VERSION 5.8 ;
BUSBITCHARS "[]" ;
DIVIDERCHAR "/" ;
UNITS
    DATABASE MICRONS 1000 ;
END UNITS

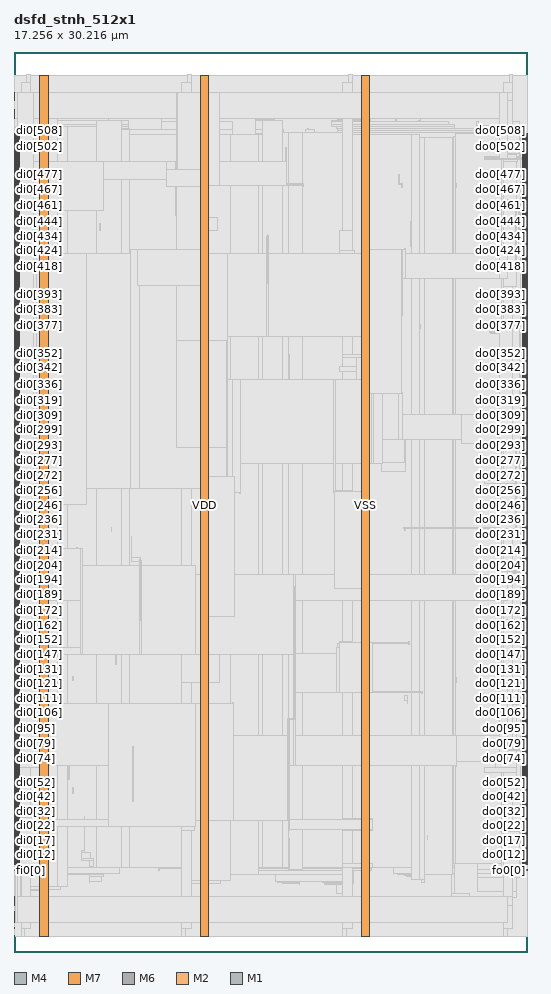
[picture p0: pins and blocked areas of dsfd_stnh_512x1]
MACRO dsfd_stnh_512x1
  FOREIGN dsfd_stnh_512x1 0 0 ;
  CLASS BLOCK ;
  SIZE 17.256 BY 30.216 ;
  PIN di0[0]
    DIRECTION INPUT ;
    USE SIGNAL ;
    PORT
      LAYER M4 ;
        RECT  0 2.928 0.192 2.952 ;
    END
  END di0[0]
  PIN di0[100]
    DIRECTION INPUT ;
    USE SIGNAL ;
    PORT
      LAYER M4 ;
        RECT  0 7.728 0.192 7.752 ;
    END
  END di0[100]
  PIN di0[101]
    DIRECTION INPUT ;
    USE SIGNAL ;
    PORT
      LAYER M4 ;
        RECT  0 7.776 0.192 7.8 ;
    END
  END di0[101]
  PIN di0[102]
    DIRECTION INPUT ;
    USE SIGNAL ;
    PORT
      LAYER M4 ;
        RECT  0 7.824 0.192 7.848 ;
    END
  END di0[102]
  PIN di0[103]
    DIRECTION INPUT ;
    USE SIGNAL ;
    PORT
      LAYER M4 ;
        RECT  0 7.872 0.192 7.896 ;
    END
  END di0[103]
  PIN di0[104]
    DIRECTION INPUT ;
    USE SIGNAL ;
    PORT
      LAYER M4 ;
        RECT  0 7.92 0.192 7.944 ;
    END
  END di0[104]
  PIN di0[105]
    DIRECTION INPUT ;
    USE SIGNAL ;
    PORT
      LAYER M4 ;
        RECT  0 7.968 0.192 7.992 ;
    END
  END di0[105]
  PIN di0[106]
    DIRECTION INPUT ;
    USE SIGNAL ;
    PORT
      LAYER M4 ;
        RECT  0 8.016 0.192 8.04 ;
    END
  END di0[106]
  PIN di0[107]
    DIRECTION INPUT ;
    USE SIGNAL ;
    PORT
      LAYER M4 ;
        RECT  0 8.064 0.192 8.088 ;
    END
  END di0[107]
  PIN di0[108]
    DIRECTION INPUT ;
    USE SIGNAL ;
    PORT
      LAYER M4 ;
        RECT  0 8.112 0.192 8.136 ;
    END
  END di0[108]
  PIN di0[109]
    DIRECTION INPUT ;
    USE SIGNAL ;
    PORT
      LAYER M4 ;
        RECT  0 8.16 0.192 8.184 ;
    END
  END di0[109]
  PIN di0[10]
    DIRECTION INPUT ;
    USE SIGNAL ;
    PORT
      LAYER M4 ;
        RECT  0 3.408 0.192 3.432 ;
    END
  END di0[10]
  PIN di0[110]
    DIRECTION INPUT ;
    USE SIGNAL ;
    PORT
      LAYER M4 ;
        RECT  0 8.208 0.192 8.232 ;
    END
  END di0[110]
  PIN di0[111]
    DIRECTION INPUT ;
    USE SIGNAL ;
    PORT
      LAYER M4 ;
        RECT  0 8.256 0.192 8.28 ;
    END
  END di0[111]
  PIN di0[112]
    DIRECTION INPUT ;
    USE SIGNAL ;
    PORT
      LAYER M4 ;
        RECT  0 8.304 0.192 8.328 ;
    END
  END di0[112]
  PIN di0[113]
    DIRECTION INPUT ;
    USE SIGNAL ;
    PORT
      LAYER M4 ;
        RECT  0 8.352 0.192 8.376 ;
    END
  END di0[113]
  PIN di0[114]
    DIRECTION INPUT ;
    USE SIGNAL ;
    PORT
      LAYER M4 ;
        RECT  0 8.4 0.192 8.424 ;
    END
  END di0[114]
  PIN di0[115]
    DIRECTION INPUT ;
    USE SIGNAL ;
    PORT
      LAYER M4 ;
        RECT  0 8.448 0.192 8.472 ;
    END
  END di0[115]
  PIN di0[116]
    DIRECTION INPUT ;
    USE SIGNAL ;
    PORT
      LAYER M4 ;
        RECT  0 8.496 0.192 8.52 ;
    END
  END di0[116]
  PIN di0[117]
    DIRECTION INPUT ;
    USE SIGNAL ;
    PORT
      LAYER M4 ;
        RECT  0 8.544 0.192 8.568 ;
    END
  END di0[117]
  PIN di0[118]
    DIRECTION INPUT ;
    USE SIGNAL ;
    PORT
      LAYER M4 ;
        RECT  0 8.592 0.192 8.616 ;
    END
  END di0[118]
  PIN di0[119]
    DIRECTION INPUT ;
    USE SIGNAL ;
    PORT
      LAYER M4 ;
        RECT  0 8.64 0.192 8.664 ;
    END
  END di0[119]
  PIN di0[11]
    DIRECTION INPUT ;
    USE SIGNAL ;
    PORT
      LAYER M4 ;
        RECT  0 3.456 0.192 3.48 ;
    END
  END di0[11]
  PIN di0[120]
    DIRECTION INPUT ;
    USE SIGNAL ;
    PORT
      LAYER M4 ;
        RECT  0 8.688 0.192 8.712 ;
    END
  END di0[120]
  PIN di0[121]
    DIRECTION INPUT ;
    USE SIGNAL ;
    PORT
      LAYER M4 ;
        RECT  0 8.736 0.192 8.76 ;
    END
  END di0[121]
  PIN di0[122]
    DIRECTION INPUT ;
    USE SIGNAL ;
    PORT
      LAYER M4 ;
        RECT  0 8.784 0.192 8.808 ;
    END
  END di0[122]
  PIN di0[123]
    DIRECTION INPUT ;
    USE SIGNAL ;
    PORT
      LAYER M4 ;
        RECT  0 8.832 0.192 8.856 ;
    END
  END di0[123]
  PIN di0[124]
    DIRECTION INPUT ;
    USE SIGNAL ;
    PORT
      LAYER M4 ;
        RECT  0 8.88 0.192 8.904 ;
    END
  END di0[124]
  PIN di0[125]
    DIRECTION INPUT ;
    USE SIGNAL ;
    PORT
      LAYER M4 ;
        RECT  0 8.928 0.192 8.952 ;
    END
  END di0[125]
  PIN di0[126]
    DIRECTION INPUT ;
    USE SIGNAL ;
    PORT
      LAYER M4 ;
        RECT  0 8.976 0.192 9 ;
    END
  END di0[126]
  PIN di0[127]
    DIRECTION INPUT ;
    USE SIGNAL ;
    PORT
      LAYER M4 ;
        RECT  0 9.024 0.192 9.048 ;
    END
  END di0[127]
  PIN di0[128]
    DIRECTION INPUT ;
    USE SIGNAL ;
    PORT
      LAYER M4 ;
        RECT  0 9.072 0.192 9.096 ;
    END
  END di0[128]
  PIN di0[129]
    DIRECTION INPUT ;
    USE SIGNAL ;
    PORT
      LAYER M4 ;
        RECT  0 9.12 0.192 9.144 ;
    END
  END di0[129]
  PIN di0[12]
    DIRECTION INPUT ;
    USE SIGNAL ;
    PORT
      LAYER M4 ;
        RECT  0 3.504 0.192 3.528 ;
    END
  END di0[12]
  PIN di0[130]
    DIRECTION INPUT ;
    USE SIGNAL ;
    PORT
      LAYER M4 ;
        RECT  0 9.168 0.192 9.192 ;
    END
  END di0[130]
  PIN di0[131]
    DIRECTION INPUT ;
    USE SIGNAL ;
    PORT
      LAYER M4 ;
        RECT  0 9.216 0.192 9.24 ;
    END
  END di0[131]
  PIN di0[132]
    DIRECTION INPUT ;
    USE SIGNAL ;
    PORT
      LAYER M4 ;
        RECT  0 9.264 0.192 9.288 ;
    END
  END di0[132]
  PIN di0[133]
    DIRECTION INPUT ;
    USE SIGNAL ;
    PORT
      LAYER M4 ;
        RECT  0 9.312 0.192 9.336 ;
    END
  END di0[133]
  PIN di0[134]
    DIRECTION INPUT ;
    USE SIGNAL ;
    PORT
      LAYER M4 ;
        RECT  0 9.36 0.192 9.384 ;
    END
  END di0[134]
  PIN di0[135]
    DIRECTION INPUT ;
    USE SIGNAL ;
    PORT
      LAYER M4 ;
        RECT  0 9.408 0.192 9.432 ;
    END
  END di0[135]
  PIN di0[136]
    DIRECTION INPUT ;
    USE SIGNAL ;
    PORT
      LAYER M4 ;
        RECT  0 9.456 0.192 9.48 ;
    END
  END di0[136]
  PIN di0[137]
    DIRECTION INPUT ;
    USE SIGNAL ;
    PORT
      LAYER M4 ;
        RECT  0 9.504 0.192 9.528 ;
    END
  END di0[137]
  PIN di0[138]
    DIRECTION INPUT ;
    USE SIGNAL ;
    PORT
      LAYER M4 ;
        RECT  0 9.552 0.192 9.576 ;
    END
  END di0[138]
  PIN di0[139]
    DIRECTION INPUT ;
    USE SIGNAL ;
    PORT
      LAYER M4 ;
        RECT  0 9.6 0.192 9.624 ;
    END
  END di0[139]
  PIN di0[13]
    DIRECTION INPUT ;
    USE SIGNAL ;
    PORT
      LAYER M4 ;
        RECT  0 3.552 0.192 3.576 ;
    END
  END di0[13]
  PIN di0[140]
    DIRECTION INPUT ;
    USE SIGNAL ;
    PORT
      LAYER M4 ;
        RECT  0 9.648 0.192 9.672 ;
    END
  END di0[140]
  PIN di0[141]
    DIRECTION INPUT ;
    USE SIGNAL ;
    PORT
      LAYER M4 ;
        RECT  0 9.696 0.192 9.72 ;
    END
  END di0[141]
  PIN di0[142]
    DIRECTION INPUT ;
    USE SIGNAL ;
    PORT
      LAYER M4 ;
        RECT  0 9.744 0.192 9.768 ;
    END
  END di0[142]
  PIN di0[143]
    DIRECTION INPUT ;
    USE SIGNAL ;
    PORT
      LAYER M4 ;
        RECT  0 9.792 0.192 9.816 ;
    END
  END di0[143]
  PIN di0[144]
    DIRECTION INPUT ;
    USE SIGNAL ;
    PORT
      LAYER M4 ;
        RECT  0 9.84 0.192 9.864 ;
    END
  END di0[144]
  PIN di0[145]
    DIRECTION INPUT ;
    USE SIGNAL ;
    PORT
      LAYER M4 ;
        RECT  0 9.888 0.192 9.912 ;
    END
  END di0[145]
  PIN di0[146]
    DIRECTION INPUT ;
    USE SIGNAL ;
    PORT
      LAYER M4 ;
        RECT  0 9.936 0.192 9.96 ;
    END
  END di0[146]
  PIN di0[147]
    DIRECTION INPUT ;
    USE SIGNAL ;
    PORT
      LAYER M4 ;
        RECT  0 9.984 0.192 10.008 ;
    END
  END di0[147]
  PIN di0[148]
    DIRECTION INPUT ;
    USE SIGNAL ;
    PORT
      LAYER M4 ;
        RECT  0 10.032 0.192 10.056 ;
    END
  END di0[148]
  PIN di0[149]
    DIRECTION INPUT ;
    USE SIGNAL ;
    PORT
      LAYER M4 ;
        RECT  0 10.08 0.192 10.104 ;
    END
  END di0[149]
  PIN di0[14]
    DIRECTION INPUT ;
    USE SIGNAL ;
    PORT
      LAYER M4 ;
        RECT  0 3.6 0.192 3.624 ;
    END
  END di0[14]
  PIN di0[150]
    DIRECTION INPUT ;
    USE SIGNAL ;
    PORT
      LAYER M4 ;
        RECT  0 10.128 0.192 10.152 ;
    END
  END di0[150]
  PIN di0[151]
    DIRECTION INPUT ;
    USE SIGNAL ;
    PORT
      LAYER M4 ;
        RECT  0 10.176 0.192 10.2 ;
    END
  END di0[151]
  PIN di0[152]
    DIRECTION INPUT ;
    USE SIGNAL ;
    PORT
      LAYER M4 ;
        RECT  0 10.224 0.192 10.248 ;
    END
  END di0[152]
  PIN di0[153]
    DIRECTION INPUT ;
    USE SIGNAL ;
    PORT
      LAYER M4 ;
        RECT  0 10.272 0.192 10.296 ;
    END
  END di0[153]
  PIN di0[154]
    DIRECTION INPUT ;
    USE SIGNAL ;
    PORT
      LAYER M4 ;
        RECT  0 10.32 0.192 10.344 ;
    END
  END di0[154]
  PIN di0[155]
    DIRECTION INPUT ;
    USE SIGNAL ;
    PORT
      LAYER M4 ;
        RECT  0 10.368 0.192 10.392 ;
    END
  END di0[155]
  PIN di0[156]
    DIRECTION INPUT ;
    USE SIGNAL ;
    PORT
      LAYER M4 ;
        RECT  0 10.416 0.192 10.44 ;
    END
  END di0[156]
  PIN di0[157]
    DIRECTION INPUT ;
    USE SIGNAL ;
    PORT
      LAYER M4 ;
        RECT  0 10.464 0.192 10.488 ;
    END
  END di0[157]
  PIN di0[158]
    DIRECTION INPUT ;
    USE SIGNAL ;
    PORT
      LAYER M4 ;
        RECT  0 10.512 0.192 10.536 ;
    END
  END di0[158]
  PIN di0[159]
    DIRECTION INPUT ;
    USE SIGNAL ;
    PORT
      LAYER M4 ;
        RECT  0 10.56 0.192 10.584 ;
    END
  END di0[159]
  PIN di0[15]
    DIRECTION INPUT ;
    USE SIGNAL ;
    PORT
      LAYER M4 ;
        RECT  0 3.648 0.192 3.672 ;
    END
  END di0[15]
  PIN di0[160]
    DIRECTION INPUT ;
    USE SIGNAL ;
    PORT
      LAYER M4 ;
        RECT  0 10.608 0.192 10.632 ;
    END
  END di0[160]
  PIN di0[161]
    DIRECTION INPUT ;
    USE SIGNAL ;
    PORT
      LAYER M4 ;
        RECT  0 10.656 0.192 10.68 ;
    END
  END di0[161]
  PIN di0[162]
    DIRECTION INPUT ;
    USE SIGNAL ;
    PORT
      LAYER M4 ;
        RECT  0 10.704 0.192 10.728 ;
    END
  END di0[162]
  PIN di0[163]
    DIRECTION INPUT ;
    USE SIGNAL ;
    PORT
      LAYER M4 ;
        RECT  0 10.752 0.192 10.776 ;
    END
  END di0[163]
  PIN di0[164]
    DIRECTION INPUT ;
    USE SIGNAL ;
    PORT
      LAYER M4 ;
        RECT  0 10.8 0.192 10.824 ;
    END
  END di0[164]
  PIN di0[165]
    DIRECTION INPUT ;
    USE SIGNAL ;
    PORT
      LAYER M4 ;
        RECT  0 10.848 0.192 10.872 ;
    END
  END di0[165]
  PIN di0[166]
    DIRECTION INPUT ;
    USE SIGNAL ;
    PORT
      LAYER M4 ;
        RECT  0 10.896 0.192 10.92 ;
    END
  END di0[166]
  PIN di0[167]
    DIRECTION INPUT ;
    USE SIGNAL ;
    PORT
      LAYER M4 ;
        RECT  0 10.944 0.192 10.968 ;
    END
  END di0[167]
  PIN di0[168]
    DIRECTION INPUT ;
    USE SIGNAL ;
    PORT
      LAYER M4 ;
        RECT  0 10.992 0.192 11.016 ;
    END
  END di0[168]
  PIN di0[169]
    DIRECTION INPUT ;
    USE SIGNAL ;
    PORT
      LAYER M4 ;
        RECT  0 11.04 0.192 11.064 ;
    END
  END di0[169]
  PIN di0[16]
    DIRECTION INPUT ;
    USE SIGNAL ;
    PORT
      LAYER M4 ;
        RECT  0 3.696 0.192 3.72 ;
    END
  END di0[16]
  PIN di0[170]
    DIRECTION INPUT ;
    USE SIGNAL ;
    PORT
      LAYER M4 ;
        RECT  0 11.088 0.192 11.112 ;
    END
  END di0[170]
  PIN di0[171]
    DIRECTION INPUT ;
    USE SIGNAL ;
    PORT
      LAYER M4 ;
        RECT  0 11.136 0.192 11.16 ;
    END
  END di0[171]
  PIN di0[172]
    DIRECTION INPUT ;
    USE SIGNAL ;
    PORT
      LAYER M4 ;
        RECT  0 11.184 0.192 11.208 ;
    END
  END di0[172]
  PIN di0[173]
    DIRECTION INPUT ;
    USE SIGNAL ;
    PORT
      LAYER M4 ;
        RECT  0 11.232 0.192 11.256 ;
    END
  END di0[173]
  PIN di0[174]
    DIRECTION INPUT ;
    USE SIGNAL ;
    PORT
      LAYER M4 ;
        RECT  0 11.28 0.192 11.304 ;
    END
  END di0[174]
  PIN di0[175]
    DIRECTION INPUT ;
    USE SIGNAL ;
    PORT
      LAYER M4 ;
        RECT  0 11.328 0.192 11.352 ;
    END
  END di0[175]
  PIN di0[176]
    DIRECTION INPUT ;
    USE SIGNAL ;
    PORT
      LAYER M4 ;
        RECT  0 11.376 0.192 11.4 ;
    END
  END di0[176]
  PIN di0[177]
    DIRECTION INPUT ;
    USE SIGNAL ;
    PORT
      LAYER M4 ;
        RECT  0 11.424 0.192 11.448 ;
    END
  END di0[177]
  PIN di0[178]
    DIRECTION INPUT ;
    USE SIGNAL ;
    PORT
      LAYER M4 ;
        RECT  0 11.472 0.192 11.496 ;
    END
  END di0[178]
  PIN di0[179]
    DIRECTION INPUT ;
    USE SIGNAL ;
    PORT
      LAYER M4 ;
        RECT  0 11.52 0.192 11.544 ;
    END
  END di0[179]
  PIN di0[17]
    DIRECTION INPUT ;
    USE SIGNAL ;
    PORT
      LAYER M4 ;
        RECT  0 3.744 0.192 3.768 ;
    END
  END di0[17]
  PIN di0[180]
    DIRECTION INPUT ;
    USE SIGNAL ;
    PORT
      LAYER M4 ;
        RECT  0 11.568 0.192 11.592 ;
    END
  END di0[180]
  PIN di0[181]
    DIRECTION INPUT ;
    USE SIGNAL ;
    PORT
      LAYER M4 ;
        RECT  0 11.616 0.192 11.64 ;
    END
  END di0[181]
  PIN di0[182]
    DIRECTION INPUT ;
    USE SIGNAL ;
    PORT
      LAYER M4 ;
        RECT  0 11.664 0.192 11.688 ;
    END
  END di0[182]
  PIN di0[183]
    DIRECTION INPUT ;
    USE SIGNAL ;
    PORT
      LAYER M4 ;
        RECT  0 11.712 0.192 11.736 ;
    END
  END di0[183]
  PIN di0[184]
    DIRECTION INPUT ;
    USE SIGNAL ;
    PORT
      LAYER M4 ;
        RECT  0 11.76 0.192 11.784 ;
    END
  END di0[184]
  PIN di0[185]
    DIRECTION INPUT ;
    USE SIGNAL ;
    PORT
      LAYER M4 ;
        RECT  0 11.808 0.192 11.832 ;
    END
  END di0[185]
  PIN di0[186]
    DIRECTION INPUT ;
    USE SIGNAL ;
    PORT
      LAYER M4 ;
        RECT  0 11.856 0.192 11.88 ;
    END
  END di0[186]
  PIN di0[187]
    DIRECTION INPUT ;
    USE SIGNAL ;
    PORT
      LAYER M4 ;
        RECT  0 11.904 0.192 11.928 ;
    END
  END di0[187]
  PIN di0[188]
    DIRECTION INPUT ;
    USE SIGNAL ;
    PORT
      LAYER M4 ;
        RECT  0 11.952 0.192 11.976 ;
    END
  END di0[188]
  PIN di0[189]
    DIRECTION INPUT ;
    USE SIGNAL ;
    PORT
      LAYER M4 ;
        RECT  0 12 0.192 12.024 ;
    END
  END di0[189]
  PIN di0[18]
    DIRECTION INPUT ;
    USE SIGNAL ;
    PORT
      LAYER M4 ;
        RECT  0 3.792 0.192 3.816 ;
    END
  END di0[18]
  PIN di0[190]
    DIRECTION INPUT ;
    USE SIGNAL ;
    PORT
      LAYER M4 ;
        RECT  0 12.048 0.192 12.072 ;
    END
  END di0[190]
  PIN di0[191]
    DIRECTION INPUT ;
    USE SIGNAL ;
    PORT
      LAYER M4 ;
        RECT  0 12.096 0.192 12.12 ;
    END
  END di0[191]
  PIN di0[192]
    DIRECTION INPUT ;
    USE SIGNAL ;
    PORT
      LAYER M4 ;
        RECT  0 12.144 0.192 12.168 ;
    END
  END di0[192]
  PIN di0[193]
    DIRECTION INPUT ;
    USE SIGNAL ;
    PORT
      LAYER M4 ;
        RECT  0 12.192 0.192 12.216 ;
    END
  END di0[193]
  PIN di0[194]
    DIRECTION INPUT ;
    USE SIGNAL ;
    PORT
      LAYER M4 ;
        RECT  0 12.24 0.192 12.264 ;
    END
  END di0[194]
  PIN di0[195]
    DIRECTION INPUT ;
    USE SIGNAL ;
    PORT
      LAYER M4 ;
        RECT  0 12.288 0.192 12.312 ;
    END
  END di0[195]
  PIN di0[196]
    DIRECTION INPUT ;
    USE SIGNAL ;
    PORT
      LAYER M4 ;
        RECT  0 12.336 0.192 12.36 ;
    END
  END di0[196]
  PIN di0[197]
    DIRECTION INPUT ;
    USE SIGNAL ;
    PORT
      LAYER M4 ;
        RECT  0 12.384 0.192 12.408 ;
    END
  END di0[197]
  PIN di0[198]
    DIRECTION INPUT ;
    USE SIGNAL ;
    PORT
      LAYER M4 ;
        RECT  0 12.432 0.192 12.456 ;
    END
  END di0[198]
  PIN di0[199]
    DIRECTION INPUT ;
    USE SIGNAL ;
    PORT
      LAYER M4 ;
        RECT  0 12.48 0.192 12.504 ;
    END
  END di0[199]
  PIN di0[19]
    DIRECTION INPUT ;
    USE SIGNAL ;
    PORT
      LAYER M4 ;
        RECT  0 3.84 0.192 3.864 ;
    END
  END di0[19]
  PIN di0[1]
    DIRECTION INPUT ;
    USE SIGNAL ;
    PORT
      LAYER M4 ;
        RECT  0 2.976 0.192 3 ;
    END
  END di0[1]
  PIN di0[200]
    DIRECTION INPUT ;
    USE SIGNAL ;
    PORT
      LAYER M4 ;
        RECT  0 12.528 0.192 12.552 ;
    END
  END di0[200]
  PIN di0[201]
    DIRECTION INPUT ;
    USE SIGNAL ;
    PORT
      LAYER M4 ;
        RECT  0 12.576 0.192 12.6 ;
    END
  END di0[201]
  PIN di0[202]
    DIRECTION INPUT ;
    USE SIGNAL ;
    PORT
      LAYER M4 ;
        RECT  0 12.624 0.192 12.648 ;
    END
  END di0[202]
  PIN di0[203]
    DIRECTION INPUT ;
    USE SIGNAL ;
    PORT
      LAYER M4 ;
        RECT  0 12.672 0.192 12.696 ;
    END
  END di0[203]
  PIN di0[204]
    DIRECTION INPUT ;
    USE SIGNAL ;
    PORT
      LAYER M4 ;
        RECT  0 12.72 0.192 12.744 ;
    END
  END di0[204]
  PIN di0[205]
    DIRECTION INPUT ;
    USE SIGNAL ;
    PORT
      LAYER M4 ;
        RECT  0 12.768 0.192 12.792 ;
    END
  END di0[205]
  PIN di0[206]
    DIRECTION INPUT ;
    USE SIGNAL ;
    PORT
      LAYER M4 ;
        RECT  0 12.816 0.192 12.84 ;
    END
  END di0[206]
  PIN di0[207]
    DIRECTION INPUT ;
    USE SIGNAL ;
    PORT
      LAYER M4 ;
        RECT  0 12.864 0.192 12.888 ;
    END
  END di0[207]
  PIN di0[208]
    DIRECTION INPUT ;
    USE SIGNAL ;
    PORT
      LAYER M4 ;
        RECT  0 12.912 0.192 12.936 ;
    END
  END di0[208]
  PIN di0[209]
    DIRECTION INPUT ;
    USE SIGNAL ;
    PORT
      LAYER M4 ;
        RECT  0 12.96 0.192 12.984 ;
    END
  END di0[209]
  PIN di0[20]
    DIRECTION INPUT ;
    USE SIGNAL ;
    PORT
      LAYER M4 ;
        RECT  0 3.888 0.192 3.912 ;
    END
  END di0[20]
  PIN di0[210]
    DIRECTION INPUT ;
    USE SIGNAL ;
    PORT
      LAYER M4 ;
        RECT  0 13.008 0.192 13.032 ;
    END
  END di0[210]
  PIN di0[211]
    DIRECTION INPUT ;
    USE SIGNAL ;
    PORT
      LAYER M4 ;
        RECT  0 13.056 0.192 13.08 ;
    END
  END di0[211]
  PIN di0[212]
    DIRECTION INPUT ;
    USE SIGNAL ;
    PORT
      LAYER M4 ;
        RECT  0 13.104 0.192 13.128 ;
    END
  END di0[212]
  PIN di0[213]
    DIRECTION INPUT ;
    USE SIGNAL ;
    PORT
      LAYER M4 ;
        RECT  0 13.152 0.192 13.176 ;
    END
  END di0[213]
  PIN di0[214]
    DIRECTION INPUT ;
    USE SIGNAL ;
    PORT
      LAYER M4 ;
        RECT  0 13.2 0.192 13.224 ;
    END
  END di0[214]
  PIN di0[215]
    DIRECTION INPUT ;
    USE SIGNAL ;
    PORT
      LAYER M4 ;
        RECT  0 13.248 0.192 13.272 ;
    END
  END di0[215]
  PIN di0[216]
    DIRECTION INPUT ;
    USE SIGNAL ;
    PORT
      LAYER M4 ;
        RECT  0 13.296 0.192 13.32 ;
    END
  END di0[216]
  PIN di0[217]
    DIRECTION INPUT ;
    USE SIGNAL ;
    PORT
      LAYER M4 ;
        RECT  0 13.344 0.192 13.368 ;
    END
  END di0[217]
  PIN di0[218]
    DIRECTION INPUT ;
    USE SIGNAL ;
    PORT
      LAYER M4 ;
        RECT  0 13.392 0.192 13.416 ;
    END
  END di0[218]
  PIN di0[219]
    DIRECTION INPUT ;
    USE SIGNAL ;
    PORT
      LAYER M4 ;
        RECT  0 13.44 0.192 13.464 ;
    END
  END di0[219]
  PIN di0[21]
    DIRECTION INPUT ;
    USE SIGNAL ;
    PORT
      LAYER M4 ;
        RECT  0 3.936 0.192 3.96 ;
    END
  END di0[21]
  PIN di0[220]
    DIRECTION INPUT ;
    USE SIGNAL ;
    PORT
      LAYER M4 ;
        RECT  0 13.488 0.192 13.512 ;
    END
  END di0[220]
  PIN di0[221]
    DIRECTION INPUT ;
    USE SIGNAL ;
    PORT
      LAYER M4 ;
        RECT  0 13.536 0.192 13.56 ;
    END
  END di0[221]
  PIN di0[222]
    DIRECTION INPUT ;
    USE SIGNAL ;
    PORT
      LAYER M4 ;
        RECT  0 13.584 0.192 13.608 ;
    END
  END di0[222]
  PIN di0[223]
    DIRECTION INPUT ;
    USE SIGNAL ;
    PORT
      LAYER M4 ;
        RECT  0 13.632 0.192 13.656 ;
    END
  END di0[223]
  PIN di0[224]
    DIRECTION INPUT ;
    USE SIGNAL ;
    PORT
      LAYER M4 ;
        RECT  0 13.68 0.192 13.704 ;
    END
  END di0[224]
  PIN di0[225]
    DIRECTION INPUT ;
    USE SIGNAL ;
    PORT
      LAYER M4 ;
        RECT  0 13.728 0.192 13.752 ;
    END
  END di0[225]
  PIN di0[226]
    DIRECTION INPUT ;
    USE SIGNAL ;
    PORT
      LAYER M4 ;
        RECT  0 13.776 0.192 13.8 ;
    END
  END di0[226]
  PIN di0[227]
    DIRECTION INPUT ;
    USE SIGNAL ;
    PORT
      LAYER M4 ;
        RECT  0 13.824 0.192 13.848 ;
    END
  END di0[227]
  PIN di0[228]
    DIRECTION INPUT ;
    USE SIGNAL ;
    PORT
      LAYER M4 ;
        RECT  0 13.872 0.192 13.896 ;
    END
  END di0[228]
  PIN di0[229]
    DIRECTION INPUT ;
    USE SIGNAL ;
    PORT
      LAYER M4 ;
        RECT  0 13.92 0.192 13.944 ;
    END
  END di0[229]
  PIN di0[22]
    DIRECTION INPUT ;
    USE SIGNAL ;
    PORT
      LAYER M4 ;
        RECT  0 3.984 0.192 4.008 ;
    END
  END di0[22]
  PIN di0[230]
    DIRECTION INPUT ;
    USE SIGNAL ;
    PORT
      LAYER M4 ;
        RECT  0 13.968 0.192 13.992 ;
    END
  END di0[230]
  PIN di0[231]
    DIRECTION INPUT ;
    USE SIGNAL ;
    PORT
      LAYER M4 ;
        RECT  0 14.016 0.192 14.04 ;
    END
  END di0[231]
  PIN di0[232]
    DIRECTION INPUT ;
    USE SIGNAL ;
    PORT
      LAYER M4 ;
        RECT  0 14.064 0.192 14.088 ;
    END
  END di0[232]
  PIN di0[233]
    DIRECTION INPUT ;
    USE SIGNAL ;
    PORT
      LAYER M4 ;
        RECT  0 14.112 0.192 14.136 ;
    END
  END di0[233]
  PIN di0[234]
    DIRECTION INPUT ;
    USE SIGNAL ;
    PORT
      LAYER M4 ;
        RECT  0 14.16 0.192 14.184 ;
    END
  END di0[234]
  PIN di0[235]
    DIRECTION INPUT ;
    USE SIGNAL ;
    PORT
      LAYER M4 ;
        RECT  0 14.208 0.192 14.232 ;
    END
  END di0[235]
  PIN di0[236]
    DIRECTION INPUT ;
    USE SIGNAL ;
    PORT
      LAYER M4 ;
        RECT  0 14.256 0.192 14.28 ;
    END
  END di0[236]
  PIN di0[237]
    DIRECTION INPUT ;
    USE SIGNAL ;
    PORT
      LAYER M4 ;
        RECT  0 14.304 0.192 14.328 ;
    END
  END di0[237]
  PIN di0[238]
    DIRECTION INPUT ;
    USE SIGNAL ;
    PORT
      LAYER M4 ;
        RECT  0 14.352 0.192 14.376 ;
    END
  END di0[238]
  PIN di0[239]
    DIRECTION INPUT ;
    USE SIGNAL ;
    PORT
      LAYER M4 ;
        RECT  0 14.4 0.192 14.424 ;
    END
  END di0[239]
  PIN di0[23]
    DIRECTION INPUT ;
    USE SIGNAL ;
    PORT
      LAYER M4 ;
        RECT  0 4.032 0.192 4.056 ;
    END
  END di0[23]
  PIN di0[240]
    DIRECTION INPUT ;
    USE SIGNAL ;
    PORT
      LAYER M4 ;
        RECT  0 14.448 0.192 14.472 ;
    END
  END di0[240]
  PIN di0[241]
    DIRECTION INPUT ;
    USE SIGNAL ;
    PORT
      LAYER M4 ;
        RECT  0 14.496 0.192 14.52 ;
    END
  END di0[241]
  PIN di0[242]
    DIRECTION INPUT ;
    USE SIGNAL ;
    PORT
      LAYER M4 ;
        RECT  0 14.544 0.192 14.568 ;
    END
  END di0[242]
  PIN di0[243]
    DIRECTION INPUT ;
    USE SIGNAL ;
    PORT
      LAYER M4 ;
        RECT  0 14.592 0.192 14.616 ;
    END
  END di0[243]
  PIN di0[244]
    DIRECTION INPUT ;
    USE SIGNAL ;
    PORT
      LAYER M4 ;
        RECT  0 14.64 0.192 14.664 ;
    END
  END di0[244]
  PIN di0[245]
    DIRECTION INPUT ;
    USE SIGNAL ;
    PORT
      LAYER M4 ;
        RECT  0 14.688 0.192 14.712 ;
    END
  END di0[245]
  PIN di0[246]
    DIRECTION INPUT ;
    USE SIGNAL ;
    PORT
      LAYER M4 ;
        RECT  0 14.736 0.192 14.76 ;
    END
  END di0[246]
  PIN di0[247]
    DIRECTION INPUT ;
    USE SIGNAL ;
    PORT
      LAYER M4 ;
        RECT  0 14.784 0.192 14.808 ;
    END
  END di0[247]
  PIN di0[248]
    DIRECTION INPUT ;
    USE SIGNAL ;
    PORT
      LAYER M4 ;
        RECT  0 14.832 0.192 14.856 ;
    END
  END di0[248]
  PIN di0[249]
    DIRECTION INPUT ;
    USE SIGNAL ;
    PORT
      LAYER M4 ;
        RECT  0 14.88 0.192 14.904 ;
    END
  END di0[249]
  PIN di0[24]
    DIRECTION INPUT ;
    USE SIGNAL ;
    PORT
      LAYER M4 ;
        RECT  0 4.08 0.192 4.104 ;
    END
  END di0[24]
  PIN di0[250]
    DIRECTION INPUT ;
    USE SIGNAL ;
    PORT
      LAYER M4 ;
        RECT  0 14.928 0.192 14.952 ;
    END
  END di0[250]
  PIN di0[251]
    DIRECTION INPUT ;
    USE SIGNAL ;
    PORT
      LAYER M4 ;
        RECT  0 14.976 0.192 15 ;
    END
  END di0[251]
  PIN di0[252]
    DIRECTION INPUT ;
    USE SIGNAL ;
    PORT
      LAYER M4 ;
        RECT  0 15.024 0.192 15.048 ;
    END
  END di0[252]
  PIN di0[253]
    DIRECTION INPUT ;
    USE SIGNAL ;
    PORT
      LAYER M4 ;
        RECT  0 15.072 0.192 15.096 ;
    END
  END di0[253]
  PIN di0[254]
    DIRECTION INPUT ;
    USE SIGNAL ;
    PORT
      LAYER M4 ;
        RECT  0 15.12 0.192 15.144 ;
    END
  END di0[254]
  PIN di0[255]
    DIRECTION INPUT ;
    USE SIGNAL ;
    PORT
      LAYER M4 ;
        RECT  0 15.168 0.192 15.192 ;
    END
  END di0[255]
  PIN di0[256]
    DIRECTION INPUT ;
    USE SIGNAL ;
    PORT
      LAYER M4 ;
        RECT  0 15.216 0.192 15.24 ;
    END
  END di0[256]
  PIN di0[257]
    DIRECTION INPUT ;
    USE SIGNAL ;
    PORT
      LAYER M4 ;
        RECT  0 15.264 0.192 15.288 ;
    END
  END di0[257]
  PIN di0[258]
    DIRECTION INPUT ;
    USE SIGNAL ;
    PORT
      LAYER M4 ;
        RECT  0 15.312 0.192 15.336 ;
    END
  END di0[258]
  PIN di0[259]
    DIRECTION INPUT ;
    USE SIGNAL ;
    PORT
      LAYER M4 ;
        RECT  0 15.36 0.192 15.384 ;
    END
  END di0[259]
  PIN di0[25]
    DIRECTION INPUT ;
    USE SIGNAL ;
    PORT
      LAYER M4 ;
        RECT  0 4.128 0.192 4.152 ;
    END
  END di0[25]
  PIN di0[260]
    DIRECTION INPUT ;
    USE SIGNAL ;
    PORT
      LAYER M4 ;
        RECT  0 15.408 0.192 15.432 ;
    END
  END di0[260]
  PIN di0[261]
    DIRECTION INPUT ;
    USE SIGNAL ;
    PORT
      LAYER M4 ;
        RECT  0 15.456 0.192 15.48 ;
    END
  END di0[261]
  PIN di0[262]
    DIRECTION INPUT ;
    USE SIGNAL ;
    PORT
      LAYER M4 ;
        RECT  0 15.504 0.192 15.528 ;
    END
  END di0[262]
  PIN di0[263]
    DIRECTION INPUT ;
    USE SIGNAL ;
    PORT
      LAYER M4 ;
        RECT  0 15.552 0.192 15.576 ;
    END
  END di0[263]
  PIN di0[264]
    DIRECTION INPUT ;
    USE SIGNAL ;
    PORT
      LAYER M4 ;
        RECT  0 15.6 0.192 15.624 ;
    END
  END di0[264]
  PIN di0[265]
    DIRECTION INPUT ;
    USE SIGNAL ;
    PORT
      LAYER M4 ;
        RECT  0 15.648 0.192 15.672 ;
    END
  END di0[265]
  PIN di0[266]
    DIRECTION INPUT ;
    USE SIGNAL ;
    PORT
      LAYER M4 ;
        RECT  0 15.696 0.192 15.72 ;
    END
  END di0[266]
  PIN di0[267]
    DIRECTION INPUT ;
    USE SIGNAL ;
    PORT
      LAYER M4 ;
        RECT  0 15.744 0.192 15.768 ;
    END
  END di0[267]
  PIN di0[268]
    DIRECTION INPUT ;
    USE SIGNAL ;
    PORT
      LAYER M4 ;
        RECT  0 15.792 0.192 15.816 ;
    END
  END di0[268]
  PIN di0[269]
    DIRECTION INPUT ;
    USE SIGNAL ;
    PORT
      LAYER M4 ;
        RECT  0 15.84 0.192 15.864 ;
    END
  END di0[269]
  PIN di0[26]
    DIRECTION INPUT ;
    USE SIGNAL ;
    PORT
      LAYER M4 ;
        RECT  0 4.176 0.192 4.2 ;
    END
  END di0[26]
  PIN di0[270]
    DIRECTION INPUT ;
    USE SIGNAL ;
    PORT
      LAYER M4 ;
        RECT  0 15.888 0.192 15.912 ;
    END
  END di0[270]
  PIN di0[271]
    DIRECTION INPUT ;
    USE SIGNAL ;
    PORT
      LAYER M4 ;
        RECT  0 15.936 0.192 15.96 ;
    END
  END di0[271]
  PIN di0[272]
    DIRECTION INPUT ;
    USE SIGNAL ;
    PORT
      LAYER M4 ;
        RECT  0 15.984 0.192 16.008 ;
    END
  END di0[272]
  PIN di0[273]
    DIRECTION INPUT ;
    USE SIGNAL ;
    PORT
      LAYER M4 ;
        RECT  0 16.032 0.192 16.056 ;
    END
  END di0[273]
  PIN di0[274]
    DIRECTION INPUT ;
    USE SIGNAL ;
    PORT
      LAYER M4 ;
        RECT  0 16.08 0.192 16.104 ;
    END
  END di0[274]
  PIN di0[275]
    DIRECTION INPUT ;
    USE SIGNAL ;
    PORT
      LAYER M4 ;
        RECT  0 16.128 0.192 16.152 ;
    END
  END di0[275]
  PIN di0[276]
    DIRECTION INPUT ;
    USE SIGNAL ;
    PORT
      LAYER M4 ;
        RECT  0 16.176 0.192 16.2 ;
    END
  END di0[276]
  PIN di0[277]
    DIRECTION INPUT ;
    USE SIGNAL ;
    PORT
      LAYER M4 ;
        RECT  0 16.224 0.192 16.248 ;
    END
  END di0[277]
  PIN di0[278]
    DIRECTION INPUT ;
    USE SIGNAL ;
    PORT
      LAYER M4 ;
        RECT  0 16.272 0.192 16.296 ;
    END
  END di0[278]
  PIN di0[279]
    DIRECTION INPUT ;
    USE SIGNAL ;
    PORT
      LAYER M4 ;
        RECT  0 16.32 0.192 16.344 ;
    END
  END di0[279]
  PIN di0[27]
    DIRECTION INPUT ;
    USE SIGNAL ;
    PORT
      LAYER M4 ;
        RECT  0 4.224 0.192 4.248 ;
    END
  END di0[27]
  PIN di0[280]
    DIRECTION INPUT ;
    USE SIGNAL ;
    PORT
      LAYER M4 ;
        RECT  0 16.368 0.192 16.392 ;
    END
  END di0[280]
  PIN di0[281]
    DIRECTION INPUT ;
    USE SIGNAL ;
    PORT
      LAYER M4 ;
        RECT  0 16.416 0.192 16.44 ;
    END
  END di0[281]
  PIN di0[282]
    DIRECTION INPUT ;
    USE SIGNAL ;
    PORT
      LAYER M4 ;
        RECT  0 16.464 0.192 16.488 ;
    END
  END di0[282]
  PIN di0[283]
    DIRECTION INPUT ;
    USE SIGNAL ;
    PORT
      LAYER M4 ;
        RECT  0 16.512 0.192 16.536 ;
    END
  END di0[283]
  PIN di0[284]
    DIRECTION INPUT ;
    USE SIGNAL ;
    PORT
      LAYER M4 ;
        RECT  0 16.56 0.192 16.584 ;
    END
  END di0[284]
  PIN di0[285]
    DIRECTION INPUT ;
    USE SIGNAL ;
    PORT
      LAYER M4 ;
        RECT  0 16.608 0.192 16.632 ;
    END
  END di0[285]
  PIN di0[286]
    DIRECTION INPUT ;
    USE SIGNAL ;
    PORT
      LAYER M4 ;
        RECT  0 16.656 0.192 16.68 ;
    END
  END di0[286]
  PIN di0[287]
    DIRECTION INPUT ;
    USE SIGNAL ;
    PORT
      LAYER M4 ;
        RECT  0 16.704 0.192 16.728 ;
    END
  END di0[287]
  PIN di0[288]
    DIRECTION INPUT ;
    USE SIGNAL ;
    PORT
      LAYER M4 ;
        RECT  0 16.752 0.192 16.776 ;
    END
  END di0[288]
  PIN di0[289]
    DIRECTION INPUT ;
    USE SIGNAL ;
    PORT
      LAYER M4 ;
        RECT  0 16.8 0.192 16.824 ;
    END
  END di0[289]
  PIN di0[28]
    DIRECTION INPUT ;
    USE SIGNAL ;
    PORT
      LAYER M4 ;
        RECT  0 4.272 0.192 4.296 ;
    END
  END di0[28]
  PIN di0[290]
    DIRECTION INPUT ;
    USE SIGNAL ;
    PORT
      LAYER M4 ;
        RECT  0 16.848 0.192 16.872 ;
    END
  END di0[290]
  PIN di0[291]
    DIRECTION INPUT ;
    USE SIGNAL ;
    PORT
      LAYER M4 ;
        RECT  0 16.896 0.192 16.92 ;
    END
  END di0[291]
  PIN di0[292]
    DIRECTION INPUT ;
    USE SIGNAL ;
    PORT
      LAYER M4 ;
        RECT  0 16.944 0.192 16.968 ;
    END
  END di0[292]
  PIN di0[293]
    DIRECTION INPUT ;
    USE SIGNAL ;
    PORT
      LAYER M4 ;
        RECT  0 16.992 0.192 17.016 ;
    END
  END di0[293]
  PIN di0[294]
    DIRECTION INPUT ;
    USE SIGNAL ;
    PORT
      LAYER M4 ;
        RECT  0 17.04 0.192 17.064 ;
    END
  END di0[294]
  PIN di0[295]
    DIRECTION INPUT ;
    USE SIGNAL ;
    PORT
      LAYER M4 ;
        RECT  0 17.088 0.192 17.112 ;
    END
  END di0[295]
  PIN di0[296]
    DIRECTION INPUT ;
    USE SIGNAL ;
    PORT
      LAYER M4 ;
        RECT  0 17.136 0.192 17.16 ;
    END
  END di0[296]
  PIN di0[297]
    DIRECTION INPUT ;
    USE SIGNAL ;
    PORT
      LAYER M4 ;
        RECT  0 17.184 0.192 17.208 ;
    END
  END di0[297]
  PIN di0[298]
    DIRECTION INPUT ;
    USE SIGNAL ;
    PORT
      LAYER M4 ;
        RECT  0 17.232 0.192 17.256 ;
    END
  END di0[298]
  PIN di0[299]
    DIRECTION INPUT ;
    USE SIGNAL ;
    PORT
      LAYER M4 ;
        RECT  0 17.28 0.192 17.304 ;
    END
  END di0[299]
  PIN di0[29]
    DIRECTION INPUT ;
    USE SIGNAL ;
    PORT
      LAYER M4 ;
        RECT  0 4.32 0.192 4.344 ;
    END
  END di0[29]
  PIN di0[2]
    DIRECTION INPUT ;
    USE SIGNAL ;
    PORT
      LAYER M4 ;
        RECT  0 3.024 0.192 3.048 ;
    END
  END di0[2]
  PIN di0[300]
    DIRECTION INPUT ;
    USE SIGNAL ;
    PORT
      LAYER M4 ;
        RECT  0 17.328 0.192 17.352 ;
    END
  END di0[300]
  PIN di0[301]
    DIRECTION INPUT ;
    USE SIGNAL ;
    PORT
      LAYER M4 ;
        RECT  0 17.376 0.192 17.4 ;
    END
  END di0[301]
  PIN di0[302]
    DIRECTION INPUT ;
    USE SIGNAL ;
    PORT
      LAYER M4 ;
        RECT  0 17.424 0.192 17.448 ;
    END
  END di0[302]
  PIN di0[303]
    DIRECTION INPUT ;
    USE SIGNAL ;
    PORT
      LAYER M4 ;
        RECT  0 17.472 0.192 17.496 ;
    END
  END di0[303]
  PIN di0[304]
    DIRECTION INPUT ;
    USE SIGNAL ;
    PORT
      LAYER M4 ;
        RECT  0 17.52 0.192 17.544 ;
    END
  END di0[304]
  PIN di0[305]
    DIRECTION INPUT ;
    USE SIGNAL ;
    PORT
      LAYER M4 ;
        RECT  0 17.568 0.192 17.592 ;
    END
  END di0[305]
  PIN di0[306]
    DIRECTION INPUT ;
    USE SIGNAL ;
    PORT
      LAYER M4 ;
        RECT  0 17.616 0.192 17.64 ;
    END
  END di0[306]
  PIN di0[307]
    DIRECTION INPUT ;
    USE SIGNAL ;
    PORT
      LAYER M4 ;
        RECT  0 17.664 0.192 17.688 ;
    END
  END di0[307]
  PIN di0[308]
    DIRECTION INPUT ;
    USE SIGNAL ;
    PORT
      LAYER M4 ;
        RECT  0 17.712 0.192 17.736 ;
    END
  END di0[308]
  PIN di0[309]
    DIRECTION INPUT ;
    USE SIGNAL ;
    PORT
      LAYER M4 ;
        RECT  0 17.76 0.192 17.784 ;
    END
  END di0[309]
  PIN di0[30]
    DIRECTION INPUT ;
    USE SIGNAL ;
    PORT
      LAYER M4 ;
        RECT  0 4.368 0.192 4.392 ;
    END
  END di0[30]
  PIN di0[310]
    DIRECTION INPUT ;
    USE SIGNAL ;
    PORT
      LAYER M4 ;
        RECT  0 17.808 0.192 17.832 ;
    END
  END di0[310]
  PIN di0[311]
    DIRECTION INPUT ;
    USE SIGNAL ;
    PORT
      LAYER M4 ;
        RECT  0 17.856 0.192 17.88 ;
    END
  END di0[311]
  PIN di0[312]
    DIRECTION INPUT ;
    USE SIGNAL ;
    PORT
      LAYER M4 ;
        RECT  0 17.904 0.192 17.928 ;
    END
  END di0[312]
  PIN di0[313]
    DIRECTION INPUT ;
    USE SIGNAL ;
    PORT
      LAYER M4 ;
        RECT  0 17.952 0.192 17.976 ;
    END
  END di0[313]
  PIN di0[314]
    DIRECTION INPUT ;
    USE SIGNAL ;
    PORT
      LAYER M4 ;
        RECT  0 18 0.192 18.024 ;
    END
  END di0[314]
  PIN di0[315]
    DIRECTION INPUT ;
    USE SIGNAL ;
    PORT
      LAYER M4 ;
        RECT  0 18.048 0.192 18.072 ;
    END
  END di0[315]
  PIN di0[316]
    DIRECTION INPUT ;
    USE SIGNAL ;
    PORT
      LAYER M4 ;
        RECT  0 18.096 0.192 18.12 ;
    END
  END di0[316]
  PIN di0[317]
    DIRECTION INPUT ;
    USE SIGNAL ;
    PORT
      LAYER M4 ;
        RECT  0 18.144 0.192 18.168 ;
    END
  END di0[317]
  PIN di0[318]
    DIRECTION INPUT ;
    USE SIGNAL ;
    PORT
      LAYER M4 ;
        RECT  0 18.192 0.192 18.216 ;
    END
  END di0[318]
  PIN di0[319]
    DIRECTION INPUT ;
    USE SIGNAL ;
    PORT
      LAYER M4 ;
        RECT  0 18.24 0.192 18.264 ;
    END
  END di0[319]
  PIN di0[31]
    DIRECTION INPUT ;
    USE SIGNAL ;
    PORT
      LAYER M4 ;
        RECT  0 4.416 0.192 4.44 ;
    END
  END di0[31]
  PIN di0[320]
    DIRECTION INPUT ;
    USE SIGNAL ;
    PORT
      LAYER M4 ;
        RECT  0 18.288 0.192 18.312 ;
    END
  END di0[320]
  PIN di0[321]
    DIRECTION INPUT ;
    USE SIGNAL ;
    PORT
      LAYER M4 ;
        RECT  0 18.336 0.192 18.36 ;
    END
  END di0[321]
  PIN di0[322]
    DIRECTION INPUT ;
    USE SIGNAL ;
    PORT
      LAYER M4 ;
        RECT  0 18.384 0.192 18.408 ;
    END
  END di0[322]
  PIN di0[323]
    DIRECTION INPUT ;
    USE SIGNAL ;
    PORT
      LAYER M4 ;
        RECT  0 18.432 0.192 18.456 ;
    END
  END di0[323]
  PIN di0[324]
    DIRECTION INPUT ;
    USE SIGNAL ;
    PORT
      LAYER M4 ;
        RECT  0 18.48 0.192 18.504 ;
    END
  END di0[324]
  PIN di0[325]
    DIRECTION INPUT ;
    USE SIGNAL ;
    PORT
      LAYER M4 ;
        RECT  0 18.528 0.192 18.552 ;
    END
  END di0[325]
  PIN di0[326]
    DIRECTION INPUT ;
    USE SIGNAL ;
    PORT
      LAYER M4 ;
        RECT  0 18.576 0.192 18.6 ;
    END
  END di0[326]
  PIN di0[327]
    DIRECTION INPUT ;
    USE SIGNAL ;
    PORT
      LAYER M4 ;
        RECT  0 18.624 0.192 18.648 ;
    END
  END di0[327]
  PIN di0[328]
    DIRECTION INPUT ;
    USE SIGNAL ;
    PORT
      LAYER M4 ;
        RECT  0 18.672 0.192 18.696 ;
    END
  END di0[328]
  PIN di0[329]
    DIRECTION INPUT ;
    USE SIGNAL ;
    PORT
      LAYER M4 ;
        RECT  0 18.72 0.192 18.744 ;
    END
  END di0[329]
  PIN di0[32]
    DIRECTION INPUT ;
    USE SIGNAL ;
    PORT
      LAYER M4 ;
        RECT  0 4.464 0.192 4.488 ;
    END
  END di0[32]
  PIN di0[330]
    DIRECTION INPUT ;
    USE SIGNAL ;
    PORT
      LAYER M4 ;
        RECT  0 18.768 0.192 18.792 ;
    END
  END di0[330]
  PIN di0[331]
    DIRECTION INPUT ;
    USE SIGNAL ;
    PORT
      LAYER M4 ;
        RECT  0 18.816 0.192 18.84 ;
    END
  END di0[331]
  PIN di0[332]
    DIRECTION INPUT ;
    USE SIGNAL ;
    PORT
      LAYER M4 ;
        RECT  0 18.864 0.192 18.888 ;
    END
  END di0[332]
  PIN di0[333]
    DIRECTION INPUT ;
    USE SIGNAL ;
    PORT
      LAYER M4 ;
        RECT  0 18.912 0.192 18.936 ;
    END
  END di0[333]
  PIN di0[334]
    DIRECTION INPUT ;
    USE SIGNAL ;
    PORT
      LAYER M4 ;
        RECT  0 18.96 0.192 18.984 ;
    END
  END di0[334]
  PIN di0[335]
    DIRECTION INPUT ;
    USE SIGNAL ;
    PORT
      LAYER M4 ;
        RECT  0 19.008 0.192 19.032 ;
    END
  END di0[335]
  PIN di0[336]
    DIRECTION INPUT ;
    USE SIGNAL ;
    PORT
      LAYER M4 ;
        RECT  0 19.056 0.192 19.08 ;
    END
  END di0[336]
  PIN di0[337]
    DIRECTION INPUT ;
    USE SIGNAL ;
    PORT
      LAYER M4 ;
        RECT  0 19.104 0.192 19.128 ;
    END
  END di0[337]
  PIN di0[338]
    DIRECTION INPUT ;
    USE SIGNAL ;
    PORT
      LAYER M4 ;
        RECT  0 19.152 0.192 19.176 ;
    END
  END di0[338]
  PIN di0[339]
    DIRECTION INPUT ;
    USE SIGNAL ;
    PORT
      LAYER M4 ;
        RECT  0 19.2 0.192 19.224 ;
    END
  END di0[339]
  PIN di0[33]
    DIRECTION INPUT ;
    USE SIGNAL ;
    PORT
      LAYER M4 ;
        RECT  0 4.512 0.192 4.536 ;
    END
  END di0[33]
  PIN di0[340]
    DIRECTION INPUT ;
    USE SIGNAL ;
    PORT
      LAYER M4 ;
        RECT  0 19.248 0.192 19.272 ;
    END
  END di0[340]
  PIN di0[341]
    DIRECTION INPUT ;
    USE SIGNAL ;
    PORT
      LAYER M4 ;
        RECT  0 19.296 0.192 19.32 ;
    END
  END di0[341]
  PIN di0[342]
    DIRECTION INPUT ;
    USE SIGNAL ;
    PORT
      LAYER M4 ;
        RECT  0 19.344 0.192 19.368 ;
    END
  END di0[342]
  PIN di0[343]
    DIRECTION INPUT ;
    USE SIGNAL ;
    PORT
      LAYER M4 ;
        RECT  0 19.392 0.192 19.416 ;
    END
  END di0[343]
  PIN di0[344]
    DIRECTION INPUT ;
    USE SIGNAL ;
    PORT
      LAYER M4 ;
        RECT  0 19.44 0.192 19.464 ;
    END
  END di0[344]
  PIN di0[345]
    DIRECTION INPUT ;
    USE SIGNAL ;
    PORT
      LAYER M4 ;
        RECT  0 19.488 0.192 19.512 ;
    END
  END di0[345]
  PIN di0[346]
    DIRECTION INPUT ;
    USE SIGNAL ;
    PORT
      LAYER M4 ;
        RECT  0 19.536 0.192 19.56 ;
    END
  END di0[346]
  PIN di0[347]
    DIRECTION INPUT ;
    USE SIGNAL ;
    PORT
      LAYER M4 ;
        RECT  0 19.584 0.192 19.608 ;
    END
  END di0[347]
  PIN di0[348]
    DIRECTION INPUT ;
    USE SIGNAL ;
    PORT
      LAYER M4 ;
        RECT  0 19.632 0.192 19.656 ;
    END
  END di0[348]
  PIN di0[349]
    DIRECTION INPUT ;
    USE SIGNAL ;
    PORT
      LAYER M4 ;
        RECT  0 19.68 0.192 19.704 ;
    END
  END di0[349]
  PIN di0[34]
    DIRECTION INPUT ;
    USE SIGNAL ;
    PORT
      LAYER M4 ;
        RECT  0 4.56 0.192 4.584 ;
    END
  END di0[34]
  PIN di0[350]
    DIRECTION INPUT ;
    USE SIGNAL ;
    PORT
      LAYER M4 ;
        RECT  0 19.728 0.192 19.752 ;
    END
  END di0[350]
  PIN di0[351]
    DIRECTION INPUT ;
    USE SIGNAL ;
    PORT
      LAYER M4 ;
        RECT  0 19.776 0.192 19.8 ;
    END
  END di0[351]
  PIN di0[352]
    DIRECTION INPUT ;
    USE SIGNAL ;
    PORT
      LAYER M4 ;
        RECT  0 19.824 0.192 19.848 ;
    END
  END di0[352]
  PIN di0[353]
    DIRECTION INPUT ;
    USE SIGNAL ;
    PORT
      LAYER M4 ;
        RECT  0 19.872 0.192 19.896 ;
    END
  END di0[353]
  PIN di0[354]
    DIRECTION INPUT ;
    USE SIGNAL ;
    PORT
      LAYER M4 ;
        RECT  0 19.92 0.192 19.944 ;
    END
  END di0[354]
  PIN di0[355]
    DIRECTION INPUT ;
    USE SIGNAL ;
    PORT
      LAYER M4 ;
        RECT  0 19.968 0.192 19.992 ;
    END
  END di0[355]
  PIN di0[356]
    DIRECTION INPUT ;
    USE SIGNAL ;
    PORT
      LAYER M4 ;
        RECT  0 20.016 0.192 20.04 ;
    END
  END di0[356]
  PIN di0[357]
    DIRECTION INPUT ;
    USE SIGNAL ;
    PORT
      LAYER M4 ;
        RECT  0 20.064 0.192 20.088 ;
    END
  END di0[357]
  PIN di0[358]
    DIRECTION INPUT ;
    USE SIGNAL ;
    PORT
      LAYER M4 ;
        RECT  0 20.112 0.192 20.136 ;
    END
  END di0[358]
  PIN di0[359]
    DIRECTION INPUT ;
    USE SIGNAL ;
    PORT
      LAYER M4 ;
        RECT  0 20.16 0.192 20.184 ;
    END
  END di0[359]
  PIN di0[35]
    DIRECTION INPUT ;
    USE SIGNAL ;
    PORT
      LAYER M4 ;
        RECT  0 4.608 0.192 4.632 ;
    END
  END di0[35]
  PIN di0[360]
    DIRECTION INPUT ;
    USE SIGNAL ;
    PORT
      LAYER M4 ;
        RECT  0 20.208 0.192 20.232 ;
    END
  END di0[360]
  PIN di0[361]
    DIRECTION INPUT ;
    USE SIGNAL ;
    PORT
      LAYER M4 ;
        RECT  0 20.256 0.192 20.28 ;
    END
  END di0[361]
  PIN di0[362]
    DIRECTION INPUT ;
    USE SIGNAL ;
    PORT
      LAYER M4 ;
        RECT  0 20.304 0.192 20.328 ;
    END
  END di0[362]
  PIN di0[363]
    DIRECTION INPUT ;
    USE SIGNAL ;
    PORT
      LAYER M4 ;
        RECT  0 20.352 0.192 20.376 ;
    END
  END di0[363]
  PIN di0[364]
    DIRECTION INPUT ;
    USE SIGNAL ;
    PORT
      LAYER M4 ;
        RECT  0 20.4 0.192 20.424 ;
    END
  END di0[364]
  PIN di0[365]
    DIRECTION INPUT ;
    USE SIGNAL ;
    PORT
      LAYER M4 ;
        RECT  0 20.448 0.192 20.472 ;
    END
  END di0[365]
  PIN di0[366]
    DIRECTION INPUT ;
    USE SIGNAL ;
    PORT
      LAYER M4 ;
        RECT  0 20.496 0.192 20.52 ;
    END
  END di0[366]
  PIN di0[367]
    DIRECTION INPUT ;
    USE SIGNAL ;
    PORT
      LAYER M4 ;
        RECT  0 20.544 0.192 20.568 ;
    END
  END di0[367]
  PIN di0[368]
    DIRECTION INPUT ;
    USE SIGNAL ;
    PORT
      LAYER M4 ;
        RECT  0 20.592 0.192 20.616 ;
    END
  END di0[368]
  PIN di0[369]
    DIRECTION INPUT ;
    USE SIGNAL ;
    PORT
      LAYER M4 ;
        RECT  0 20.64 0.192 20.664 ;
    END
  END di0[369]
  PIN di0[36]
    DIRECTION INPUT ;
    USE SIGNAL ;
    PORT
      LAYER M4 ;
        RECT  0 4.656 0.192 4.68 ;
    END
  END di0[36]
  PIN di0[370]
    DIRECTION INPUT ;
    USE SIGNAL ;
    PORT
      LAYER M4 ;
        RECT  0 20.688 0.192 20.712 ;
    END
  END di0[370]
  PIN di0[371]
    DIRECTION INPUT ;
    USE SIGNAL ;
    PORT
      LAYER M4 ;
        RECT  0 20.736 0.192 20.76 ;
    END
  END di0[371]
  PIN di0[372]
    DIRECTION INPUT ;
    USE SIGNAL ;
    PORT
      LAYER M4 ;
        RECT  0 20.784 0.192 20.808 ;
    END
  END di0[372]
  PIN di0[373]
    DIRECTION INPUT ;
    USE SIGNAL ;
    PORT
      LAYER M4 ;
        RECT  0 20.832 0.192 20.856 ;
    END
  END di0[373]
  PIN di0[374]
    DIRECTION INPUT ;
    USE SIGNAL ;
    PORT
      LAYER M4 ;
        RECT  0 20.88 0.192 20.904 ;
    END
  END di0[374]
  PIN di0[375]
    DIRECTION INPUT ;
    USE SIGNAL ;
    PORT
      LAYER M4 ;
        RECT  0 20.928 0.192 20.952 ;
    END
  END di0[375]
  PIN di0[376]
    DIRECTION INPUT ;
    USE SIGNAL ;
    PORT
      LAYER M4 ;
        RECT  0 20.976 0.192 21 ;
    END
  END di0[376]
  PIN di0[377]
    DIRECTION INPUT ;
    USE SIGNAL ;
    PORT
      LAYER M4 ;
        RECT  0 21.024 0.192 21.048 ;
    END
  END di0[377]
  PIN di0[378]
    DIRECTION INPUT ;
    USE SIGNAL ;
    PORT
      LAYER M4 ;
        RECT  0 21.072 0.192 21.096 ;
    END
  END di0[378]
  PIN di0[379]
    DIRECTION INPUT ;
    USE SIGNAL ;
    PORT
      LAYER M4 ;
        RECT  0 21.12 0.192 21.144 ;
    END
  END di0[379]
  PIN di0[37]
    DIRECTION INPUT ;
    USE SIGNAL ;
    PORT
      LAYER M4 ;
        RECT  0 4.704 0.192 4.728 ;
    END
  END di0[37]
  PIN di0[380]
    DIRECTION INPUT ;
    USE SIGNAL ;
    PORT
      LAYER M4 ;
        RECT  0 21.168 0.192 21.192 ;
    END
  END di0[380]
  PIN di0[381]
    DIRECTION INPUT ;
    USE SIGNAL ;
    PORT
      LAYER M4 ;
        RECT  0 21.216 0.192 21.24 ;
    END
  END di0[381]
  PIN di0[382]
    DIRECTION INPUT ;
    USE SIGNAL ;
    PORT
      LAYER M4 ;
        RECT  0 21.264 0.192 21.288 ;
    END
  END di0[382]
  PIN di0[383]
    DIRECTION INPUT ;
    USE SIGNAL ;
    PORT
      LAYER M4 ;
        RECT  0 21.312 0.192 21.336 ;
    END
  END di0[383]
  PIN di0[384]
    DIRECTION INPUT ;
    USE SIGNAL ;
    PORT
      LAYER M4 ;
        RECT  0 21.36 0.192 21.384 ;
    END
  END di0[384]
  PIN di0[385]
    DIRECTION INPUT ;
    USE SIGNAL ;
    PORT
      LAYER M4 ;
        RECT  0 21.408 0.192 21.432 ;
    END
  END di0[385]
  PIN di0[386]
    DIRECTION INPUT ;
    USE SIGNAL ;
    PORT
      LAYER M4 ;
        RECT  0 21.456 0.192 21.48 ;
    END
  END di0[386]
  PIN di0[387]
    DIRECTION INPUT ;
    USE SIGNAL ;
    PORT
      LAYER M4 ;
        RECT  0 21.504 0.192 21.528 ;
    END
  END di0[387]
  PIN di0[388]
    DIRECTION INPUT ;
    USE SIGNAL ;
    PORT
      LAYER M4 ;
        RECT  0 21.552 0.192 21.576 ;
    END
  END di0[388]
  PIN di0[389]
    DIRECTION INPUT ;
    USE SIGNAL ;
    PORT
      LAYER M4 ;
        RECT  0 21.6 0.192 21.624 ;
    END
  END di0[389]
  PIN di0[38]
    DIRECTION INPUT ;
    USE SIGNAL ;
    PORT
      LAYER M4 ;
        RECT  0 4.752 0.192 4.776 ;
    END
  END di0[38]
  PIN di0[390]
    DIRECTION INPUT ;
    USE SIGNAL ;
    PORT
      LAYER M4 ;
        RECT  0 21.648 0.192 21.672 ;
    END
  END di0[390]
  PIN di0[391]
    DIRECTION INPUT ;
    USE SIGNAL ;
    PORT
      LAYER M4 ;
        RECT  0 21.696 0.192 21.72 ;
    END
  END di0[391]
  PIN di0[392]
    DIRECTION INPUT ;
    USE SIGNAL ;
    PORT
      LAYER M4 ;
        RECT  0 21.744 0.192 21.768 ;
    END
  END di0[392]
  PIN di0[393]
    DIRECTION INPUT ;
    USE SIGNAL ;
    PORT
      LAYER M4 ;
        RECT  0 21.792 0.192 21.816 ;
    END
  END di0[393]
  PIN di0[394]
    DIRECTION INPUT ;
    USE SIGNAL ;
    PORT
      LAYER M4 ;
        RECT  0 21.84 0.192 21.864 ;
    END
  END di0[394]
  PIN di0[395]
    DIRECTION INPUT ;
    USE SIGNAL ;
    PORT
      LAYER M4 ;
        RECT  0 21.888 0.192 21.912 ;
    END
  END di0[395]
  PIN di0[396]
    DIRECTION INPUT ;
    USE SIGNAL ;
    PORT
      LAYER M4 ;
        RECT  0 21.936 0.192 21.96 ;
    END
  END di0[396]
  PIN di0[397]
    DIRECTION INPUT ;
    USE SIGNAL ;
    PORT
      LAYER M4 ;
        RECT  0 21.984 0.192 22.008 ;
    END
  END di0[397]
  PIN di0[398]
    DIRECTION INPUT ;
    USE SIGNAL ;
    PORT
      LAYER M4 ;
        RECT  0 22.032 0.192 22.056 ;
    END
  END di0[398]
  PIN di0[399]
    DIRECTION INPUT ;
    USE SIGNAL ;
    PORT
      LAYER M4 ;
        RECT  0 22.08 0.192 22.104 ;
    END
  END di0[399]
  PIN di0[39]
    DIRECTION INPUT ;
    USE SIGNAL ;
    PORT
      LAYER M4 ;
        RECT  0 4.8 0.192 4.824 ;
    END
  END di0[39]
  PIN di0[3]
    DIRECTION INPUT ;
    USE SIGNAL ;
    PORT
      LAYER M4 ;
        RECT  0 3.072 0.192 3.096 ;
    END
  END di0[3]
  PIN di0[400]
    DIRECTION INPUT ;
    USE SIGNAL ;
    PORT
      LAYER M4 ;
        RECT  0 22.128 0.192 22.152 ;
    END
  END di0[400]
  PIN di0[401]
    DIRECTION INPUT ;
    USE SIGNAL ;
    PORT
      LAYER M4 ;
        RECT  0 22.176 0.192 22.2 ;
    END
  END di0[401]
  PIN di0[402]
    DIRECTION INPUT ;
    USE SIGNAL ;
    PORT
      LAYER M4 ;
        RECT  0 22.224 0.192 22.248 ;
    END
  END di0[402]
  PIN di0[403]
    DIRECTION INPUT ;
    USE SIGNAL ;
    PORT
      LAYER M4 ;
        RECT  0 22.272 0.192 22.296 ;
    END
  END di0[403]
  PIN di0[404]
    DIRECTION INPUT ;
    USE SIGNAL ;
    PORT
      LAYER M4 ;
        RECT  0 22.32 0.192 22.344 ;
    END
  END di0[404]
  PIN di0[405]
    DIRECTION INPUT ;
    USE SIGNAL ;
    PORT
      LAYER M4 ;
        RECT  0 22.368 0.192 22.392 ;
    END
  END di0[405]
  PIN di0[406]
    DIRECTION INPUT ;
    USE SIGNAL ;
    PORT
      LAYER M4 ;
        RECT  0 22.416 0.192 22.44 ;
    END
  END di0[406]
  PIN di0[407]
    DIRECTION INPUT ;
    USE SIGNAL ;
    PORT
      LAYER M4 ;
        RECT  0 22.464 0.192 22.488 ;
    END
  END di0[407]
  PIN di0[408]
    DIRECTION INPUT ;
    USE SIGNAL ;
    PORT
      LAYER M4 ;
        RECT  0 22.512 0.192 22.536 ;
    END
  END di0[408]
  PIN di0[409]
    DIRECTION INPUT ;
    USE SIGNAL ;
    PORT
      LAYER M4 ;
        RECT  0 22.56 0.192 22.584 ;
    END
  END di0[409]
  PIN di0[40]
    DIRECTION INPUT ;
    USE SIGNAL ;
    PORT
      LAYER M4 ;
        RECT  0 4.848 0.192 4.872 ;
    END
  END di0[40]
  PIN di0[410]
    DIRECTION INPUT ;
    USE SIGNAL ;
    PORT
      LAYER M4 ;
        RECT  0 22.608 0.192 22.632 ;
    END
  END di0[410]
  PIN di0[411]
    DIRECTION INPUT ;
    USE SIGNAL ;
    PORT
      LAYER M4 ;
        RECT  0 22.656 0.192 22.68 ;
    END
  END di0[411]
  PIN di0[412]
    DIRECTION INPUT ;
    USE SIGNAL ;
    PORT
      LAYER M4 ;
        RECT  0 22.704 0.192 22.728 ;
    END
  END di0[412]
  PIN di0[413]
    DIRECTION INPUT ;
    USE SIGNAL ;
    PORT
      LAYER M4 ;
        RECT  0 22.752 0.192 22.776 ;
    END
  END di0[413]
  PIN di0[414]
    DIRECTION INPUT ;
    USE SIGNAL ;
    PORT
      LAYER M4 ;
        RECT  0 22.8 0.192 22.824 ;
    END
  END di0[414]
  PIN di0[415]
    DIRECTION INPUT ;
    USE SIGNAL ;
    PORT
      LAYER M4 ;
        RECT  0 22.848 0.192 22.872 ;
    END
  END di0[415]
  PIN di0[416]
    DIRECTION INPUT ;
    USE SIGNAL ;
    PORT
      LAYER M4 ;
        RECT  0 22.896 0.192 22.92 ;
    END
  END di0[416]
  PIN di0[417]
    DIRECTION INPUT ;
    USE SIGNAL ;
    PORT
      LAYER M4 ;
        RECT  0 22.944 0.192 22.968 ;
    END
  END di0[417]
  PIN di0[418]
    DIRECTION INPUT ;
    USE SIGNAL ;
    PORT
      LAYER M4 ;
        RECT  0 22.992 0.192 23.016 ;
    END
  END di0[418]
  PIN di0[419]
    DIRECTION INPUT ;
    USE SIGNAL ;
    PORT
      LAYER M4 ;
        RECT  0 23.04 0.192 23.064 ;
    END
  END di0[419]
  PIN di0[41]
    DIRECTION INPUT ;
    USE SIGNAL ;
    PORT
      LAYER M4 ;
        RECT  0 4.896 0.192 4.92 ;
    END
  END di0[41]
  PIN di0[420]
    DIRECTION INPUT ;
    USE SIGNAL ;
    PORT
      LAYER M4 ;
        RECT  0 23.088 0.192 23.112 ;
    END
  END di0[420]
  PIN di0[421]
    DIRECTION INPUT ;
    USE SIGNAL ;
    PORT
      LAYER M4 ;
        RECT  0 23.136 0.192 23.16 ;
    END
  END di0[421]
  PIN di0[422]
    DIRECTION INPUT ;
    USE SIGNAL ;
    PORT
      LAYER M4 ;
        RECT  0 23.184 0.192 23.208 ;
    END
  END di0[422]
  PIN di0[423]
    DIRECTION INPUT ;
    USE SIGNAL ;
    PORT
      LAYER M4 ;
        RECT  0 23.232 0.192 23.256 ;
    END
  END di0[423]
  PIN di0[424]
    DIRECTION INPUT ;
    USE SIGNAL ;
    PORT
      LAYER M4 ;
        RECT  0 23.28 0.192 23.304 ;
    END
  END di0[424]
  PIN di0[425]
    DIRECTION INPUT ;
    USE SIGNAL ;
    PORT
      LAYER M4 ;
        RECT  0 23.328 0.192 23.352 ;
    END
  END di0[425]
  PIN di0[426]
    DIRECTION INPUT ;
    USE SIGNAL ;
    PORT
      LAYER M4 ;
        RECT  0 23.376 0.192 23.4 ;
    END
  END di0[426]
  PIN di0[427]
    DIRECTION INPUT ;
    USE SIGNAL ;
    PORT
      LAYER M4 ;
        RECT  0 23.424 0.192 23.448 ;
    END
  END di0[427]
  PIN di0[428]
    DIRECTION INPUT ;
    USE SIGNAL ;
    PORT
      LAYER M4 ;
        RECT  0 23.472 0.192 23.496 ;
    END
  END di0[428]
  PIN di0[429]
    DIRECTION INPUT ;
    USE SIGNAL ;
    PORT
      LAYER M4 ;
        RECT  0 23.52 0.192 23.544 ;
    END
  END di0[429]
  PIN di0[42]
    DIRECTION INPUT ;
    USE SIGNAL ;
    PORT
      LAYER M4 ;
        RECT  0 4.944 0.192 4.968 ;
    END
  END di0[42]
  PIN di0[430]
    DIRECTION INPUT ;
    USE SIGNAL ;
    PORT
      LAYER M4 ;
        RECT  0 23.568 0.192 23.592 ;
    END
  END di0[430]
  PIN di0[431]
    DIRECTION INPUT ;
    USE SIGNAL ;
    PORT
      LAYER M4 ;
        RECT  0 23.616 0.192 23.64 ;
    END
  END di0[431]
  PIN di0[432]
    DIRECTION INPUT ;
    USE SIGNAL ;
    PORT
      LAYER M4 ;
        RECT  0 23.664 0.192 23.688 ;
    END
  END di0[432]
  PIN di0[433]
    DIRECTION INPUT ;
    USE SIGNAL ;
    PORT
      LAYER M4 ;
        RECT  0 23.712 0.192 23.736 ;
    END
  END di0[433]
  PIN di0[434]
    DIRECTION INPUT ;
    USE SIGNAL ;
    PORT
      LAYER M4 ;
        RECT  0 23.76 0.192 23.784 ;
    END
  END di0[434]
  PIN di0[435]
    DIRECTION INPUT ;
    USE SIGNAL ;
    PORT
      LAYER M4 ;
        RECT  0 23.808 0.192 23.832 ;
    END
  END di0[435]
  PIN di0[436]
    DIRECTION INPUT ;
    USE SIGNAL ;
    PORT
      LAYER M4 ;
        RECT  0 23.856 0.192 23.88 ;
    END
  END di0[436]
  PIN di0[437]
    DIRECTION INPUT ;
    USE SIGNAL ;
    PORT
      LAYER M4 ;
        RECT  0 23.904 0.192 23.928 ;
    END
  END di0[437]
  PIN di0[438]
    DIRECTION INPUT ;
    USE SIGNAL ;
    PORT
      LAYER M4 ;
        RECT  0 23.952 0.192 23.976 ;
    END
  END di0[438]
  PIN di0[439]
    DIRECTION INPUT ;
    USE SIGNAL ;
    PORT
      LAYER M4 ;
        RECT  0 24 0.192 24.024 ;
    END
  END di0[439]
  PIN di0[43]
    DIRECTION INPUT ;
    USE SIGNAL ;
    PORT
      LAYER M4 ;
        RECT  0 4.992 0.192 5.016 ;
    END
  END di0[43]
  PIN di0[440]
    DIRECTION INPUT ;
    USE SIGNAL ;
    PORT
      LAYER M4 ;
        RECT  0 24.048 0.192 24.072 ;
    END
  END di0[440]
  PIN di0[441]
    DIRECTION INPUT ;
    USE SIGNAL ;
    PORT
      LAYER M4 ;
        RECT  0 24.096 0.192 24.12 ;
    END
  END di0[441]
  PIN di0[442]
    DIRECTION INPUT ;
    USE SIGNAL ;
    PORT
      LAYER M4 ;
        RECT  0 24.144 0.192 24.168 ;
    END
  END di0[442]
  PIN di0[443]
    DIRECTION INPUT ;
    USE SIGNAL ;
    PORT
      LAYER M4 ;
        RECT  0 24.192 0.192 24.216 ;
    END
  END di0[443]
  PIN di0[444]
    DIRECTION INPUT ;
    USE SIGNAL ;
    PORT
      LAYER M4 ;
        RECT  0 24.24 0.192 24.264 ;
    END
  END di0[444]
  PIN di0[445]
    DIRECTION INPUT ;
    USE SIGNAL ;
    PORT
      LAYER M4 ;
        RECT  0 24.288 0.192 24.312 ;
    END
  END di0[445]
  PIN di0[446]
    DIRECTION INPUT ;
    USE SIGNAL ;
    PORT
      LAYER M4 ;
        RECT  0 24.336 0.192 24.36 ;
    END
  END di0[446]
  PIN di0[447]
    DIRECTION INPUT ;
    USE SIGNAL ;
    PORT
      LAYER M4 ;
        RECT  0 24.384 0.192 24.408 ;
    END
  END di0[447]
  PIN di0[448]
    DIRECTION INPUT ;
    USE SIGNAL ;
    PORT
      LAYER M4 ;
        RECT  0 24.432 0.192 24.456 ;
    END
  END di0[448]
  PIN di0[449]
    DIRECTION INPUT ;
    USE SIGNAL ;
    PORT
      LAYER M4 ;
        RECT  0 24.48 0.192 24.504 ;
    END
  END di0[449]
  PIN di0[44]
    DIRECTION INPUT ;
    USE SIGNAL ;
    PORT
      LAYER M4 ;
        RECT  0 5.04 0.192 5.064 ;
    END
  END di0[44]
  PIN di0[450]
    DIRECTION INPUT ;
    USE SIGNAL ;
    PORT
      LAYER M4 ;
        RECT  0 24.528 0.192 24.552 ;
    END
  END di0[450]
  PIN di0[451]
    DIRECTION INPUT ;
    USE SIGNAL ;
    PORT
      LAYER M4 ;
        RECT  0 24.576 0.192 24.6 ;
    END
  END di0[451]
  PIN di0[452]
    DIRECTION INPUT ;
    USE SIGNAL ;
    PORT
      LAYER M4 ;
        RECT  0 24.624 0.192 24.648 ;
    END
  END di0[452]
  PIN di0[453]
    DIRECTION INPUT ;
    USE SIGNAL ;
    PORT
      LAYER M4 ;
        RECT  0 24.672 0.192 24.696 ;
    END
  END di0[453]
  PIN di0[454]
    DIRECTION INPUT ;
    USE SIGNAL ;
    PORT
      LAYER M4 ;
        RECT  0 24.72 0.192 24.744 ;
    END
  END di0[454]
  PIN di0[455]
    DIRECTION INPUT ;
    USE SIGNAL ;
    PORT
      LAYER M4 ;
        RECT  0 24.768 0.192 24.792 ;
    END
  END di0[455]
  PIN di0[456]
    DIRECTION INPUT ;
    USE SIGNAL ;
    PORT
      LAYER M4 ;
        RECT  0 24.816 0.192 24.84 ;
    END
  END di0[456]
  PIN di0[457]
    DIRECTION INPUT ;
    USE SIGNAL ;
    PORT
      LAYER M4 ;
        RECT  0 24.864 0.192 24.888 ;
    END
  END di0[457]
  PIN di0[458]
    DIRECTION INPUT ;
    USE SIGNAL ;
    PORT
      LAYER M4 ;
        RECT  0 24.912 0.192 24.936 ;
    END
  END di0[458]
  PIN di0[459]
    DIRECTION INPUT ;
    USE SIGNAL ;
    PORT
      LAYER M4 ;
        RECT  0 24.96 0.192 24.984 ;
    END
  END di0[459]
  PIN di0[45]
    DIRECTION INPUT ;
    USE SIGNAL ;
    PORT
      LAYER M4 ;
        RECT  0 5.088 0.192 5.112 ;
    END
  END di0[45]
  PIN di0[460]
    DIRECTION INPUT ;
    USE SIGNAL ;
    PORT
      LAYER M4 ;
        RECT  0 25.008 0.192 25.032 ;
    END
  END di0[460]
  PIN di0[461]
    DIRECTION INPUT ;
    USE SIGNAL ;
    PORT
      LAYER M4 ;
        RECT  0 25.056 0.192 25.08 ;
    END
  END di0[461]
  PIN di0[462]
    DIRECTION INPUT ;
    USE SIGNAL ;
    PORT
      LAYER M4 ;
        RECT  0 25.104 0.192 25.128 ;
    END
  END di0[462]
  PIN di0[463]
    DIRECTION INPUT ;
    USE SIGNAL ;
    PORT
      LAYER M4 ;
        RECT  0 25.152 0.192 25.176 ;
    END
  END di0[463]
  PIN di0[464]
    DIRECTION INPUT ;
    USE SIGNAL ;
    PORT
      LAYER M4 ;
        RECT  0 25.2 0.192 25.224 ;
    END
  END di0[464]
  PIN di0[465]
    DIRECTION INPUT ;
    USE SIGNAL ;
    PORT
      LAYER M4 ;
        RECT  0 25.248 0.192 25.272 ;
    END
  END di0[465]
  PIN di0[466]
    DIRECTION INPUT ;
    USE SIGNAL ;
    PORT
      LAYER M4 ;
        RECT  0 25.296 0.192 25.32 ;
    END
  END di0[466]
  PIN di0[467]
    DIRECTION INPUT ;
    USE SIGNAL ;
    PORT
      LAYER M4 ;
        RECT  0 25.344 0.192 25.368 ;
    END
  END di0[467]
  PIN di0[468]
    DIRECTION INPUT ;
    USE SIGNAL ;
    PORT
      LAYER M4 ;
        RECT  0 25.392 0.192 25.416 ;
    END
  END di0[468]
  PIN di0[469]
    DIRECTION INPUT ;
    USE SIGNAL ;
    PORT
      LAYER M4 ;
        RECT  0 25.44 0.192 25.464 ;
    END
  END di0[469]
  PIN di0[46]
    DIRECTION INPUT ;
    USE SIGNAL ;
    PORT
      LAYER M4 ;
        RECT  0 5.136 0.192 5.16 ;
    END
  END di0[46]
  PIN di0[470]
    DIRECTION INPUT ;
    USE SIGNAL ;
    PORT
      LAYER M4 ;
        RECT  0 25.488 0.192 25.512 ;
    END
  END di0[470]
  PIN di0[471]
    DIRECTION INPUT ;
    USE SIGNAL ;
    PORT
      LAYER M4 ;
        RECT  0 25.536 0.192 25.56 ;
    END
  END di0[471]
  PIN di0[472]
    DIRECTION INPUT ;
    USE SIGNAL ;
    PORT
      LAYER M4 ;
        RECT  0 25.584 0.192 25.608 ;
    END
  END di0[472]
  PIN di0[473]
    DIRECTION INPUT ;
    USE SIGNAL ;
    PORT
      LAYER M4 ;
        RECT  0 25.632 0.192 25.656 ;
    END
  END di0[473]
  PIN di0[474]
    DIRECTION INPUT ;
    USE SIGNAL ;
    PORT
      LAYER M4 ;
        RECT  0 25.68 0.192 25.704 ;
    END
  END di0[474]
  PIN di0[475]
    DIRECTION INPUT ;
    USE SIGNAL ;
    PORT
      LAYER M4 ;
        RECT  0 25.728 0.192 25.752 ;
    END
  END di0[475]
  PIN di0[476]
    DIRECTION INPUT ;
    USE SIGNAL ;
    PORT
      LAYER M4 ;
        RECT  0 25.776 0.192 25.8 ;
    END
  END di0[476]
  PIN di0[477]
    DIRECTION INPUT ;
    USE SIGNAL ;
    PORT
      LAYER M4 ;
        RECT  0 25.824 0.192 25.848 ;
    END
  END di0[477]
  PIN di0[478]
    DIRECTION INPUT ;
    USE SIGNAL ;
    PORT
      LAYER M4 ;
        RECT  0 25.872 0.192 25.896 ;
    END
  END di0[478]
  PIN di0[479]
    DIRECTION INPUT ;
    USE SIGNAL ;
    PORT
      LAYER M4 ;
        RECT  0 25.92 0.192 25.944 ;
    END
  END di0[479]
  PIN di0[47]
    DIRECTION INPUT ;
    USE SIGNAL ;
    PORT
      LAYER M4 ;
        RECT  0 5.184 0.192 5.208 ;
    END
  END di0[47]
  PIN di0[480]
    DIRECTION INPUT ;
    USE SIGNAL ;
    PORT
      LAYER M4 ;
        RECT  0 25.968 0.192 25.992 ;
    END
  END di0[480]
  PIN di0[481]
    DIRECTION INPUT ;
    USE SIGNAL ;
    PORT
      LAYER M4 ;
        RECT  0 26.016 0.192 26.04 ;
    END
  END di0[481]
  PIN di0[482]
    DIRECTION INPUT ;
    USE SIGNAL ;
    PORT
      LAYER M4 ;
        RECT  0 26.064 0.192 26.088 ;
    END
  END di0[482]
  PIN di0[483]
    DIRECTION INPUT ;
    USE SIGNAL ;
    PORT
      LAYER M4 ;
        RECT  0 26.112 0.192 26.136 ;
    END
  END di0[483]
  PIN di0[484]
    DIRECTION INPUT ;
    USE SIGNAL ;
    PORT
      LAYER M4 ;
        RECT  0 26.16 0.192 26.184 ;
    END
  END di0[484]
  PIN di0[485]
    DIRECTION INPUT ;
    USE SIGNAL ;
    PORT
      LAYER M4 ;
        RECT  0 26.208 0.192 26.232 ;
    END
  END di0[485]
  PIN di0[486]
    DIRECTION INPUT ;
    USE SIGNAL ;
    PORT
      LAYER M4 ;
        RECT  0 26.256 0.192 26.28 ;
    END
  END di0[486]
  PIN di0[487]
    DIRECTION INPUT ;
    USE SIGNAL ;
    PORT
      LAYER M4 ;
        RECT  0 26.304 0.192 26.328 ;
    END
  END di0[487]
  PIN di0[488]
    DIRECTION INPUT ;
    USE SIGNAL ;
    PORT
      LAYER M4 ;
        RECT  0 26.352 0.192 26.376 ;
    END
  END di0[488]
  PIN di0[489]
    DIRECTION INPUT ;
    USE SIGNAL ;
    PORT
      LAYER M4 ;
        RECT  0 26.4 0.192 26.424 ;
    END
  END di0[489]
  PIN di0[48]
    DIRECTION INPUT ;
    USE SIGNAL ;
    PORT
      LAYER M4 ;
        RECT  0 5.232 0.192 5.256 ;
    END
  END di0[48]
  PIN di0[490]
    DIRECTION INPUT ;
    USE SIGNAL ;
    PORT
      LAYER M4 ;
        RECT  0 26.448 0.192 26.472 ;
    END
  END di0[490]
  PIN di0[491]
    DIRECTION INPUT ;
    USE SIGNAL ;
    PORT
      LAYER M4 ;
        RECT  0 26.496 0.192 26.52 ;
    END
  END di0[491]
  PIN di0[492]
    DIRECTION INPUT ;
    USE SIGNAL ;
    PORT
      LAYER M4 ;
        RECT  0 26.544 0.192 26.568 ;
    END
  END di0[492]
  PIN di0[493]
    DIRECTION INPUT ;
    USE SIGNAL ;
    PORT
      LAYER M4 ;
        RECT  0 26.592 0.192 26.616 ;
    END
  END di0[493]
  PIN di0[494]
    DIRECTION INPUT ;
    USE SIGNAL ;
    PORT
      LAYER M4 ;
        RECT  0 26.64 0.192 26.664 ;
    END
  END di0[494]
  PIN di0[495]
    DIRECTION INPUT ;
    USE SIGNAL ;
    PORT
      LAYER M4 ;
        RECT  0 26.688 0.192 26.712 ;
    END
  END di0[495]
  PIN di0[496]
    DIRECTION INPUT ;
    USE SIGNAL ;
    PORT
      LAYER M4 ;
        RECT  0 26.736 0.192 26.76 ;
    END
  END di0[496]
  PIN di0[497]
    DIRECTION INPUT ;
    USE SIGNAL ;
    PORT
      LAYER M4 ;
        RECT  0 26.784 0.192 26.808 ;
    END
  END di0[497]
  PIN di0[498]
    DIRECTION INPUT ;
    USE SIGNAL ;
    PORT
      LAYER M4 ;
        RECT  0 26.832 0.192 26.856 ;
    END
  END di0[498]
  PIN di0[499]
    DIRECTION INPUT ;
    USE SIGNAL ;
    PORT
      LAYER M4 ;
        RECT  0 26.88 0.192 26.904 ;
    END
  END di0[499]
  PIN di0[49]
    DIRECTION INPUT ;
    USE SIGNAL ;
    PORT
      LAYER M4 ;
        RECT  0 5.28 0.192 5.304 ;
    END
  END di0[49]
  PIN di0[4]
    DIRECTION INPUT ;
    USE SIGNAL ;
    PORT
      LAYER M4 ;
        RECT  0 3.12 0.192 3.144 ;
    END
  END di0[4]
  PIN di0[500]
    DIRECTION INPUT ;
    USE SIGNAL ;
    PORT
      LAYER M4 ;
        RECT  0 26.928 0.192 26.952 ;
    END
  END di0[500]
  PIN di0[501]
    DIRECTION INPUT ;
    USE SIGNAL ;
    PORT
      LAYER M4 ;
        RECT  0 26.976 0.192 27 ;
    END
  END di0[501]
  PIN di0[502]
    DIRECTION INPUT ;
    USE SIGNAL ;
    PORT
      LAYER M4 ;
        RECT  0 27.024 0.192 27.048 ;
    END
  END di0[502]
  PIN di0[503]
    DIRECTION INPUT ;
    USE SIGNAL ;
    PORT
      LAYER M4 ;
        RECT  0 27.072 0.192 27.096 ;
    END
  END di0[503]
  PIN di0[504]
    DIRECTION INPUT ;
    USE SIGNAL ;
    PORT
      LAYER M4 ;
        RECT  0 27.12 0.192 27.144 ;
    END
  END di0[504]
  PIN di0[505]
    DIRECTION INPUT ;
    USE SIGNAL ;
    PORT
      LAYER M4 ;
        RECT  0 27.168 0.192 27.192 ;
    END
  END di0[505]
  PIN di0[506]
    DIRECTION INPUT ;
    USE SIGNAL ;
    PORT
      LAYER M4 ;
        RECT  0 27.216 0.192 27.24 ;
    END
  END di0[506]
  PIN di0[507]
    DIRECTION INPUT ;
    USE SIGNAL ;
    PORT
      LAYER M4 ;
        RECT  0 27.264 0.192 27.288 ;
    END
  END di0[507]
  PIN di0[508]
    DIRECTION INPUT ;
    USE SIGNAL ;
    PORT
      LAYER M4 ;
        RECT  0 27.312 0.192 27.336 ;
    END
  END di0[508]
  PIN di0[509]
    DIRECTION INPUT ;
    USE SIGNAL ;
    PORT
      LAYER M4 ;
        RECT  0 27.36 0.192 27.384 ;
    END
  END di0[509]
  PIN di0[50]
    DIRECTION INPUT ;
    USE SIGNAL ;
    PORT
      LAYER M4 ;
        RECT  0 5.328 0.192 5.352 ;
    END
  END di0[50]
  PIN di0[510]
    DIRECTION INPUT ;
    USE SIGNAL ;
    PORT
      LAYER M4 ;
        RECT  0 27.408 0.192 27.432 ;
    END
  END di0[510]
  PIN di0[511]
    DIRECTION INPUT ;
    USE SIGNAL ;
    PORT
      LAYER M4 ;
        RECT  0 27.456 0.192 27.48 ;
    END
  END di0[511]
  PIN di0[51]
    DIRECTION INPUT ;
    USE SIGNAL ;
    PORT
      LAYER M4 ;
        RECT  0 5.376 0.192 5.4 ;
    END
  END di0[51]
  PIN di0[52]
    DIRECTION INPUT ;
    USE SIGNAL ;
    PORT
      LAYER M4 ;
        RECT  0 5.424 0.192 5.448 ;
    END
  END di0[52]
  PIN di0[53]
    DIRECTION INPUT ;
    USE SIGNAL ;
    PORT
      LAYER M4 ;
        RECT  0 5.472 0.192 5.496 ;
    END
  END di0[53]
  PIN di0[54]
    DIRECTION INPUT ;
    USE SIGNAL ;
    PORT
      LAYER M4 ;
        RECT  0 5.52 0.192 5.544 ;
    END
  END di0[54]
  PIN di0[55]
    DIRECTION INPUT ;
    USE SIGNAL ;
    PORT
      LAYER M4 ;
        RECT  0 5.568 0.192 5.592 ;
    END
  END di0[55]
  PIN di0[56]
    DIRECTION INPUT ;
    USE SIGNAL ;
    PORT
      LAYER M4 ;
        RECT  0 5.616 0.192 5.64 ;
    END
  END di0[56]
  PIN di0[57]
    DIRECTION INPUT ;
    USE SIGNAL ;
    PORT
      LAYER M4 ;
        RECT  0 5.664 0.192 5.688 ;
    END
  END di0[57]
  PIN di0[58]
    DIRECTION INPUT ;
    USE SIGNAL ;
    PORT
      LAYER M4 ;
        RECT  0 5.712 0.192 5.736 ;
    END
  END di0[58]
  PIN di0[59]
    DIRECTION INPUT ;
    USE SIGNAL ;
    PORT
      LAYER M4 ;
        RECT  0 5.76 0.192 5.784 ;
    END
  END di0[59]
  PIN di0[5]
    DIRECTION INPUT ;
    USE SIGNAL ;
    PORT
      LAYER M4 ;
        RECT  0 3.168 0.192 3.192 ;
    END
  END di0[5]
  PIN di0[60]
    DIRECTION INPUT ;
    USE SIGNAL ;
    PORT
      LAYER M4 ;
        RECT  0 5.808 0.192 5.832 ;
    END
  END di0[60]
  PIN di0[61]
    DIRECTION INPUT ;
    USE SIGNAL ;
    PORT
      LAYER M4 ;
        RECT  0 5.856 0.192 5.88 ;
    END
  END di0[61]
  PIN di0[62]
    DIRECTION INPUT ;
    USE SIGNAL ;
    PORT
      LAYER M4 ;
        RECT  0 5.904 0.192 5.928 ;
    END
  END di0[62]
  PIN di0[63]
    DIRECTION INPUT ;
    USE SIGNAL ;
    PORT
      LAYER M4 ;
        RECT  0 5.952 0.192 5.976 ;
    END
  END di0[63]
  PIN di0[64]
    DIRECTION INPUT ;
    USE SIGNAL ;
    PORT
      LAYER M4 ;
        RECT  0 6 0.192 6.024 ;
    END
  END di0[64]
  PIN di0[65]
    DIRECTION INPUT ;
    USE SIGNAL ;
    PORT
      LAYER M4 ;
        RECT  0 6.048 0.192 6.072 ;
    END
  END di0[65]
  PIN di0[66]
    DIRECTION INPUT ;
    USE SIGNAL ;
    PORT
      LAYER M4 ;
        RECT  0 6.096 0.192 6.12 ;
    END
  END di0[66]
  PIN di0[67]
    DIRECTION INPUT ;
    USE SIGNAL ;
    PORT
      LAYER M4 ;
        RECT  0 6.144 0.192 6.168 ;
    END
  END di0[67]
  PIN di0[68]
    DIRECTION INPUT ;
    USE SIGNAL ;
    PORT
      LAYER M4 ;
        RECT  0 6.192 0.192 6.216 ;
    END
  END di0[68]
  PIN di0[69]
    DIRECTION INPUT ;
    USE SIGNAL ;
    PORT
      LAYER M4 ;
        RECT  0 6.24 0.192 6.264 ;
    END
  END di0[69]
  PIN di0[6]
    DIRECTION INPUT ;
    USE SIGNAL ;
    PORT
      LAYER M4 ;
        RECT  0 3.216 0.192 3.24 ;
    END
  END di0[6]
  PIN di0[70]
    DIRECTION INPUT ;
    USE SIGNAL ;
    PORT
      LAYER M4 ;
        RECT  0 6.288 0.192 6.312 ;
    END
  END di0[70]
  PIN di0[71]
    DIRECTION INPUT ;
    USE SIGNAL ;
    PORT
      LAYER M4 ;
        RECT  0 6.336 0.192 6.36 ;
    END
  END di0[71]
  PIN di0[72]
    DIRECTION INPUT ;
    USE SIGNAL ;
    PORT
      LAYER M4 ;
        RECT  0 6.384 0.192 6.408 ;
    END
  END di0[72]
  PIN di0[73]
    DIRECTION INPUT ;
    USE SIGNAL ;
    PORT
      LAYER M4 ;
        RECT  0 6.432 0.192 6.456 ;
    END
  END di0[73]
  PIN di0[74]
    DIRECTION INPUT ;
    USE SIGNAL ;
    PORT
      LAYER M4 ;
        RECT  0 6.48 0.192 6.504 ;
    END
  END di0[74]
  PIN di0[75]
    DIRECTION INPUT ;
    USE SIGNAL ;
    PORT
      LAYER M4 ;
        RECT  0 6.528 0.192 6.552 ;
    END
  END di0[75]
  PIN di0[76]
    DIRECTION INPUT ;
    USE SIGNAL ;
    PORT
      LAYER M4 ;
        RECT  0 6.576 0.192 6.6 ;
    END
  END di0[76]
  PIN di0[77]
    DIRECTION INPUT ;
    USE SIGNAL ;
    PORT
      LAYER M4 ;
        RECT  0 6.624 0.192 6.648 ;
    END
  END di0[77]
  PIN di0[78]
    DIRECTION INPUT ;
    USE SIGNAL ;
    PORT
      LAYER M4 ;
        RECT  0 6.672 0.192 6.696 ;
    END
  END di0[78]
  PIN di0[79]
    DIRECTION INPUT ;
    USE SIGNAL ;
    PORT
      LAYER M4 ;
        RECT  0 6.72 0.192 6.744 ;
    END
  END di0[79]
  PIN di0[7]
    DIRECTION INPUT ;
    USE SIGNAL ;
    PORT
      LAYER M4 ;
        RECT  0 3.264 0.192 3.288 ;
    END
  END di0[7]
  PIN di0[80]
    DIRECTION INPUT ;
    USE SIGNAL ;
    PORT
      LAYER M4 ;
        RECT  0 6.768 0.192 6.792 ;
    END
  END di0[80]
  PIN di0[81]
    DIRECTION INPUT ;
    USE SIGNAL ;
    PORT
      LAYER M4 ;
        RECT  0 6.816 0.192 6.84 ;
    END
  END di0[81]
  PIN di0[82]
    DIRECTION INPUT ;
    USE SIGNAL ;
    PORT
      LAYER M4 ;
        RECT  0 6.864 0.192 6.888 ;
    END
  END di0[82]
  PIN di0[83]
    DIRECTION INPUT ;
    USE SIGNAL ;
    PORT
      LAYER M4 ;
        RECT  0 6.912 0.192 6.936 ;
    END
  END di0[83]
  PIN di0[84]
    DIRECTION INPUT ;
    USE SIGNAL ;
    PORT
      LAYER M4 ;
        RECT  0 6.96 0.192 6.984 ;
    END
  END di0[84]
  PIN di0[85]
    DIRECTION INPUT ;
    USE SIGNAL ;
    PORT
      LAYER M4 ;
        RECT  0 7.008 0.192 7.032 ;
    END
  END di0[85]
  PIN di0[86]
    DIRECTION INPUT ;
    USE SIGNAL ;
    PORT
      LAYER M4 ;
        RECT  0 7.056 0.192 7.08 ;
    END
  END di0[86]
  PIN di0[87]
    DIRECTION INPUT ;
    USE SIGNAL ;
    PORT
      LAYER M4 ;
        RECT  0 7.104 0.192 7.128 ;
    END
  END di0[87]
  PIN di0[88]
    DIRECTION INPUT ;
    USE SIGNAL ;
    PORT
      LAYER M4 ;
        RECT  0 7.152 0.192 7.176 ;
    END
  END di0[88]
  PIN di0[89]
    DIRECTION INPUT ;
    USE SIGNAL ;
    PORT
      LAYER M4 ;
        RECT  0 7.2 0.192 7.224 ;
    END
  END di0[89]
  PIN di0[8]
    DIRECTION INPUT ;
    USE SIGNAL ;
    PORT
      LAYER M4 ;
        RECT  0 3.312 0.192 3.336 ;
    END
  END di0[8]
  PIN di0[90]
    DIRECTION INPUT ;
    USE SIGNAL ;
    PORT
      LAYER M4 ;
        RECT  0 7.248 0.192 7.272 ;
    END
  END di0[90]
  PIN di0[91]
    DIRECTION INPUT ;
    USE SIGNAL ;
    PORT
      LAYER M4 ;
        RECT  0 7.296 0.192 7.32 ;
    END
  END di0[91]
  PIN di0[92]
    DIRECTION INPUT ;
    USE SIGNAL ;
    PORT
      LAYER M4 ;
        RECT  0 7.344 0.192 7.368 ;
    END
  END di0[92]
  PIN di0[93]
    DIRECTION INPUT ;
    USE SIGNAL ;
    PORT
      LAYER M4 ;
        RECT  0 7.392 0.192 7.416 ;
    END
  END di0[93]
  PIN di0[94]
    DIRECTION INPUT ;
    USE SIGNAL ;
    PORT
      LAYER M4 ;
        RECT  0 7.44 0.192 7.464 ;
    END
  END di0[94]
  PIN di0[95]
    DIRECTION INPUT ;
    USE SIGNAL ;
    PORT
      LAYER M4 ;
        RECT  0 7.488 0.192 7.512 ;
    END
  END di0[95]
  PIN di0[96]
    DIRECTION INPUT ;
    USE SIGNAL ;
    PORT
      LAYER M4 ;
        RECT  0 7.536 0.192 7.56 ;
    END
  END di0[96]
  PIN di0[97]
    DIRECTION INPUT ;
    USE SIGNAL ;
    PORT
      LAYER M4 ;
        RECT  0 7.584 0.192 7.608 ;
    END
  END di0[97]
  PIN di0[98]
    DIRECTION INPUT ;
    USE SIGNAL ;
    PORT
      LAYER M4 ;
        RECT  0 7.632 0.192 7.656 ;
    END
  END di0[98]
  PIN di0[99]
    DIRECTION INPUT ;
    USE SIGNAL ;
    PORT
      LAYER M4 ;
        RECT  0 7.68 0.192 7.704 ;
    END
  END di0[99]
  PIN di0[9]
    DIRECTION INPUT ;
    USE SIGNAL ;
    PORT
      LAYER M4 ;
        RECT  0 3.36 0.192 3.384 ;
    END
  END di0[9]
  PIN do0[0]
    DIRECTION OUTPUT ;
    USE SIGNAL ;
    PORT
      LAYER M4 ;
        RECT  17.064 2.928 17.256 2.952 ;
    END
  END do0[0]
  PIN do0[100]
    DIRECTION OUTPUT ;
    USE SIGNAL ;
    PORT
      LAYER M4 ;
        RECT  17.064 7.728 17.256 7.752 ;
    END
  END do0[100]
  PIN do0[101]
    DIRECTION OUTPUT ;
    USE SIGNAL ;
    PORT
      LAYER M4 ;
        RECT  17.064 7.776 17.256 7.8 ;
    END
  END do0[101]
  PIN do0[102]
    DIRECTION OUTPUT ;
    USE SIGNAL ;
    PORT
      LAYER M4 ;
        RECT  17.064 7.824 17.256 7.848 ;
    END
  END do0[102]
  PIN do0[103]
    DIRECTION OUTPUT ;
    USE SIGNAL ;
    PORT
      LAYER M4 ;
        RECT  17.064 7.872 17.256 7.896 ;
    END
  END do0[103]
  PIN do0[104]
    DIRECTION OUTPUT ;
    USE SIGNAL ;
    PORT
      LAYER M4 ;
        RECT  17.064 7.92 17.256 7.944 ;
    END
  END do0[104]
  PIN do0[105]
    DIRECTION OUTPUT ;
    USE SIGNAL ;
    PORT
      LAYER M4 ;
        RECT  17.064 7.968 17.256 7.992 ;
    END
  END do0[105]
  PIN do0[106]
    DIRECTION OUTPUT ;
    USE SIGNAL ;
    PORT
      LAYER M4 ;
        RECT  17.064 8.016 17.256 8.04 ;
    END
  END do0[106]
  PIN do0[107]
    DIRECTION OUTPUT ;
    USE SIGNAL ;
    PORT
      LAYER M4 ;
        RECT  17.064 8.064 17.256 8.088 ;
    END
  END do0[107]
  PIN do0[108]
    DIRECTION OUTPUT ;
    USE SIGNAL ;
    PORT
      LAYER M4 ;
        RECT  17.064 8.112 17.256 8.136 ;
    END
  END do0[108]
  PIN do0[109]
    DIRECTION OUTPUT ;
    USE SIGNAL ;
    PORT
      LAYER M4 ;
        RECT  17.064 8.16 17.256 8.184 ;
    END
  END do0[109]
  PIN do0[10]
    DIRECTION OUTPUT ;
    USE SIGNAL ;
    PORT
      LAYER M4 ;
        RECT  17.064 3.408 17.256 3.432 ;
    END
  END do0[10]
  PIN do0[110]
    DIRECTION OUTPUT ;
    USE SIGNAL ;
    PORT
      LAYER M4 ;
        RECT  17.064 8.208 17.256 8.232 ;
    END
  END do0[110]
  PIN do0[111]
    DIRECTION OUTPUT ;
    USE SIGNAL ;
    PORT
      LAYER M4 ;
        RECT  17.064 8.256 17.256 8.28 ;
    END
  END do0[111]
  PIN do0[112]
    DIRECTION OUTPUT ;
    USE SIGNAL ;
    PORT
      LAYER M4 ;
        RECT  17.064 8.304 17.256 8.328 ;
    END
  END do0[112]
  PIN do0[113]
    DIRECTION OUTPUT ;
    USE SIGNAL ;
    PORT
      LAYER M4 ;
        RECT  17.064 8.352 17.256 8.376 ;
    END
  END do0[113]
  PIN do0[114]
    DIRECTION OUTPUT ;
    USE SIGNAL ;
    PORT
      LAYER M4 ;
        RECT  17.064 8.4 17.256 8.424 ;
    END
  END do0[114]
  PIN do0[115]
    DIRECTION OUTPUT ;
    USE SIGNAL ;
    PORT
      LAYER M4 ;
        RECT  17.064 8.448 17.256 8.472 ;
    END
  END do0[115]
  PIN do0[116]
    DIRECTION OUTPUT ;
    USE SIGNAL ;
    PORT
      LAYER M4 ;
        RECT  17.064 8.496 17.256 8.52 ;
    END
  END do0[116]
  PIN do0[117]
    DIRECTION OUTPUT ;
    USE SIGNAL ;
    PORT
      LAYER M4 ;
        RECT  17.064 8.544 17.256 8.568 ;
    END
  END do0[117]
  PIN do0[118]
    DIRECTION OUTPUT ;
    USE SIGNAL ;
    PORT
      LAYER M4 ;
        RECT  17.064 8.592 17.256 8.616 ;
    END
  END do0[118]
  PIN do0[119]
    DIRECTION OUTPUT ;
    USE SIGNAL ;
    PORT
      LAYER M4 ;
        RECT  17.064 8.64 17.256 8.664 ;
    END
  END do0[119]
  PIN do0[11]
    DIRECTION OUTPUT ;
    USE SIGNAL ;
    PORT
      LAYER M4 ;
        RECT  17.064 3.456 17.256 3.48 ;
    END
  END do0[11]
  PIN do0[120]
    DIRECTION OUTPUT ;
    USE SIGNAL ;
    PORT
      LAYER M4 ;
        RECT  17.064 8.688 17.256 8.712 ;
    END
  END do0[120]
  PIN do0[121]
    DIRECTION OUTPUT ;
    USE SIGNAL ;
    PORT
      LAYER M4 ;
        RECT  17.064 8.736 17.256 8.76 ;
    END
  END do0[121]
  PIN do0[122]
    DIRECTION OUTPUT ;
    USE SIGNAL ;
    PORT
      LAYER M4 ;
        RECT  17.064 8.784 17.256 8.808 ;
    END
  END do0[122]
  PIN do0[123]
    DIRECTION OUTPUT ;
    USE SIGNAL ;
    PORT
      LAYER M4 ;
        RECT  17.064 8.832 17.256 8.856 ;
    END
  END do0[123]
  PIN do0[124]
    DIRECTION OUTPUT ;
    USE SIGNAL ;
    PORT
      LAYER M4 ;
        RECT  17.064 8.88 17.256 8.904 ;
    END
  END do0[124]
  PIN do0[125]
    DIRECTION OUTPUT ;
    USE SIGNAL ;
    PORT
      LAYER M4 ;
        RECT  17.064 8.928 17.256 8.952 ;
    END
  END do0[125]
  PIN do0[126]
    DIRECTION OUTPUT ;
    USE SIGNAL ;
    PORT
      LAYER M4 ;
        RECT  17.064 8.976 17.256 9 ;
    END
  END do0[126]
  PIN do0[127]
    DIRECTION OUTPUT ;
    USE SIGNAL ;
    PORT
      LAYER M4 ;
        RECT  17.064 9.024 17.256 9.048 ;
    END
  END do0[127]
  PIN do0[128]
    DIRECTION OUTPUT ;
    USE SIGNAL ;
    PORT
      LAYER M4 ;
        RECT  17.064 9.072 17.256 9.096 ;
    END
  END do0[128]
  PIN do0[129]
    DIRECTION OUTPUT ;
    USE SIGNAL ;
    PORT
      LAYER M4 ;
        RECT  17.064 9.12 17.256 9.144 ;
    END
  END do0[129]
  PIN do0[12]
    DIRECTION OUTPUT ;
    USE SIGNAL ;
    PORT
      LAYER M4 ;
        RECT  17.064 3.504 17.256 3.528 ;
    END
  END do0[12]
  PIN do0[130]
    DIRECTION OUTPUT ;
    USE SIGNAL ;
    PORT
      LAYER M4 ;
        RECT  17.064 9.168 17.256 9.192 ;
    END
  END do0[130]
  PIN do0[131]
    DIRECTION OUTPUT ;
    USE SIGNAL ;
    PORT
      LAYER M4 ;
        RECT  17.064 9.216 17.256 9.24 ;
    END
  END do0[131]
  PIN do0[132]
    DIRECTION OUTPUT ;
    USE SIGNAL ;
    PORT
      LAYER M4 ;
        RECT  17.064 9.264 17.256 9.288 ;
    END
  END do0[132]
  PIN do0[133]
    DIRECTION OUTPUT ;
    USE SIGNAL ;
    PORT
      LAYER M4 ;
        RECT  17.064 9.312 17.256 9.336 ;
    END
  END do0[133]
  PIN do0[134]
    DIRECTION OUTPUT ;
    USE SIGNAL ;
    PORT
      LAYER M4 ;
        RECT  17.064 9.36 17.256 9.384 ;
    END
  END do0[134]
  PIN do0[135]
    DIRECTION OUTPUT ;
    USE SIGNAL ;
    PORT
      LAYER M4 ;
        RECT  17.064 9.408 17.256 9.432 ;
    END
  END do0[135]
  PIN do0[136]
    DIRECTION OUTPUT ;
    USE SIGNAL ;
    PORT
      LAYER M4 ;
        RECT  17.064 9.456 17.256 9.48 ;
    END
  END do0[136]
  PIN do0[137]
    DIRECTION OUTPUT ;
    USE SIGNAL ;
    PORT
      LAYER M4 ;
        RECT  17.064 9.504 17.256 9.528 ;
    END
  END do0[137]
  PIN do0[138]
    DIRECTION OUTPUT ;
    USE SIGNAL ;
    PORT
      LAYER M4 ;
        RECT  17.064 9.552 17.256 9.576 ;
    END
  END do0[138]
  PIN do0[139]
    DIRECTION OUTPUT ;
    USE SIGNAL ;
    PORT
      LAYER M4 ;
        RECT  17.064 9.6 17.256 9.624 ;
    END
  END do0[139]
  PIN do0[13]
    DIRECTION OUTPUT ;
    USE SIGNAL ;
    PORT
      LAYER M4 ;
        RECT  17.064 3.552 17.256 3.576 ;
    END
  END do0[13]
  PIN do0[140]
    DIRECTION OUTPUT ;
    USE SIGNAL ;
    PORT
      LAYER M4 ;
        RECT  17.064 9.648 17.256 9.672 ;
    END
  END do0[140]
  PIN do0[141]
    DIRECTION OUTPUT ;
    USE SIGNAL ;
    PORT
      LAYER M4 ;
        RECT  17.064 9.696 17.256 9.72 ;
    END
  END do0[141]
  PIN do0[142]
    DIRECTION OUTPUT ;
    USE SIGNAL ;
    PORT
      LAYER M4 ;
        RECT  17.064 9.744 17.256 9.768 ;
    END
  END do0[142]
  PIN do0[143]
    DIRECTION OUTPUT ;
    USE SIGNAL ;
    PORT
      LAYER M4 ;
        RECT  17.064 9.792 17.256 9.816 ;
    END
  END do0[143]
  PIN do0[144]
    DIRECTION OUTPUT ;
    USE SIGNAL ;
    PORT
      LAYER M4 ;
        RECT  17.064 9.84 17.256 9.864 ;
    END
  END do0[144]
  PIN do0[145]
    DIRECTION OUTPUT ;
    USE SIGNAL ;
    PORT
      LAYER M4 ;
        RECT  17.064 9.888 17.256 9.912 ;
    END
  END do0[145]
  PIN do0[146]
    DIRECTION OUTPUT ;
    USE SIGNAL ;
    PORT
      LAYER M4 ;
        RECT  17.064 9.936 17.256 9.96 ;
    END
  END do0[146]
  PIN do0[147]
    DIRECTION OUTPUT ;
    USE SIGNAL ;
    PORT
      LAYER M4 ;
        RECT  17.064 9.984 17.256 10.008 ;
    END
  END do0[147]
  PIN do0[148]
    DIRECTION OUTPUT ;
    USE SIGNAL ;
    PORT
      LAYER M4 ;
        RECT  17.064 10.032 17.256 10.056 ;
    END
  END do0[148]
  PIN do0[149]
    DIRECTION OUTPUT ;
    USE SIGNAL ;
    PORT
      LAYER M4 ;
        RECT  17.064 10.08 17.256 10.104 ;
    END
  END do0[149]
  PIN do0[14]
    DIRECTION OUTPUT ;
    USE SIGNAL ;
    PORT
      LAYER M4 ;
        RECT  17.064 3.6 17.256 3.624 ;
    END
  END do0[14]
  PIN do0[150]
    DIRECTION OUTPUT ;
    USE SIGNAL ;
    PORT
      LAYER M4 ;
        RECT  17.064 10.128 17.256 10.152 ;
    END
  END do0[150]
  PIN do0[151]
    DIRECTION OUTPUT ;
    USE SIGNAL ;
    PORT
      LAYER M4 ;
        RECT  17.064 10.176 17.256 10.2 ;
    END
  END do0[151]
  PIN do0[152]
    DIRECTION OUTPUT ;
    USE SIGNAL ;
    PORT
      LAYER M4 ;
        RECT  17.064 10.224 17.256 10.248 ;
    END
  END do0[152]
  PIN do0[153]
    DIRECTION OUTPUT ;
    USE SIGNAL ;
    PORT
      LAYER M4 ;
        RECT  17.064 10.272 17.256 10.296 ;
    END
  END do0[153]
  PIN do0[154]
    DIRECTION OUTPUT ;
    USE SIGNAL ;
    PORT
      LAYER M4 ;
        RECT  17.064 10.32 17.256 10.344 ;
    END
  END do0[154]
  PIN do0[155]
    DIRECTION OUTPUT ;
    USE SIGNAL ;
    PORT
      LAYER M4 ;
        RECT  17.064 10.368 17.256 10.392 ;
    END
  END do0[155]
  PIN do0[156]
    DIRECTION OUTPUT ;
    USE SIGNAL ;
    PORT
      LAYER M4 ;
        RECT  17.064 10.416 17.256 10.44 ;
    END
  END do0[156]
  PIN do0[157]
    DIRECTION OUTPUT ;
    USE SIGNAL ;
    PORT
      LAYER M4 ;
        RECT  17.064 10.464 17.256 10.488 ;
    END
  END do0[157]
  PIN do0[158]
    DIRECTION OUTPUT ;
    USE SIGNAL ;
    PORT
      LAYER M4 ;
        RECT  17.064 10.512 17.256 10.536 ;
    END
  END do0[158]
  PIN do0[159]
    DIRECTION OUTPUT ;
    USE SIGNAL ;
    PORT
      LAYER M4 ;
        RECT  17.064 10.56 17.256 10.584 ;
    END
  END do0[159]
  PIN do0[15]
    DIRECTION OUTPUT ;
    USE SIGNAL ;
    PORT
      LAYER M4 ;
        RECT  17.064 3.648 17.256 3.672 ;
    END
  END do0[15]
  PIN do0[160]
    DIRECTION OUTPUT ;
    USE SIGNAL ;
    PORT
      LAYER M4 ;
        RECT  17.064 10.608 17.256 10.632 ;
    END
  END do0[160]
  PIN do0[161]
    DIRECTION OUTPUT ;
    USE SIGNAL ;
    PORT
      LAYER M4 ;
        RECT  17.064 10.656 17.256 10.68 ;
    END
  END do0[161]
  PIN do0[162]
    DIRECTION OUTPUT ;
    USE SIGNAL ;
    PORT
      LAYER M4 ;
        RECT  17.064 10.704 17.256 10.728 ;
    END
  END do0[162]
  PIN do0[163]
    DIRECTION OUTPUT ;
    USE SIGNAL ;
    PORT
      LAYER M4 ;
        RECT  17.064 10.752 17.256 10.776 ;
    END
  END do0[163]
  PIN do0[164]
    DIRECTION OUTPUT ;
    USE SIGNAL ;
    PORT
      LAYER M4 ;
        RECT  17.064 10.8 17.256 10.824 ;
    END
  END do0[164]
  PIN do0[165]
    DIRECTION OUTPUT ;
    USE SIGNAL ;
    PORT
      LAYER M4 ;
        RECT  17.064 10.848 17.256 10.872 ;
    END
  END do0[165]
  PIN do0[166]
    DIRECTION OUTPUT ;
    USE SIGNAL ;
    PORT
      LAYER M4 ;
        RECT  17.064 10.896 17.256 10.92 ;
    END
  END do0[166]
  PIN do0[167]
    DIRECTION OUTPUT ;
    USE SIGNAL ;
    PORT
      LAYER M4 ;
        RECT  17.064 10.944 17.256 10.968 ;
    END
  END do0[167]
  PIN do0[168]
    DIRECTION OUTPUT ;
    USE SIGNAL ;
    PORT
      LAYER M4 ;
        RECT  17.064 10.992 17.256 11.016 ;
    END
  END do0[168]
  PIN do0[169]
    DIRECTION OUTPUT ;
    USE SIGNAL ;
    PORT
      LAYER M4 ;
        RECT  17.064 11.04 17.256 11.064 ;
    END
  END do0[169]
  PIN do0[16]
    DIRECTION OUTPUT ;
    USE SIGNAL ;
    PORT
      LAYER M4 ;
        RECT  17.064 3.696 17.256 3.72 ;
    END
  END do0[16]
  PIN do0[170]
    DIRECTION OUTPUT ;
    USE SIGNAL ;
    PORT
      LAYER M4 ;
        RECT  17.064 11.088 17.256 11.112 ;
    END
  END do0[170]
  PIN do0[171]
    DIRECTION OUTPUT ;
    USE SIGNAL ;
    PORT
      LAYER M4 ;
        RECT  17.064 11.136 17.256 11.16 ;
    END
  END do0[171]
  PIN do0[172]
    DIRECTION OUTPUT ;
    USE SIGNAL ;
    PORT
      LAYER M4 ;
        RECT  17.064 11.184 17.256 11.208 ;
    END
  END do0[172]
  PIN do0[173]
    DIRECTION OUTPUT ;
    USE SIGNAL ;
    PORT
      LAYER M4 ;
        RECT  17.064 11.232 17.256 11.256 ;
    END
  END do0[173]
  PIN do0[174]
    DIRECTION OUTPUT ;
    USE SIGNAL ;
    PORT
      LAYER M4 ;
        RECT  17.064 11.28 17.256 11.304 ;
    END
  END do0[174]
  PIN do0[175]
    DIRECTION OUTPUT ;
    USE SIGNAL ;
    PORT
      LAYER M4 ;
        RECT  17.064 11.328 17.256 11.352 ;
    END
  END do0[175]
  PIN do0[176]
    DIRECTION OUTPUT ;
    USE SIGNAL ;
    PORT
      LAYER M4 ;
        RECT  17.064 11.376 17.256 11.4 ;
    END
  END do0[176]
  PIN do0[177]
    DIRECTION OUTPUT ;
    USE SIGNAL ;
    PORT
      LAYER M4 ;
        RECT  17.064 11.424 17.256 11.448 ;
    END
  END do0[177]
  PIN do0[178]
    DIRECTION OUTPUT ;
    USE SIGNAL ;
    PORT
      LAYER M4 ;
        RECT  17.064 11.472 17.256 11.496 ;
    END
  END do0[178]
  PIN do0[179]
    DIRECTION OUTPUT ;
    USE SIGNAL ;
    PORT
      LAYER M4 ;
        RECT  17.064 11.52 17.256 11.544 ;
    END
  END do0[179]
  PIN do0[17]
    DIRECTION OUTPUT ;
    USE SIGNAL ;
    PORT
      LAYER M4 ;
        RECT  17.064 3.744 17.256 3.768 ;
    END
  END do0[17]
  PIN do0[180]
    DIRECTION OUTPUT ;
    USE SIGNAL ;
    PORT
      LAYER M4 ;
        RECT  17.064 11.568 17.256 11.592 ;
    END
  END do0[180]
  PIN do0[181]
    DIRECTION OUTPUT ;
    USE SIGNAL ;
    PORT
      LAYER M4 ;
        RECT  17.064 11.616 17.256 11.64 ;
    END
  END do0[181]
  PIN do0[182]
    DIRECTION OUTPUT ;
    USE SIGNAL ;
    PORT
      LAYER M4 ;
        RECT  17.064 11.664 17.256 11.688 ;
    END
  END do0[182]
  PIN do0[183]
    DIRECTION OUTPUT ;
    USE SIGNAL ;
    PORT
      LAYER M4 ;
        RECT  17.064 11.712 17.256 11.736 ;
    END
  END do0[183]
  PIN do0[184]
    DIRECTION OUTPUT ;
    USE SIGNAL ;
    PORT
      LAYER M4 ;
        RECT  17.064 11.76 17.256 11.784 ;
    END
  END do0[184]
  PIN do0[185]
    DIRECTION OUTPUT ;
    USE SIGNAL ;
    PORT
      LAYER M4 ;
        RECT  17.064 11.808 17.256 11.832 ;
    END
  END do0[185]
  PIN do0[186]
    DIRECTION OUTPUT ;
    USE SIGNAL ;
    PORT
      LAYER M4 ;
        RECT  17.064 11.856 17.256 11.88 ;
    END
  END do0[186]
  PIN do0[187]
    DIRECTION OUTPUT ;
    USE SIGNAL ;
    PORT
      LAYER M4 ;
        RECT  17.064 11.904 17.256 11.928 ;
    END
  END do0[187]
  PIN do0[188]
    DIRECTION OUTPUT ;
    USE SIGNAL ;
    PORT
      LAYER M4 ;
        RECT  17.064 11.952 17.256 11.976 ;
    END
  END do0[188]
  PIN do0[189]
    DIRECTION OUTPUT ;
    USE SIGNAL ;
    PORT
      LAYER M4 ;
        RECT  17.064 12 17.256 12.024 ;
    END
  END do0[189]
  PIN do0[18]
    DIRECTION OUTPUT ;
    USE SIGNAL ;
    PORT
      LAYER M4 ;
        RECT  17.064 3.792 17.256 3.816 ;
    END
  END do0[18]
  PIN do0[190]
    DIRECTION OUTPUT ;
    USE SIGNAL ;
    PORT
      LAYER M4 ;
        RECT  17.064 12.048 17.256 12.072 ;
    END
  END do0[190]
  PIN do0[191]
    DIRECTION OUTPUT ;
    USE SIGNAL ;
    PORT
      LAYER M4 ;
        RECT  17.064 12.096 17.256 12.12 ;
    END
  END do0[191]
  PIN do0[192]
    DIRECTION OUTPUT ;
    USE SIGNAL ;
    PORT
      LAYER M4 ;
        RECT  17.064 12.144 17.256 12.168 ;
    END
  END do0[192]
  PIN do0[193]
    DIRECTION OUTPUT ;
    USE SIGNAL ;
    PORT
      LAYER M4 ;
        RECT  17.064 12.192 17.256 12.216 ;
    END
  END do0[193]
  PIN do0[194]
    DIRECTION OUTPUT ;
    USE SIGNAL ;
    PORT
      LAYER M4 ;
        RECT  17.064 12.24 17.256 12.264 ;
    END
  END do0[194]
  PIN do0[195]
    DIRECTION OUTPUT ;
    USE SIGNAL ;
    PORT
      LAYER M4 ;
        RECT  17.064 12.288 17.256 12.312 ;
    END
  END do0[195]
  PIN do0[196]
    DIRECTION OUTPUT ;
    USE SIGNAL ;
    PORT
      LAYER M4 ;
        RECT  17.064 12.336 17.256 12.36 ;
    END
  END do0[196]
  PIN do0[197]
    DIRECTION OUTPUT ;
    USE SIGNAL ;
    PORT
      LAYER M4 ;
        RECT  17.064 12.384 17.256 12.408 ;
    END
  END do0[197]
  PIN do0[198]
    DIRECTION OUTPUT ;
    USE SIGNAL ;
    PORT
      LAYER M4 ;
        RECT  17.064 12.432 17.256 12.456 ;
    END
  END do0[198]
  PIN do0[199]
    DIRECTION OUTPUT ;
    USE SIGNAL ;
    PORT
      LAYER M4 ;
        RECT  17.064 12.48 17.256 12.504 ;
    END
  END do0[199]
  PIN do0[19]
    DIRECTION OUTPUT ;
    USE SIGNAL ;
    PORT
      LAYER M4 ;
        RECT  17.064 3.84 17.256 3.864 ;
    END
  END do0[19]
  PIN do0[1]
    DIRECTION OUTPUT ;
    USE SIGNAL ;
    PORT
      LAYER M4 ;
        RECT  17.064 2.976 17.256 3 ;
    END
  END do0[1]
  PIN do0[200]
    DIRECTION OUTPUT ;
    USE SIGNAL ;
    PORT
      LAYER M4 ;
        RECT  17.064 12.528 17.256 12.552 ;
    END
  END do0[200]
  PIN do0[201]
    DIRECTION OUTPUT ;
    USE SIGNAL ;
    PORT
      LAYER M4 ;
        RECT  17.064 12.576 17.256 12.6 ;
    END
  END do0[201]
  PIN do0[202]
    DIRECTION OUTPUT ;
    USE SIGNAL ;
    PORT
      LAYER M4 ;
        RECT  17.064 12.624 17.256 12.648 ;
    END
  END do0[202]
  PIN do0[203]
    DIRECTION OUTPUT ;
    USE SIGNAL ;
    PORT
      LAYER M4 ;
        RECT  17.064 12.672 17.256 12.696 ;
    END
  END do0[203]
  PIN do0[204]
    DIRECTION OUTPUT ;
    USE SIGNAL ;
    PORT
      LAYER M4 ;
        RECT  17.064 12.72 17.256 12.744 ;
    END
  END do0[204]
  PIN do0[205]
    DIRECTION OUTPUT ;
    USE SIGNAL ;
    PORT
      LAYER M4 ;
        RECT  17.064 12.768 17.256 12.792 ;
    END
  END do0[205]
  PIN do0[206]
    DIRECTION OUTPUT ;
    USE SIGNAL ;
    PORT
      LAYER M4 ;
        RECT  17.064 12.816 17.256 12.84 ;
    END
  END do0[206]
  PIN do0[207]
    DIRECTION OUTPUT ;
    USE SIGNAL ;
    PORT
      LAYER M4 ;
        RECT  17.064 12.864 17.256 12.888 ;
    END
  END do0[207]
  PIN do0[208]
    DIRECTION OUTPUT ;
    USE SIGNAL ;
    PORT
      LAYER M4 ;
        RECT  17.064 12.912 17.256 12.936 ;
    END
  END do0[208]
  PIN do0[209]
    DIRECTION OUTPUT ;
    USE SIGNAL ;
    PORT
      LAYER M4 ;
        RECT  17.064 12.96 17.256 12.984 ;
    END
  END do0[209]
  PIN do0[20]
    DIRECTION OUTPUT ;
    USE SIGNAL ;
    PORT
      LAYER M4 ;
        RECT  17.064 3.888 17.256 3.912 ;
    END
  END do0[20]
  PIN do0[210]
    DIRECTION OUTPUT ;
    USE SIGNAL ;
    PORT
      LAYER M4 ;
        RECT  17.064 13.008 17.256 13.032 ;
    END
  END do0[210]
  PIN do0[211]
    DIRECTION OUTPUT ;
    USE SIGNAL ;
    PORT
      LAYER M4 ;
        RECT  17.064 13.056 17.256 13.08 ;
    END
  END do0[211]
  PIN do0[212]
    DIRECTION OUTPUT ;
    USE SIGNAL ;
    PORT
      LAYER M4 ;
        RECT  17.064 13.104 17.256 13.128 ;
    END
  END do0[212]
  PIN do0[213]
    DIRECTION OUTPUT ;
    USE SIGNAL ;
    PORT
      LAYER M4 ;
        RECT  17.064 13.152 17.256 13.176 ;
    END
  END do0[213]
  PIN do0[214]
    DIRECTION OUTPUT ;
    USE SIGNAL ;
    PORT
      LAYER M4 ;
        RECT  17.064 13.2 17.256 13.224 ;
    END
  END do0[214]
  PIN do0[215]
    DIRECTION OUTPUT ;
    USE SIGNAL ;
    PORT
      LAYER M4 ;
        RECT  17.064 13.248 17.256 13.272 ;
    END
  END do0[215]
  PIN do0[216]
    DIRECTION OUTPUT ;
    USE SIGNAL ;
    PORT
      LAYER M4 ;
        RECT  17.064 13.296 17.256 13.32 ;
    END
  END do0[216]
  PIN do0[217]
    DIRECTION OUTPUT ;
    USE SIGNAL ;
    PORT
      LAYER M4 ;
        RECT  17.064 13.344 17.256 13.368 ;
    END
  END do0[217]
  PIN do0[218]
    DIRECTION OUTPUT ;
    USE SIGNAL ;
    PORT
      LAYER M4 ;
        RECT  17.064 13.392 17.256 13.416 ;
    END
  END do0[218]
  PIN do0[219]
    DIRECTION OUTPUT ;
    USE SIGNAL ;
    PORT
      LAYER M4 ;
        RECT  17.064 13.44 17.256 13.464 ;
    END
  END do0[219]
  PIN do0[21]
    DIRECTION OUTPUT ;
    USE SIGNAL ;
    PORT
      LAYER M4 ;
        RECT  17.064 3.936 17.256 3.96 ;
    END
  END do0[21]
  PIN do0[220]
    DIRECTION OUTPUT ;
    USE SIGNAL ;
    PORT
      LAYER M4 ;
        RECT  17.064 13.488 17.256 13.512 ;
    END
  END do0[220]
  PIN do0[221]
    DIRECTION OUTPUT ;
    USE SIGNAL ;
    PORT
      LAYER M4 ;
        RECT  17.064 13.536 17.256 13.56 ;
    END
  END do0[221]
  PIN do0[222]
    DIRECTION OUTPUT ;
    USE SIGNAL ;
    PORT
      LAYER M4 ;
        RECT  17.064 13.584 17.256 13.608 ;
    END
  END do0[222]
  PIN do0[223]
    DIRECTION OUTPUT ;
    USE SIGNAL ;
    PORT
      LAYER M4 ;
        RECT  17.064 13.632 17.256 13.656 ;
    END
  END do0[223]
  PIN do0[224]
    DIRECTION OUTPUT ;
    USE SIGNAL ;
    PORT
      LAYER M4 ;
        RECT  17.064 13.68 17.256 13.704 ;
    END
  END do0[224]
  PIN do0[225]
    DIRECTION OUTPUT ;
    USE SIGNAL ;
    PORT
      LAYER M4 ;
        RECT  17.064 13.728 17.256 13.752 ;
    END
  END do0[225]
  PIN do0[226]
    DIRECTION OUTPUT ;
    USE SIGNAL ;
    PORT
      LAYER M4 ;
        RECT  17.064 13.776 17.256 13.8 ;
    END
  END do0[226]
  PIN do0[227]
    DIRECTION OUTPUT ;
    USE SIGNAL ;
    PORT
      LAYER M4 ;
        RECT  17.064 13.824 17.256 13.848 ;
    END
  END do0[227]
  PIN do0[228]
    DIRECTION OUTPUT ;
    USE SIGNAL ;
    PORT
      LAYER M4 ;
        RECT  17.064 13.872 17.256 13.896 ;
    END
  END do0[228]
  PIN do0[229]
    DIRECTION OUTPUT ;
    USE SIGNAL ;
    PORT
      LAYER M4 ;
        RECT  17.064 13.92 17.256 13.944 ;
    END
  END do0[229]
  PIN do0[22]
    DIRECTION OUTPUT ;
    USE SIGNAL ;
    PORT
      LAYER M4 ;
        RECT  17.064 3.984 17.256 4.008 ;
    END
  END do0[22]
  PIN do0[230]
    DIRECTION OUTPUT ;
    USE SIGNAL ;
    PORT
      LAYER M4 ;
        RECT  17.064 13.968 17.256 13.992 ;
    END
  END do0[230]
  PIN do0[231]
    DIRECTION OUTPUT ;
    USE SIGNAL ;
    PORT
      LAYER M4 ;
        RECT  17.064 14.016 17.256 14.04 ;
    END
  END do0[231]
  PIN do0[232]
    DIRECTION OUTPUT ;
    USE SIGNAL ;
    PORT
      LAYER M4 ;
        RECT  17.064 14.064 17.256 14.088 ;
    END
  END do0[232]
  PIN do0[233]
    DIRECTION OUTPUT ;
    USE SIGNAL ;
    PORT
      LAYER M4 ;
        RECT  17.064 14.112 17.256 14.136 ;
    END
  END do0[233]
  PIN do0[234]
    DIRECTION OUTPUT ;
    USE SIGNAL ;
    PORT
      LAYER M4 ;
        RECT  17.064 14.16 17.256 14.184 ;
    END
  END do0[234]
  PIN do0[235]
    DIRECTION OUTPUT ;
    USE SIGNAL ;
    PORT
      LAYER M4 ;
        RECT  17.064 14.208 17.256 14.232 ;
    END
  END do0[235]
  PIN do0[236]
    DIRECTION OUTPUT ;
    USE SIGNAL ;
    PORT
      LAYER M4 ;
        RECT  17.064 14.256 17.256 14.28 ;
    END
  END do0[236]
  PIN do0[237]
    DIRECTION OUTPUT ;
    USE SIGNAL ;
    PORT
      LAYER M4 ;
        RECT  17.064 14.304 17.256 14.328 ;
    END
  END do0[237]
  PIN do0[238]
    DIRECTION OUTPUT ;
    USE SIGNAL ;
    PORT
      LAYER M4 ;
        RECT  17.064 14.352 17.256 14.376 ;
    END
  END do0[238]
  PIN do0[239]
    DIRECTION OUTPUT ;
    USE SIGNAL ;
    PORT
      LAYER M4 ;
        RECT  17.064 14.4 17.256 14.424 ;
    END
  END do0[239]
  PIN do0[23]
    DIRECTION OUTPUT ;
    USE SIGNAL ;
    PORT
      LAYER M4 ;
        RECT  17.064 4.032 17.256 4.056 ;
    END
  END do0[23]
  PIN do0[240]
    DIRECTION OUTPUT ;
    USE SIGNAL ;
    PORT
      LAYER M4 ;
        RECT  17.064 14.448 17.256 14.472 ;
    END
  END do0[240]
  PIN do0[241]
    DIRECTION OUTPUT ;
    USE SIGNAL ;
    PORT
      LAYER M4 ;
        RECT  17.064 14.496 17.256 14.52 ;
    END
  END do0[241]
  PIN do0[242]
    DIRECTION OUTPUT ;
    USE SIGNAL ;
    PORT
      LAYER M4 ;
        RECT  17.064 14.544 17.256 14.568 ;
    END
  END do0[242]
  PIN do0[243]
    DIRECTION OUTPUT ;
    USE SIGNAL ;
    PORT
      LAYER M4 ;
        RECT  17.064 14.592 17.256 14.616 ;
    END
  END do0[243]
  PIN do0[244]
    DIRECTION OUTPUT ;
    USE SIGNAL ;
    PORT
      LAYER M4 ;
        RECT  17.064 14.64 17.256 14.664 ;
    END
  END do0[244]
  PIN do0[245]
    DIRECTION OUTPUT ;
    USE SIGNAL ;
    PORT
      LAYER M4 ;
        RECT  17.064 14.688 17.256 14.712 ;
    END
  END do0[245]
  PIN do0[246]
    DIRECTION OUTPUT ;
    USE SIGNAL ;
    PORT
      LAYER M4 ;
        RECT  17.064 14.736 17.256 14.76 ;
    END
  END do0[246]
  PIN do0[247]
    DIRECTION OUTPUT ;
    USE SIGNAL ;
    PORT
      LAYER M4 ;
        RECT  17.064 14.784 17.256 14.808 ;
    END
  END do0[247]
  PIN do0[248]
    DIRECTION OUTPUT ;
    USE SIGNAL ;
    PORT
      LAYER M4 ;
        RECT  17.064 14.832 17.256 14.856 ;
    END
  END do0[248]
  PIN do0[249]
    DIRECTION OUTPUT ;
    USE SIGNAL ;
    PORT
      LAYER M4 ;
        RECT  17.064 14.88 17.256 14.904 ;
    END
  END do0[249]
  PIN do0[24]
    DIRECTION OUTPUT ;
    USE SIGNAL ;
    PORT
      LAYER M4 ;
        RECT  17.064 4.08 17.256 4.104 ;
    END
  END do0[24]
  PIN do0[250]
    DIRECTION OUTPUT ;
    USE SIGNAL ;
    PORT
      LAYER M4 ;
        RECT  17.064 14.928 17.256 14.952 ;
    END
  END do0[250]
  PIN do0[251]
    DIRECTION OUTPUT ;
    USE SIGNAL ;
    PORT
      LAYER M4 ;
        RECT  17.064 14.976 17.256 15 ;
    END
  END do0[251]
  PIN do0[252]
    DIRECTION OUTPUT ;
    USE SIGNAL ;
    PORT
      LAYER M4 ;
        RECT  17.064 15.024 17.256 15.048 ;
    END
  END do0[252]
  PIN do0[253]
    DIRECTION OUTPUT ;
    USE SIGNAL ;
    PORT
      LAYER M4 ;
        RECT  17.064 15.072 17.256 15.096 ;
    END
  END do0[253]
  PIN do0[254]
    DIRECTION OUTPUT ;
    USE SIGNAL ;
    PORT
      LAYER M4 ;
        RECT  17.064 15.12 17.256 15.144 ;
    END
  END do0[254]
  PIN do0[255]
    DIRECTION OUTPUT ;
    USE SIGNAL ;
    PORT
      LAYER M4 ;
        RECT  17.064 15.168 17.256 15.192 ;
    END
  END do0[255]
  PIN do0[256]
    DIRECTION OUTPUT ;
    USE SIGNAL ;
    PORT
      LAYER M4 ;
        RECT  17.064 15.216 17.256 15.24 ;
    END
  END do0[256]
  PIN do0[257]
    DIRECTION OUTPUT ;
    USE SIGNAL ;
    PORT
      LAYER M4 ;
        RECT  17.064 15.264 17.256 15.288 ;
    END
  END do0[257]
  PIN do0[258]
    DIRECTION OUTPUT ;
    USE SIGNAL ;
    PORT
      LAYER M4 ;
        RECT  17.064 15.312 17.256 15.336 ;
    END
  END do0[258]
  PIN do0[259]
    DIRECTION OUTPUT ;
    USE SIGNAL ;
    PORT
      LAYER M4 ;
        RECT  17.064 15.36 17.256 15.384 ;
    END
  END do0[259]
  PIN do0[25]
    DIRECTION OUTPUT ;
    USE SIGNAL ;
    PORT
      LAYER M4 ;
        RECT  17.064 4.128 17.256 4.152 ;
    END
  END do0[25]
  PIN do0[260]
    DIRECTION OUTPUT ;
    USE SIGNAL ;
    PORT
      LAYER M4 ;
        RECT  17.064 15.408 17.256 15.432 ;
    END
  END do0[260]
  PIN do0[261]
    DIRECTION OUTPUT ;
    USE SIGNAL ;
    PORT
      LAYER M4 ;
        RECT  17.064 15.456 17.256 15.48 ;
    END
  END do0[261]
  PIN do0[262]
    DIRECTION OUTPUT ;
    USE SIGNAL ;
    PORT
      LAYER M4 ;
        RECT  17.064 15.504 17.256 15.528 ;
    END
  END do0[262]
  PIN do0[263]
    DIRECTION OUTPUT ;
    USE SIGNAL ;
    PORT
      LAYER M4 ;
        RECT  17.064 15.552 17.256 15.576 ;
    END
  END do0[263]
  PIN do0[264]
    DIRECTION OUTPUT ;
    USE SIGNAL ;
    PORT
      LAYER M4 ;
        RECT  17.064 15.6 17.256 15.624 ;
    END
  END do0[264]
  PIN do0[265]
    DIRECTION OUTPUT ;
    USE SIGNAL ;
    PORT
      LAYER M4 ;
        RECT  17.064 15.648 17.256 15.672 ;
    END
  END do0[265]
  PIN do0[266]
    DIRECTION OUTPUT ;
    USE SIGNAL ;
    PORT
      LAYER M4 ;
        RECT  17.064 15.696 17.256 15.72 ;
    END
  END do0[266]
  PIN do0[267]
    DIRECTION OUTPUT ;
    USE SIGNAL ;
    PORT
      LAYER M4 ;
        RECT  17.064 15.744 17.256 15.768 ;
    END
  END do0[267]
  PIN do0[268]
    DIRECTION OUTPUT ;
    USE SIGNAL ;
    PORT
      LAYER M4 ;
        RECT  17.064 15.792 17.256 15.816 ;
    END
  END do0[268]
  PIN do0[269]
    DIRECTION OUTPUT ;
    USE SIGNAL ;
    PORT
      LAYER M4 ;
        RECT  17.064 15.84 17.256 15.864 ;
    END
  END do0[269]
  PIN do0[26]
    DIRECTION OUTPUT ;
    USE SIGNAL ;
    PORT
      LAYER M4 ;
        RECT  17.064 4.176 17.256 4.2 ;
    END
  END do0[26]
  PIN do0[270]
    DIRECTION OUTPUT ;
    USE SIGNAL ;
    PORT
      LAYER M4 ;
        RECT  17.064 15.888 17.256 15.912 ;
    END
  END do0[270]
  PIN do0[271]
    DIRECTION OUTPUT ;
    USE SIGNAL ;
    PORT
      LAYER M4 ;
        RECT  17.064 15.936 17.256 15.96 ;
    END
  END do0[271]
  PIN do0[272]
    DIRECTION OUTPUT ;
    USE SIGNAL ;
    PORT
      LAYER M4 ;
        RECT  17.064 15.984 17.256 16.008 ;
    END
  END do0[272]
  PIN do0[273]
    DIRECTION OUTPUT ;
    USE SIGNAL ;
    PORT
      LAYER M4 ;
        RECT  17.064 16.032 17.256 16.056 ;
    END
  END do0[273]
  PIN do0[274]
    DIRECTION OUTPUT ;
    USE SIGNAL ;
    PORT
      LAYER M4 ;
        RECT  17.064 16.08 17.256 16.104 ;
    END
  END do0[274]
  PIN do0[275]
    DIRECTION OUTPUT ;
    USE SIGNAL ;
    PORT
      LAYER M4 ;
        RECT  17.064 16.128 17.256 16.152 ;
    END
  END do0[275]
  PIN do0[276]
    DIRECTION OUTPUT ;
    USE SIGNAL ;
    PORT
      LAYER M4 ;
        RECT  17.064 16.176 17.256 16.2 ;
    END
  END do0[276]
  PIN do0[277]
    DIRECTION OUTPUT ;
    USE SIGNAL ;
    PORT
      LAYER M4 ;
        RECT  17.064 16.224 17.256 16.248 ;
    END
  END do0[277]
  PIN do0[278]
    DIRECTION OUTPUT ;
    USE SIGNAL ;
    PORT
      LAYER M4 ;
        RECT  17.064 16.272 17.256 16.296 ;
    END
  END do0[278]
  PIN do0[279]
    DIRECTION OUTPUT ;
    USE SIGNAL ;
    PORT
      LAYER M4 ;
        RECT  17.064 16.32 17.256 16.344 ;
    END
  END do0[279]
  PIN do0[27]
    DIRECTION OUTPUT ;
    USE SIGNAL ;
    PORT
      LAYER M4 ;
        RECT  17.064 4.224 17.256 4.248 ;
    END
  END do0[27]
  PIN do0[280]
    DIRECTION OUTPUT ;
    USE SIGNAL ;
    PORT
      LAYER M4 ;
        RECT  17.064 16.368 17.256 16.392 ;
    END
  END do0[280]
  PIN do0[281]
    DIRECTION OUTPUT ;
    USE SIGNAL ;
    PORT
      LAYER M4 ;
        RECT  17.064 16.416 17.256 16.44 ;
    END
  END do0[281]
  PIN do0[282]
    DIRECTION OUTPUT ;
    USE SIGNAL ;
    PORT
      LAYER M4 ;
        RECT  17.064 16.464 17.256 16.488 ;
    END
  END do0[282]
  PIN do0[283]
    DIRECTION OUTPUT ;
    USE SIGNAL ;
    PORT
      LAYER M4 ;
        RECT  17.064 16.512 17.256 16.536 ;
    END
  END do0[283]
  PIN do0[284]
    DIRECTION OUTPUT ;
    USE SIGNAL ;
    PORT
      LAYER M4 ;
        RECT  17.064 16.56 17.256 16.584 ;
    END
  END do0[284]
  PIN do0[285]
    DIRECTION OUTPUT ;
    USE SIGNAL ;
    PORT
      LAYER M4 ;
        RECT  17.064 16.608 17.256 16.632 ;
    END
  END do0[285]
  PIN do0[286]
    DIRECTION OUTPUT ;
    USE SIGNAL ;
    PORT
      LAYER M4 ;
        RECT  17.064 16.656 17.256 16.68 ;
    END
  END do0[286]
  PIN do0[287]
    DIRECTION OUTPUT ;
    USE SIGNAL ;
    PORT
      LAYER M4 ;
        RECT  17.064 16.704 17.256 16.728 ;
    END
  END do0[287]
  PIN do0[288]
    DIRECTION OUTPUT ;
    USE SIGNAL ;
    PORT
      LAYER M4 ;
        RECT  17.064 16.752 17.256 16.776 ;
    END
  END do0[288]
  PIN do0[289]
    DIRECTION OUTPUT ;
    USE SIGNAL ;
    PORT
      LAYER M4 ;
        RECT  17.064 16.8 17.256 16.824 ;
    END
  END do0[289]
  PIN do0[28]
    DIRECTION OUTPUT ;
    USE SIGNAL ;
    PORT
      LAYER M4 ;
        RECT  17.064 4.272 17.256 4.296 ;
    END
  END do0[28]
  PIN do0[290]
    DIRECTION OUTPUT ;
    USE SIGNAL ;
    PORT
      LAYER M4 ;
        RECT  17.064 16.848 17.256 16.872 ;
    END
  END do0[290]
  PIN do0[291]
    DIRECTION OUTPUT ;
    USE SIGNAL ;
    PORT
      LAYER M4 ;
        RECT  17.064 16.896 17.256 16.92 ;
    END
  END do0[291]
  PIN do0[292]
    DIRECTION OUTPUT ;
    USE SIGNAL ;
    PORT
      LAYER M4 ;
        RECT  17.064 16.944 17.256 16.968 ;
    END
  END do0[292]
  PIN do0[293]
    DIRECTION OUTPUT ;
    USE SIGNAL ;
    PORT
      LAYER M4 ;
        RECT  17.064 16.992 17.256 17.016 ;
    END
  END do0[293]
  PIN do0[294]
    DIRECTION OUTPUT ;
    USE SIGNAL ;
    PORT
      LAYER M4 ;
        RECT  17.064 17.04 17.256 17.064 ;
    END
  END do0[294]
  PIN do0[295]
    DIRECTION OUTPUT ;
    USE SIGNAL ;
    PORT
      LAYER M4 ;
        RECT  17.064 17.088 17.256 17.112 ;
    END
  END do0[295]
  PIN do0[296]
    DIRECTION OUTPUT ;
    USE SIGNAL ;
    PORT
      LAYER M4 ;
        RECT  17.064 17.136 17.256 17.16 ;
    END
  END do0[296]
  PIN do0[297]
    DIRECTION OUTPUT ;
    USE SIGNAL ;
    PORT
      LAYER M4 ;
        RECT  17.064 17.184 17.256 17.208 ;
    END
  END do0[297]
  PIN do0[298]
    DIRECTION OUTPUT ;
    USE SIGNAL ;
    PORT
      LAYER M4 ;
        RECT  17.064 17.232 17.256 17.256 ;
    END
  END do0[298]
  PIN do0[299]
    DIRECTION OUTPUT ;
    USE SIGNAL ;
    PORT
      LAYER M4 ;
        RECT  17.064 17.28 17.256 17.304 ;
    END
  END do0[299]
  PIN do0[29]
    DIRECTION OUTPUT ;
    USE SIGNAL ;
    PORT
      LAYER M4 ;
        RECT  17.064 4.32 17.256 4.344 ;
    END
  END do0[29]
  PIN do0[2]
    DIRECTION OUTPUT ;
    USE SIGNAL ;
    PORT
      LAYER M4 ;
        RECT  17.064 3.024 17.256 3.048 ;
    END
  END do0[2]
  PIN do0[300]
    DIRECTION OUTPUT ;
    USE SIGNAL ;
    PORT
      LAYER M4 ;
        RECT  17.064 17.328 17.256 17.352 ;
    END
  END do0[300]
  PIN do0[301]
    DIRECTION OUTPUT ;
    USE SIGNAL ;
    PORT
      LAYER M4 ;
        RECT  17.064 17.376 17.256 17.4 ;
    END
  END do0[301]
  PIN do0[302]
    DIRECTION OUTPUT ;
    USE SIGNAL ;
    PORT
      LAYER M4 ;
        RECT  17.064 17.424 17.256 17.448 ;
    END
  END do0[302]
  PIN do0[303]
    DIRECTION OUTPUT ;
    USE SIGNAL ;
    PORT
      LAYER M4 ;
        RECT  17.064 17.472 17.256 17.496 ;
    END
  END do0[303]
  PIN do0[304]
    DIRECTION OUTPUT ;
    USE SIGNAL ;
    PORT
      LAYER M4 ;
        RECT  17.064 17.52 17.256 17.544 ;
    END
  END do0[304]
  PIN do0[305]
    DIRECTION OUTPUT ;
    USE SIGNAL ;
    PORT
      LAYER M4 ;
        RECT  17.064 17.568 17.256 17.592 ;
    END
  END do0[305]
  PIN do0[306]
    DIRECTION OUTPUT ;
    USE SIGNAL ;
    PORT
      LAYER M4 ;
        RECT  17.064 17.616 17.256 17.64 ;
    END
  END do0[306]
  PIN do0[307]
    DIRECTION OUTPUT ;
    USE SIGNAL ;
    PORT
      LAYER M4 ;
        RECT  17.064 17.664 17.256 17.688 ;
    END
  END do0[307]
  PIN do0[308]
    DIRECTION OUTPUT ;
    USE SIGNAL ;
    PORT
      LAYER M4 ;
        RECT  17.064 17.712 17.256 17.736 ;
    END
  END do0[308]
  PIN do0[309]
    DIRECTION OUTPUT ;
    USE SIGNAL ;
    PORT
      LAYER M4 ;
        RECT  17.064 17.76 17.256 17.784 ;
    END
  END do0[309]
  PIN do0[30]
    DIRECTION OUTPUT ;
    USE SIGNAL ;
    PORT
      LAYER M4 ;
        RECT  17.064 4.368 17.256 4.392 ;
    END
  END do0[30]
  PIN do0[310]
    DIRECTION OUTPUT ;
    USE SIGNAL ;
    PORT
      LAYER M4 ;
        RECT  17.064 17.808 17.256 17.832 ;
    END
  END do0[310]
  PIN do0[311]
    DIRECTION OUTPUT ;
    USE SIGNAL ;
    PORT
      LAYER M4 ;
        RECT  17.064 17.856 17.256 17.88 ;
    END
  END do0[311]
  PIN do0[312]
    DIRECTION OUTPUT ;
    USE SIGNAL ;
    PORT
      LAYER M4 ;
        RECT  17.064 17.904 17.256 17.928 ;
    END
  END do0[312]
  PIN do0[313]
    DIRECTION OUTPUT ;
    USE SIGNAL ;
    PORT
      LAYER M4 ;
        RECT  17.064 17.952 17.256 17.976 ;
    END
  END do0[313]
  PIN do0[314]
    DIRECTION OUTPUT ;
    USE SIGNAL ;
    PORT
      LAYER M4 ;
        RECT  17.064 18 17.256 18.024 ;
    END
  END do0[314]
  PIN do0[315]
    DIRECTION OUTPUT ;
    USE SIGNAL ;
    PORT
      LAYER M4 ;
        RECT  17.064 18.048 17.256 18.072 ;
    END
  END do0[315]
  PIN do0[316]
    DIRECTION OUTPUT ;
    USE SIGNAL ;
    PORT
      LAYER M4 ;
        RECT  17.064 18.096 17.256 18.12 ;
    END
  END do0[316]
  PIN do0[317]
    DIRECTION OUTPUT ;
    USE SIGNAL ;
    PORT
      LAYER M4 ;
        RECT  17.064 18.144 17.256 18.168 ;
    END
  END do0[317]
  PIN do0[318]
    DIRECTION OUTPUT ;
    USE SIGNAL ;
    PORT
      LAYER M4 ;
        RECT  17.064 18.192 17.256 18.216 ;
    END
  END do0[318]
  PIN do0[319]
    DIRECTION OUTPUT ;
    USE SIGNAL ;
    PORT
      LAYER M4 ;
        RECT  17.064 18.24 17.256 18.264 ;
    END
  END do0[319]
  PIN do0[31]
    DIRECTION OUTPUT ;
    USE SIGNAL ;
    PORT
      LAYER M4 ;
        RECT  17.064 4.416 17.256 4.44 ;
    END
  END do0[31]
  PIN do0[320]
    DIRECTION OUTPUT ;
    USE SIGNAL ;
    PORT
      LAYER M4 ;
        RECT  17.064 18.288 17.256 18.312 ;
    END
  END do0[320]
  PIN do0[321]
    DIRECTION OUTPUT ;
    USE SIGNAL ;
    PORT
      LAYER M4 ;
        RECT  17.064 18.336 17.256 18.36 ;
    END
  END do0[321]
  PIN do0[322]
    DIRECTION OUTPUT ;
    USE SIGNAL ;
    PORT
      LAYER M4 ;
        RECT  17.064 18.384 17.256 18.408 ;
    END
  END do0[322]
  PIN do0[323]
    DIRECTION OUTPUT ;
    USE SIGNAL ;
    PORT
      LAYER M4 ;
        RECT  17.064 18.432 17.256 18.456 ;
    END
  END do0[323]
  PIN do0[324]
    DIRECTION OUTPUT ;
    USE SIGNAL ;
    PORT
      LAYER M4 ;
        RECT  17.064 18.48 17.256 18.504 ;
    END
  END do0[324]
  PIN do0[325]
    DIRECTION OUTPUT ;
    USE SIGNAL ;
    PORT
      LAYER M4 ;
        RECT  17.064 18.528 17.256 18.552 ;
    END
  END do0[325]
  PIN do0[326]
    DIRECTION OUTPUT ;
    USE SIGNAL ;
    PORT
      LAYER M4 ;
        RECT  17.064 18.576 17.256 18.6 ;
    END
  END do0[326]
  PIN do0[327]
    DIRECTION OUTPUT ;
    USE SIGNAL ;
    PORT
      LAYER M4 ;
        RECT  17.064 18.624 17.256 18.648 ;
    END
  END do0[327]
  PIN do0[328]
    DIRECTION OUTPUT ;
    USE SIGNAL ;
    PORT
      LAYER M4 ;
        RECT  17.064 18.672 17.256 18.696 ;
    END
  END do0[328]
  PIN do0[329]
    DIRECTION OUTPUT ;
    USE SIGNAL ;
    PORT
      LAYER M4 ;
        RECT  17.064 18.72 17.256 18.744 ;
    END
  END do0[329]
  PIN do0[32]
    DIRECTION OUTPUT ;
    USE SIGNAL ;
    PORT
      LAYER M4 ;
        RECT  17.064 4.464 17.256 4.488 ;
    END
  END do0[32]
  PIN do0[330]
    DIRECTION OUTPUT ;
    USE SIGNAL ;
    PORT
      LAYER M4 ;
        RECT  17.064 18.768 17.256 18.792 ;
    END
  END do0[330]
  PIN do0[331]
    DIRECTION OUTPUT ;
    USE SIGNAL ;
    PORT
      LAYER M4 ;
        RECT  17.064 18.816 17.256 18.84 ;
    END
  END do0[331]
  PIN do0[332]
    DIRECTION OUTPUT ;
    USE SIGNAL ;
    PORT
      LAYER M4 ;
        RECT  17.064 18.864 17.256 18.888 ;
    END
  END do0[332]
  PIN do0[333]
    DIRECTION OUTPUT ;
    USE SIGNAL ;
    PORT
      LAYER M4 ;
        RECT  17.064 18.912 17.256 18.936 ;
    END
  END do0[333]
  PIN do0[334]
    DIRECTION OUTPUT ;
    USE SIGNAL ;
    PORT
      LAYER M4 ;
        RECT  17.064 18.96 17.256 18.984 ;
    END
  END do0[334]
  PIN do0[335]
    DIRECTION OUTPUT ;
    USE SIGNAL ;
    PORT
      LAYER M4 ;
        RECT  17.064 19.008 17.256 19.032 ;
    END
  END do0[335]
  PIN do0[336]
    DIRECTION OUTPUT ;
    USE SIGNAL ;
    PORT
      LAYER M4 ;
        RECT  17.064 19.056 17.256 19.08 ;
    END
  END do0[336]
  PIN do0[337]
    DIRECTION OUTPUT ;
    USE SIGNAL ;
    PORT
      LAYER M4 ;
        RECT  17.064 19.104 17.256 19.128 ;
    END
  END do0[337]
  PIN do0[338]
    DIRECTION OUTPUT ;
    USE SIGNAL ;
    PORT
      LAYER M4 ;
        RECT  17.064 19.152 17.256 19.176 ;
    END
  END do0[338]
  PIN do0[339]
    DIRECTION OUTPUT ;
    USE SIGNAL ;
    PORT
      LAYER M4 ;
        RECT  17.064 19.2 17.256 19.224 ;
    END
  END do0[339]
  PIN do0[33]
    DIRECTION OUTPUT ;
    USE SIGNAL ;
    PORT
      LAYER M4 ;
        RECT  17.064 4.512 17.256 4.536 ;
    END
  END do0[33]
  PIN do0[340]
    DIRECTION OUTPUT ;
    USE SIGNAL ;
    PORT
      LAYER M4 ;
        RECT  17.064 19.248 17.256 19.272 ;
    END
  END do0[340]
  PIN do0[341]
    DIRECTION OUTPUT ;
    USE SIGNAL ;
    PORT
      LAYER M4 ;
        RECT  17.064 19.296 17.256 19.32 ;
    END
  END do0[341]
  PIN do0[342]
    DIRECTION OUTPUT ;
    USE SIGNAL ;
    PORT
      LAYER M4 ;
        RECT  17.064 19.344 17.256 19.368 ;
    END
  END do0[342]
  PIN do0[343]
    DIRECTION OUTPUT ;
    USE SIGNAL ;
    PORT
      LAYER M4 ;
        RECT  17.064 19.392 17.256 19.416 ;
    END
  END do0[343]
  PIN do0[344]
    DIRECTION OUTPUT ;
    USE SIGNAL ;
    PORT
      LAYER M4 ;
        RECT  17.064 19.44 17.256 19.464 ;
    END
  END do0[344]
  PIN do0[345]
    DIRECTION OUTPUT ;
    USE SIGNAL ;
    PORT
      LAYER M4 ;
        RECT  17.064 19.488 17.256 19.512 ;
    END
  END do0[345]
  PIN do0[346]
    DIRECTION OUTPUT ;
    USE SIGNAL ;
    PORT
      LAYER M4 ;
        RECT  17.064 19.536 17.256 19.56 ;
    END
  END do0[346]
  PIN do0[347]
    DIRECTION OUTPUT ;
    USE SIGNAL ;
    PORT
      LAYER M4 ;
        RECT  17.064 19.584 17.256 19.608 ;
    END
  END do0[347]
  PIN do0[348]
    DIRECTION OUTPUT ;
    USE SIGNAL ;
    PORT
      LAYER M4 ;
        RECT  17.064 19.632 17.256 19.656 ;
    END
  END do0[348]
  PIN do0[349]
    DIRECTION OUTPUT ;
    USE SIGNAL ;
    PORT
      LAYER M4 ;
        RECT  17.064 19.68 17.256 19.704 ;
    END
  END do0[349]
  PIN do0[34]
    DIRECTION OUTPUT ;
    USE SIGNAL ;
    PORT
      LAYER M4 ;
        RECT  17.064 4.56 17.256 4.584 ;
    END
  END do0[34]
  PIN do0[350]
    DIRECTION OUTPUT ;
    USE SIGNAL ;
    PORT
      LAYER M4 ;
        RECT  17.064 19.728 17.256 19.752 ;
    END
  END do0[350]
  PIN do0[351]
    DIRECTION OUTPUT ;
    USE SIGNAL ;
    PORT
      LAYER M4 ;
        RECT  17.064 19.776 17.256 19.8 ;
    END
  END do0[351]
  PIN do0[352]
    DIRECTION OUTPUT ;
    USE SIGNAL ;
    PORT
      LAYER M4 ;
        RECT  17.064 19.824 17.256 19.848 ;
    END
  END do0[352]
  PIN do0[353]
    DIRECTION OUTPUT ;
    USE SIGNAL ;
    PORT
      LAYER M4 ;
        RECT  17.064 19.872 17.256 19.896 ;
    END
  END do0[353]
  PIN do0[354]
    DIRECTION OUTPUT ;
    USE SIGNAL ;
    PORT
      LAYER M4 ;
        RECT  17.064 19.92 17.256 19.944 ;
    END
  END do0[354]
  PIN do0[355]
    DIRECTION OUTPUT ;
    USE SIGNAL ;
    PORT
      LAYER M4 ;
        RECT  17.064 19.968 17.256 19.992 ;
    END
  END do0[355]
  PIN do0[356]
    DIRECTION OUTPUT ;
    USE SIGNAL ;
    PORT
      LAYER M4 ;
        RECT  17.064 20.016 17.256 20.04 ;
    END
  END do0[356]
  PIN do0[357]
    DIRECTION OUTPUT ;
    USE SIGNAL ;
    PORT
      LAYER M4 ;
        RECT  17.064 20.064 17.256 20.088 ;
    END
  END do0[357]
  PIN do0[358]
    DIRECTION OUTPUT ;
    USE SIGNAL ;
    PORT
      LAYER M4 ;
        RECT  17.064 20.112 17.256 20.136 ;
    END
  END do0[358]
  PIN do0[359]
    DIRECTION OUTPUT ;
    USE SIGNAL ;
    PORT
      LAYER M4 ;
        RECT  17.064 20.16 17.256 20.184 ;
    END
  END do0[359]
  PIN do0[35]
    DIRECTION OUTPUT ;
    USE SIGNAL ;
    PORT
      LAYER M4 ;
        RECT  17.064 4.608 17.256 4.632 ;
    END
  END do0[35]
  PIN do0[360]
    DIRECTION OUTPUT ;
    USE SIGNAL ;
    PORT
      LAYER M4 ;
        RECT  17.064 20.208 17.256 20.232 ;
    END
  END do0[360]
  PIN do0[361]
    DIRECTION OUTPUT ;
    USE SIGNAL ;
    PORT
      LAYER M4 ;
        RECT  17.064 20.256 17.256 20.28 ;
    END
  END do0[361]
  PIN do0[362]
    DIRECTION OUTPUT ;
    USE SIGNAL ;
    PORT
      LAYER M4 ;
        RECT  17.064 20.304 17.256 20.328 ;
    END
  END do0[362]
  PIN do0[363]
    DIRECTION OUTPUT ;
    USE SIGNAL ;
    PORT
      LAYER M4 ;
        RECT  17.064 20.352 17.256 20.376 ;
    END
  END do0[363]
  PIN do0[364]
    DIRECTION OUTPUT ;
    USE SIGNAL ;
    PORT
      LAYER M4 ;
        RECT  17.064 20.4 17.256 20.424 ;
    END
  END do0[364]
  PIN do0[365]
    DIRECTION OUTPUT ;
    USE SIGNAL ;
    PORT
      LAYER M4 ;
        RECT  17.064 20.448 17.256 20.472 ;
    END
  END do0[365]
  PIN do0[366]
    DIRECTION OUTPUT ;
    USE SIGNAL ;
    PORT
      LAYER M4 ;
        RECT  17.064 20.496 17.256 20.52 ;
    END
  END do0[366]
  PIN do0[367]
    DIRECTION OUTPUT ;
    USE SIGNAL ;
    PORT
      LAYER M4 ;
        RECT  17.064 20.544 17.256 20.568 ;
    END
  END do0[367]
  PIN do0[368]
    DIRECTION OUTPUT ;
    USE SIGNAL ;
    PORT
      LAYER M4 ;
        RECT  17.064 20.592 17.256 20.616 ;
    END
  END do0[368]
  PIN do0[369]
    DIRECTION OUTPUT ;
    USE SIGNAL ;
    PORT
      LAYER M4 ;
        RECT  17.064 20.64 17.256 20.664 ;
    END
  END do0[369]
  PIN do0[36]
    DIRECTION OUTPUT ;
    USE SIGNAL ;
    PORT
      LAYER M4 ;
        RECT  17.064 4.656 17.256 4.68 ;
    END
  END do0[36]
  PIN do0[370]
    DIRECTION OUTPUT ;
    USE SIGNAL ;
    PORT
      LAYER M4 ;
        RECT  17.064 20.688 17.256 20.712 ;
    END
  END do0[370]
  PIN do0[371]
    DIRECTION OUTPUT ;
    USE SIGNAL ;
    PORT
      LAYER M4 ;
        RECT  17.064 20.736 17.256 20.76 ;
    END
  END do0[371]
  PIN do0[372]
    DIRECTION OUTPUT ;
    USE SIGNAL ;
    PORT
      LAYER M4 ;
        RECT  17.064 20.784 17.256 20.808 ;
    END
  END do0[372]
  PIN do0[373]
    DIRECTION OUTPUT ;
    USE SIGNAL ;
    PORT
      LAYER M4 ;
        RECT  17.064 20.832 17.256 20.856 ;
    END
  END do0[373]
  PIN do0[374]
    DIRECTION OUTPUT ;
    USE SIGNAL ;
    PORT
      LAYER M4 ;
        RECT  17.064 20.88 17.256 20.904 ;
    END
  END do0[374]
  PIN do0[375]
    DIRECTION OUTPUT ;
    USE SIGNAL ;
    PORT
      LAYER M4 ;
        RECT  17.064 20.928 17.256 20.952 ;
    END
  END do0[375]
  PIN do0[376]
    DIRECTION OUTPUT ;
    USE SIGNAL ;
    PORT
      LAYER M4 ;
        RECT  17.064 20.976 17.256 21 ;
    END
  END do0[376]
  PIN do0[377]
    DIRECTION OUTPUT ;
    USE SIGNAL ;
    PORT
      LAYER M4 ;
        RECT  17.064 21.024 17.256 21.048 ;
    END
  END do0[377]
  PIN do0[378]
    DIRECTION OUTPUT ;
    USE SIGNAL ;
    PORT
      LAYER M4 ;
        RECT  17.064 21.072 17.256 21.096 ;
    END
  END do0[378]
  PIN do0[379]
    DIRECTION OUTPUT ;
    USE SIGNAL ;
    PORT
      LAYER M4 ;
        RECT  17.064 21.12 17.256 21.144 ;
    END
  END do0[379]
  PIN do0[37]
    DIRECTION OUTPUT ;
    USE SIGNAL ;
    PORT
      LAYER M4 ;
        RECT  17.064 4.704 17.256 4.728 ;
    END
  END do0[37]
  PIN do0[380]
    DIRECTION OUTPUT ;
    USE SIGNAL ;
    PORT
      LAYER M4 ;
        RECT  17.064 21.168 17.256 21.192 ;
    END
  END do0[380]
  PIN do0[381]
    DIRECTION OUTPUT ;
    USE SIGNAL ;
    PORT
      LAYER M4 ;
        RECT  17.064 21.216 17.256 21.24 ;
    END
  END do0[381]
  PIN do0[382]
    DIRECTION OUTPUT ;
    USE SIGNAL ;
    PORT
      LAYER M4 ;
        RECT  17.064 21.264 17.256 21.288 ;
    END
  END do0[382]
  PIN do0[383]
    DIRECTION OUTPUT ;
    USE SIGNAL ;
    PORT
      LAYER M4 ;
        RECT  17.064 21.312 17.256 21.336 ;
    END
  END do0[383]
  PIN do0[384]
    DIRECTION OUTPUT ;
    USE SIGNAL ;
    PORT
      LAYER M4 ;
        RECT  17.064 21.36 17.256 21.384 ;
    END
  END do0[384]
  PIN do0[385]
    DIRECTION OUTPUT ;
    USE SIGNAL ;
    PORT
      LAYER M4 ;
        RECT  17.064 21.408 17.256 21.432 ;
    END
  END do0[385]
  PIN do0[386]
    DIRECTION OUTPUT ;
    USE SIGNAL ;
    PORT
      LAYER M4 ;
        RECT  17.064 21.456 17.256 21.48 ;
    END
  END do0[386]
  PIN do0[387]
    DIRECTION OUTPUT ;
    USE SIGNAL ;
    PORT
      LAYER M4 ;
        RECT  17.064 21.504 17.256 21.528 ;
    END
  END do0[387]
  PIN do0[388]
    DIRECTION OUTPUT ;
    USE SIGNAL ;
    PORT
      LAYER M4 ;
        RECT  17.064 21.552 17.256 21.576 ;
    END
  END do0[388]
  PIN do0[389]
    DIRECTION OUTPUT ;
    USE SIGNAL ;
    PORT
      LAYER M4 ;
        RECT  17.064 21.6 17.256 21.624 ;
    END
  END do0[389]
  PIN do0[38]
    DIRECTION OUTPUT ;
    USE SIGNAL ;
    PORT
      LAYER M4 ;
        RECT  17.064 4.752 17.256 4.776 ;
    END
  END do0[38]
  PIN do0[390]
    DIRECTION OUTPUT ;
    USE SIGNAL ;
    PORT
      LAYER M4 ;
        RECT  17.064 21.648 17.256 21.672 ;
    END
  END do0[390]
  PIN do0[391]
    DIRECTION OUTPUT ;
    USE SIGNAL ;
    PORT
      LAYER M4 ;
        RECT  17.064 21.696 17.256 21.72 ;
    END
  END do0[391]
  PIN do0[392]
    DIRECTION OUTPUT ;
    USE SIGNAL ;
    PORT
      LAYER M4 ;
        RECT  17.064 21.744 17.256 21.768 ;
    END
  END do0[392]
  PIN do0[393]
    DIRECTION OUTPUT ;
    USE SIGNAL ;
    PORT
      LAYER M4 ;
        RECT  17.064 21.792 17.256 21.816 ;
    END
  END do0[393]
  PIN do0[394]
    DIRECTION OUTPUT ;
    USE SIGNAL ;
    PORT
      LAYER M4 ;
        RECT  17.064 21.84 17.256 21.864 ;
    END
  END do0[394]
  PIN do0[395]
    DIRECTION OUTPUT ;
    USE SIGNAL ;
    PORT
      LAYER M4 ;
        RECT  17.064 21.888 17.256 21.912 ;
    END
  END do0[395]
  PIN do0[396]
    DIRECTION OUTPUT ;
    USE SIGNAL ;
    PORT
      LAYER M4 ;
        RECT  17.064 21.936 17.256 21.96 ;
    END
  END do0[396]
  PIN do0[397]
    DIRECTION OUTPUT ;
    USE SIGNAL ;
    PORT
      LAYER M4 ;
        RECT  17.064 21.984 17.256 22.008 ;
    END
  END do0[397]
  PIN do0[398]
    DIRECTION OUTPUT ;
    USE SIGNAL ;
    PORT
      LAYER M4 ;
        RECT  17.064 22.032 17.256 22.056 ;
    END
  END do0[398]
  PIN do0[399]
    DIRECTION OUTPUT ;
    USE SIGNAL ;
    PORT
      LAYER M4 ;
        RECT  17.064 22.08 17.256 22.104 ;
    END
  END do0[399]
  PIN do0[39]
    DIRECTION OUTPUT ;
    USE SIGNAL ;
    PORT
      LAYER M4 ;
        RECT  17.064 4.8 17.256 4.824 ;
    END
  END do0[39]
  PIN do0[3]
    DIRECTION OUTPUT ;
    USE SIGNAL ;
    PORT
      LAYER M4 ;
        RECT  17.064 3.072 17.256 3.096 ;
    END
  END do0[3]
  PIN do0[400]
    DIRECTION OUTPUT ;
    USE SIGNAL ;
    PORT
      LAYER M4 ;
        RECT  17.064 22.128 17.256 22.152 ;
    END
  END do0[400]
  PIN do0[401]
    DIRECTION OUTPUT ;
    USE SIGNAL ;
    PORT
      LAYER M4 ;
        RECT  17.064 22.176 17.256 22.2 ;
    END
  END do0[401]
  PIN do0[402]
    DIRECTION OUTPUT ;
    USE SIGNAL ;
    PORT
      LAYER M4 ;
        RECT  17.064 22.224 17.256 22.248 ;
    END
  END do0[402]
  PIN do0[403]
    DIRECTION OUTPUT ;
    USE SIGNAL ;
    PORT
      LAYER M4 ;
        RECT  17.064 22.272 17.256 22.296 ;
    END
  END do0[403]
  PIN do0[404]
    DIRECTION OUTPUT ;
    USE SIGNAL ;
    PORT
      LAYER M4 ;
        RECT  17.064 22.32 17.256 22.344 ;
    END
  END do0[404]
  PIN do0[405]
    DIRECTION OUTPUT ;
    USE SIGNAL ;
    PORT
      LAYER M4 ;
        RECT  17.064 22.368 17.256 22.392 ;
    END
  END do0[405]
  PIN do0[406]
    DIRECTION OUTPUT ;
    USE SIGNAL ;
    PORT
      LAYER M4 ;
        RECT  17.064 22.416 17.256 22.44 ;
    END
  END do0[406]
  PIN do0[407]
    DIRECTION OUTPUT ;
    USE SIGNAL ;
    PORT
      LAYER M4 ;
        RECT  17.064 22.464 17.256 22.488 ;
    END
  END do0[407]
  PIN do0[408]
    DIRECTION OUTPUT ;
    USE SIGNAL ;
    PORT
      LAYER M4 ;
        RECT  17.064 22.512 17.256 22.536 ;
    END
  END do0[408]
  PIN do0[409]
    DIRECTION OUTPUT ;
    USE SIGNAL ;
    PORT
      LAYER M4 ;
        RECT  17.064 22.56 17.256 22.584 ;
    END
  END do0[409]
  PIN do0[40]
    DIRECTION OUTPUT ;
    USE SIGNAL ;
    PORT
      LAYER M4 ;
        RECT  17.064 4.848 17.256 4.872 ;
    END
  END do0[40]
  PIN do0[410]
    DIRECTION OUTPUT ;
    USE SIGNAL ;
    PORT
      LAYER M4 ;
        RECT  17.064 22.608 17.256 22.632 ;
    END
  END do0[410]
  PIN do0[411]
    DIRECTION OUTPUT ;
    USE SIGNAL ;
    PORT
      LAYER M4 ;
        RECT  17.064 22.656 17.256 22.68 ;
    END
  END do0[411]
  PIN do0[412]
    DIRECTION OUTPUT ;
    USE SIGNAL ;
    PORT
      LAYER M4 ;
        RECT  17.064 22.704 17.256 22.728 ;
    END
  END do0[412]
  PIN do0[413]
    DIRECTION OUTPUT ;
    USE SIGNAL ;
    PORT
      LAYER M4 ;
        RECT  17.064 22.752 17.256 22.776 ;
    END
  END do0[413]
  PIN do0[414]
    DIRECTION OUTPUT ;
    USE SIGNAL ;
    PORT
      LAYER M4 ;
        RECT  17.064 22.8 17.256 22.824 ;
    END
  END do0[414]
  PIN do0[415]
    DIRECTION OUTPUT ;
    USE SIGNAL ;
    PORT
      LAYER M4 ;
        RECT  17.064 22.848 17.256 22.872 ;
    END
  END do0[415]
  PIN do0[416]
    DIRECTION OUTPUT ;
    USE SIGNAL ;
    PORT
      LAYER M4 ;
        RECT  17.064 22.896 17.256 22.92 ;
    END
  END do0[416]
  PIN do0[417]
    DIRECTION OUTPUT ;
    USE SIGNAL ;
    PORT
      LAYER M4 ;
        RECT  17.064 22.944 17.256 22.968 ;
    END
  END do0[417]
  PIN do0[418]
    DIRECTION OUTPUT ;
    USE SIGNAL ;
    PORT
      LAYER M4 ;
        RECT  17.064 22.992 17.256 23.016 ;
    END
  END do0[418]
  PIN do0[419]
    DIRECTION OUTPUT ;
    USE SIGNAL ;
    PORT
      LAYER M4 ;
        RECT  17.064 23.04 17.256 23.064 ;
    END
  END do0[419]
  PIN do0[41]
    DIRECTION OUTPUT ;
    USE SIGNAL ;
    PORT
      LAYER M4 ;
        RECT  17.064 4.896 17.256 4.92 ;
    END
  END do0[41]
  PIN do0[420]
    DIRECTION OUTPUT ;
    USE SIGNAL ;
    PORT
      LAYER M4 ;
        RECT  17.064 23.088 17.256 23.112 ;
    END
  END do0[420]
  PIN do0[421]
    DIRECTION OUTPUT ;
    USE SIGNAL ;
    PORT
      LAYER M4 ;
        RECT  17.064 23.136 17.256 23.16 ;
    END
  END do0[421]
  PIN do0[422]
    DIRECTION OUTPUT ;
    USE SIGNAL ;
    PORT
      LAYER M4 ;
        RECT  17.064 23.184 17.256 23.208 ;
    END
  END do0[422]
  PIN do0[423]
    DIRECTION OUTPUT ;
    USE SIGNAL ;
    PORT
      LAYER M4 ;
        RECT  17.064 23.232 17.256 23.256 ;
    END
  END do0[423]
  PIN do0[424]
    DIRECTION OUTPUT ;
    USE SIGNAL ;
    PORT
      LAYER M4 ;
        RECT  17.064 23.28 17.256 23.304 ;
    END
  END do0[424]
  PIN do0[425]
    DIRECTION OUTPUT ;
    USE SIGNAL ;
    PORT
      LAYER M4 ;
        RECT  17.064 23.328 17.256 23.352 ;
    END
  END do0[425]
  PIN do0[426]
    DIRECTION OUTPUT ;
    USE SIGNAL ;
    PORT
      LAYER M4 ;
        RECT  17.064 23.376 17.256 23.4 ;
    END
  END do0[426]
  PIN do0[427]
    DIRECTION OUTPUT ;
    USE SIGNAL ;
    PORT
      LAYER M4 ;
        RECT  17.064 23.424 17.256 23.448 ;
    END
  END do0[427]
  PIN do0[428]
    DIRECTION OUTPUT ;
    USE SIGNAL ;
    PORT
      LAYER M4 ;
        RECT  17.064 23.472 17.256 23.496 ;
    END
  END do0[428]
  PIN do0[429]
    DIRECTION OUTPUT ;
    USE SIGNAL ;
    PORT
      LAYER M4 ;
        RECT  17.064 23.52 17.256 23.544 ;
    END
  END do0[429]
  PIN do0[42]
    DIRECTION OUTPUT ;
    USE SIGNAL ;
    PORT
      LAYER M4 ;
        RECT  17.064 4.944 17.256 4.968 ;
    END
  END do0[42]
  PIN do0[430]
    DIRECTION OUTPUT ;
    USE SIGNAL ;
    PORT
      LAYER M4 ;
        RECT  17.064 23.568 17.256 23.592 ;
    END
  END do0[430]
  PIN do0[431]
    DIRECTION OUTPUT ;
    USE SIGNAL ;
    PORT
      LAYER M4 ;
        RECT  17.064 23.616 17.256 23.64 ;
    END
  END do0[431]
  PIN do0[432]
    DIRECTION OUTPUT ;
    USE SIGNAL ;
    PORT
      LAYER M4 ;
        RECT  17.064 23.664 17.256 23.688 ;
    END
  END do0[432]
  PIN do0[433]
    DIRECTION OUTPUT ;
    USE SIGNAL ;
    PORT
      LAYER M4 ;
        RECT  17.064 23.712 17.256 23.736 ;
    END
  END do0[433]
  PIN do0[434]
    DIRECTION OUTPUT ;
    USE SIGNAL ;
    PORT
      LAYER M4 ;
        RECT  17.064 23.76 17.256 23.784 ;
    END
  END do0[434]
  PIN do0[435]
    DIRECTION OUTPUT ;
    USE SIGNAL ;
    PORT
      LAYER M4 ;
        RECT  17.064 23.808 17.256 23.832 ;
    END
  END do0[435]
  PIN do0[436]
    DIRECTION OUTPUT ;
    USE SIGNAL ;
    PORT
      LAYER M4 ;
        RECT  17.064 23.856 17.256 23.88 ;
    END
  END do0[436]
  PIN do0[437]
    DIRECTION OUTPUT ;
    USE SIGNAL ;
    PORT
      LAYER M4 ;
        RECT  17.064 23.904 17.256 23.928 ;
    END
  END do0[437]
  PIN do0[438]
    DIRECTION OUTPUT ;
    USE SIGNAL ;
    PORT
      LAYER M4 ;
        RECT  17.064 23.952 17.256 23.976 ;
    END
  END do0[438]
  PIN do0[439]
    DIRECTION OUTPUT ;
    USE SIGNAL ;
    PORT
      LAYER M4 ;
        RECT  17.064 24 17.256 24.024 ;
    END
  END do0[439]
  PIN do0[43]
    DIRECTION OUTPUT ;
    USE SIGNAL ;
    PORT
      LAYER M4 ;
        RECT  17.064 4.992 17.256 5.016 ;
    END
  END do0[43]
  PIN do0[440]
    DIRECTION OUTPUT ;
    USE SIGNAL ;
    PORT
      LAYER M4 ;
        RECT  17.064 24.048 17.256 24.072 ;
    END
  END do0[440]
  PIN do0[441]
    DIRECTION OUTPUT ;
    USE SIGNAL ;
    PORT
      LAYER M4 ;
        RECT  17.064 24.096 17.256 24.12 ;
    END
  END do0[441]
  PIN do0[442]
    DIRECTION OUTPUT ;
    USE SIGNAL ;
    PORT
      LAYER M4 ;
        RECT  17.064 24.144 17.256 24.168 ;
    END
  END do0[442]
  PIN do0[443]
    DIRECTION OUTPUT ;
    USE SIGNAL ;
    PORT
      LAYER M4 ;
        RECT  17.064 24.192 17.256 24.216 ;
    END
  END do0[443]
  PIN do0[444]
    DIRECTION OUTPUT ;
    USE SIGNAL ;
    PORT
      LAYER M4 ;
        RECT  17.064 24.24 17.256 24.264 ;
    END
  END do0[444]
  PIN do0[445]
    DIRECTION OUTPUT ;
    USE SIGNAL ;
    PORT
      LAYER M4 ;
        RECT  17.064 24.288 17.256 24.312 ;
    END
  END do0[445]
  PIN do0[446]
    DIRECTION OUTPUT ;
    USE SIGNAL ;
    PORT
      LAYER M4 ;
        RECT  17.064 24.336 17.256 24.36 ;
    END
  END do0[446]
  PIN do0[447]
    DIRECTION OUTPUT ;
    USE SIGNAL ;
    PORT
      LAYER M4 ;
        RECT  17.064 24.384 17.256 24.408 ;
    END
  END do0[447]
  PIN do0[448]
    DIRECTION OUTPUT ;
    USE SIGNAL ;
    PORT
      LAYER M4 ;
        RECT  17.064 24.432 17.256 24.456 ;
    END
  END do0[448]
  PIN do0[449]
    DIRECTION OUTPUT ;
    USE SIGNAL ;
    PORT
      LAYER M4 ;
        RECT  17.064 24.48 17.256 24.504 ;
    END
  END do0[449]
  PIN do0[44]
    DIRECTION OUTPUT ;
    USE SIGNAL ;
    PORT
      LAYER M4 ;
        RECT  17.064 5.04 17.256 5.064 ;
    END
  END do0[44]
  PIN do0[450]
    DIRECTION OUTPUT ;
    USE SIGNAL ;
    PORT
      LAYER M4 ;
        RECT  17.064 24.528 17.256 24.552 ;
    END
  END do0[450]
  PIN do0[451]
    DIRECTION OUTPUT ;
    USE SIGNAL ;
    PORT
      LAYER M4 ;
        RECT  17.064 24.576 17.256 24.6 ;
    END
  END do0[451]
  PIN do0[452]
    DIRECTION OUTPUT ;
    USE SIGNAL ;
    PORT
      LAYER M4 ;
        RECT  17.064 24.624 17.256 24.648 ;
    END
  END do0[452]
  PIN do0[453]
    DIRECTION OUTPUT ;
    USE SIGNAL ;
    PORT
      LAYER M4 ;
        RECT  17.064 24.672 17.256 24.696 ;
    END
  END do0[453]
  PIN do0[454]
    DIRECTION OUTPUT ;
    USE SIGNAL ;
    PORT
      LAYER M4 ;
        RECT  17.064 24.72 17.256 24.744 ;
    END
  END do0[454]
  PIN do0[455]
    DIRECTION OUTPUT ;
    USE SIGNAL ;
    PORT
      LAYER M4 ;
        RECT  17.064 24.768 17.256 24.792 ;
    END
  END do0[455]
  PIN do0[456]
    DIRECTION OUTPUT ;
    USE SIGNAL ;
    PORT
      LAYER M4 ;
        RECT  17.064 24.816 17.256 24.84 ;
    END
  END do0[456]
  PIN do0[457]
    DIRECTION OUTPUT ;
    USE SIGNAL ;
    PORT
      LAYER M4 ;
        RECT  17.064 24.864 17.256 24.888 ;
    END
  END do0[457]
  PIN do0[458]
    DIRECTION OUTPUT ;
    USE SIGNAL ;
    PORT
      LAYER M4 ;
        RECT  17.064 24.912 17.256 24.936 ;
    END
  END do0[458]
  PIN do0[459]
    DIRECTION OUTPUT ;
    USE SIGNAL ;
    PORT
      LAYER M4 ;
        RECT  17.064 24.96 17.256 24.984 ;
    END
  END do0[459]
  PIN do0[45]
    DIRECTION OUTPUT ;
    USE SIGNAL ;
    PORT
      LAYER M4 ;
        RECT  17.064 5.088 17.256 5.112 ;
    END
  END do0[45]
  PIN do0[460]
    DIRECTION OUTPUT ;
    USE SIGNAL ;
    PORT
      LAYER M4 ;
        RECT  17.064 25.008 17.256 25.032 ;
    END
  END do0[460]
  PIN do0[461]
    DIRECTION OUTPUT ;
    USE SIGNAL ;
    PORT
      LAYER M4 ;
        RECT  17.064 25.056 17.256 25.08 ;
    END
  END do0[461]
  PIN do0[462]
    DIRECTION OUTPUT ;
    USE SIGNAL ;
    PORT
      LAYER M4 ;
        RECT  17.064 25.104 17.256 25.128 ;
    END
  END do0[462]
  PIN do0[463]
    DIRECTION OUTPUT ;
    USE SIGNAL ;
    PORT
      LAYER M4 ;
        RECT  17.064 25.152 17.256 25.176 ;
    END
  END do0[463]
  PIN do0[464]
    DIRECTION OUTPUT ;
    USE SIGNAL ;
    PORT
      LAYER M4 ;
        RECT  17.064 25.2 17.256 25.224 ;
    END
  END do0[464]
  PIN do0[465]
    DIRECTION OUTPUT ;
    USE SIGNAL ;
    PORT
      LAYER M4 ;
        RECT  17.064 25.248 17.256 25.272 ;
    END
  END do0[465]
  PIN do0[466]
    DIRECTION OUTPUT ;
    USE SIGNAL ;
    PORT
      LAYER M4 ;
        RECT  17.064 25.296 17.256 25.32 ;
    END
  END do0[466]
  PIN do0[467]
    DIRECTION OUTPUT ;
    USE SIGNAL ;
    PORT
      LAYER M4 ;
        RECT  17.064 25.344 17.256 25.368 ;
    END
  END do0[467]
  PIN do0[468]
    DIRECTION OUTPUT ;
    USE SIGNAL ;
    PORT
      LAYER M4 ;
        RECT  17.064 25.392 17.256 25.416 ;
    END
  END do0[468]
  PIN do0[469]
    DIRECTION OUTPUT ;
    USE SIGNAL ;
    PORT
      LAYER M4 ;
        RECT  17.064 25.44 17.256 25.464 ;
    END
  END do0[469]
  PIN do0[46]
    DIRECTION OUTPUT ;
    USE SIGNAL ;
    PORT
      LAYER M4 ;
        RECT  17.064 5.136 17.256 5.16 ;
    END
  END do0[46]
  PIN do0[470]
    DIRECTION OUTPUT ;
    USE SIGNAL ;
    PORT
      LAYER M4 ;
        RECT  17.064 25.488 17.256 25.512 ;
    END
  END do0[470]
  PIN do0[471]
    DIRECTION OUTPUT ;
    USE SIGNAL ;
    PORT
      LAYER M4 ;
        RECT  17.064 25.536 17.256 25.56 ;
    END
  END do0[471]
  PIN do0[472]
    DIRECTION OUTPUT ;
    USE SIGNAL ;
    PORT
      LAYER M4 ;
        RECT  17.064 25.584 17.256 25.608 ;
    END
  END do0[472]
  PIN do0[473]
    DIRECTION OUTPUT ;
    USE SIGNAL ;
    PORT
      LAYER M4 ;
        RECT  17.064 25.632 17.256 25.656 ;
    END
  END do0[473]
  PIN do0[474]
    DIRECTION OUTPUT ;
    USE SIGNAL ;
    PORT
      LAYER M4 ;
        RECT  17.064 25.68 17.256 25.704 ;
    END
  END do0[474]
  PIN do0[475]
    DIRECTION OUTPUT ;
    USE SIGNAL ;
    PORT
      LAYER M4 ;
        RECT  17.064 25.728 17.256 25.752 ;
    END
  END do0[475]
  PIN do0[476]
    DIRECTION OUTPUT ;
    USE SIGNAL ;
    PORT
      LAYER M4 ;
        RECT  17.064 25.776 17.256 25.8 ;
    END
  END do0[476]
  PIN do0[477]
    DIRECTION OUTPUT ;
    USE SIGNAL ;
    PORT
      LAYER M4 ;
        RECT  17.064 25.824 17.256 25.848 ;
    END
  END do0[477]
  PIN do0[478]
    DIRECTION OUTPUT ;
    USE SIGNAL ;
    PORT
      LAYER M4 ;
        RECT  17.064 25.872 17.256 25.896 ;
    END
  END do0[478]
  PIN do0[479]
    DIRECTION OUTPUT ;
    USE SIGNAL ;
    PORT
      LAYER M4 ;
        RECT  17.064 25.92 17.256 25.944 ;
    END
  END do0[479]
  PIN do0[47]
    DIRECTION OUTPUT ;
    USE SIGNAL ;
    PORT
      LAYER M4 ;
        RECT  17.064 5.184 17.256 5.208 ;
    END
  END do0[47]
  PIN do0[480]
    DIRECTION OUTPUT ;
    USE SIGNAL ;
    PORT
      LAYER M4 ;
        RECT  17.064 25.968 17.256 25.992 ;
    END
  END do0[480]
  PIN do0[481]
    DIRECTION OUTPUT ;
    USE SIGNAL ;
    PORT
      LAYER M4 ;
        RECT  17.064 26.016 17.256 26.04 ;
    END
  END do0[481]
  PIN do0[482]
    DIRECTION OUTPUT ;
    USE SIGNAL ;
    PORT
      LAYER M4 ;
        RECT  17.064 26.064 17.256 26.088 ;
    END
  END do0[482]
  PIN do0[483]
    DIRECTION OUTPUT ;
    USE SIGNAL ;
    PORT
      LAYER M4 ;
        RECT  17.064 26.112 17.256 26.136 ;
    END
  END do0[483]
  PIN do0[484]
    DIRECTION OUTPUT ;
    USE SIGNAL ;
    PORT
      LAYER M4 ;
        RECT  17.064 26.16 17.256 26.184 ;
    END
  END do0[484]
  PIN do0[485]
    DIRECTION OUTPUT ;
    USE SIGNAL ;
    PORT
      LAYER M4 ;
        RECT  17.064 26.208 17.256 26.232 ;
    END
  END do0[485]
  PIN do0[486]
    DIRECTION OUTPUT ;
    USE SIGNAL ;
    PORT
      LAYER M4 ;
        RECT  17.064 26.256 17.256 26.28 ;
    END
  END do0[486]
  PIN do0[487]
    DIRECTION OUTPUT ;
    USE SIGNAL ;
    PORT
      LAYER M4 ;
        RECT  17.064 26.304 17.256 26.328 ;
    END
  END do0[487]
  PIN do0[488]
    DIRECTION OUTPUT ;
    USE SIGNAL ;
    PORT
      LAYER M4 ;
        RECT  17.064 26.352 17.256 26.376 ;
    END
  END do0[488]
  PIN do0[489]
    DIRECTION OUTPUT ;
    USE SIGNAL ;
    PORT
      LAYER M4 ;
        RECT  17.064 26.4 17.256 26.424 ;
    END
  END do0[489]
  PIN do0[48]
    DIRECTION OUTPUT ;
    USE SIGNAL ;
    PORT
      LAYER M4 ;
        RECT  17.064 5.232 17.256 5.256 ;
    END
  END do0[48]
  PIN do0[490]
    DIRECTION OUTPUT ;
    USE SIGNAL ;
    PORT
      LAYER M4 ;
        RECT  17.064 26.448 17.256 26.472 ;
    END
  END do0[490]
  PIN do0[491]
    DIRECTION OUTPUT ;
    USE SIGNAL ;
    PORT
      LAYER M4 ;
        RECT  17.064 26.496 17.256 26.52 ;
    END
  END do0[491]
  PIN do0[492]
    DIRECTION OUTPUT ;
    USE SIGNAL ;
    PORT
      LAYER M4 ;
        RECT  17.064 26.544 17.256 26.568 ;
    END
  END do0[492]
  PIN do0[493]
    DIRECTION OUTPUT ;
    USE SIGNAL ;
    PORT
      LAYER M4 ;
        RECT  17.064 26.592 17.256 26.616 ;
    END
  END do0[493]
  PIN do0[494]
    DIRECTION OUTPUT ;
    USE SIGNAL ;
    PORT
      LAYER M4 ;
        RECT  17.064 26.64 17.256 26.664 ;
    END
  END do0[494]
  PIN do0[495]
    DIRECTION OUTPUT ;
    USE SIGNAL ;
    PORT
      LAYER M4 ;
        RECT  17.064 26.688 17.256 26.712 ;
    END
  END do0[495]
  PIN do0[496]
    DIRECTION OUTPUT ;
    USE SIGNAL ;
    PORT
      LAYER M4 ;
        RECT  17.064 26.736 17.256 26.76 ;
    END
  END do0[496]
  PIN do0[497]
    DIRECTION OUTPUT ;
    USE SIGNAL ;
    PORT
      LAYER M4 ;
        RECT  17.064 26.784 17.256 26.808 ;
    END
  END do0[497]
  PIN do0[498]
    DIRECTION OUTPUT ;
    USE SIGNAL ;
    PORT
      LAYER M4 ;
        RECT  17.064 26.832 17.256 26.856 ;
    END
  END do0[498]
  PIN do0[499]
    DIRECTION OUTPUT ;
    USE SIGNAL ;
    PORT
      LAYER M4 ;
        RECT  17.064 26.88 17.256 26.904 ;
    END
  END do0[499]
  PIN do0[49]
    DIRECTION OUTPUT ;
    USE SIGNAL ;
    PORT
      LAYER M4 ;
        RECT  17.064 5.28 17.256 5.304 ;
    END
  END do0[49]
  PIN do0[4]
    DIRECTION OUTPUT ;
    USE SIGNAL ;
    PORT
      LAYER M4 ;
        RECT  17.064 3.12 17.256 3.144 ;
    END
  END do0[4]
  PIN do0[500]
    DIRECTION OUTPUT ;
    USE SIGNAL ;
    PORT
      LAYER M4 ;
        RECT  17.064 26.928 17.256 26.952 ;
    END
  END do0[500]
  PIN do0[501]
    DIRECTION OUTPUT ;
    USE SIGNAL ;
    PORT
      LAYER M4 ;
        RECT  17.064 26.976 17.256 27 ;
    END
  END do0[501]
  PIN do0[502]
    DIRECTION OUTPUT ;
    USE SIGNAL ;
    PORT
      LAYER M4 ;
        RECT  17.064 27.024 17.256 27.048 ;
    END
  END do0[502]
  PIN do0[503]
    DIRECTION OUTPUT ;
    USE SIGNAL ;
    PORT
      LAYER M4 ;
        RECT  17.064 27.072 17.256 27.096 ;
    END
  END do0[503]
  PIN do0[504]
    DIRECTION OUTPUT ;
    USE SIGNAL ;
    PORT
      LAYER M4 ;
        RECT  17.064 27.12 17.256 27.144 ;
    END
  END do0[504]
  PIN do0[505]
    DIRECTION OUTPUT ;
    USE SIGNAL ;
    PORT
      LAYER M4 ;
        RECT  17.064 27.168 17.256 27.192 ;
    END
  END do0[505]
  PIN do0[506]
    DIRECTION OUTPUT ;
    USE SIGNAL ;
    PORT
      LAYER M4 ;
        RECT  17.064 27.216 17.256 27.24 ;
    END
  END do0[506]
  PIN do0[507]
    DIRECTION OUTPUT ;
    USE SIGNAL ;
    PORT
      LAYER M4 ;
        RECT  17.064 27.264 17.256 27.288 ;
    END
  END do0[507]
  PIN do0[508]
    DIRECTION OUTPUT ;
    USE SIGNAL ;
    PORT
      LAYER M4 ;
        RECT  17.064 27.312 17.256 27.336 ;
    END
  END do0[508]
  PIN do0[509]
    DIRECTION OUTPUT ;
    USE SIGNAL ;
    PORT
      LAYER M4 ;
        RECT  17.064 27.36 17.256 27.384 ;
    END
  END do0[509]
  PIN do0[50]
    DIRECTION OUTPUT ;
    USE SIGNAL ;
    PORT
      LAYER M4 ;
        RECT  17.064 5.328 17.256 5.352 ;
    END
  END do0[50]
  PIN do0[510]
    DIRECTION OUTPUT ;
    USE SIGNAL ;
    PORT
      LAYER M4 ;
        RECT  17.064 27.408 17.256 27.432 ;
    END
  END do0[510]
  PIN do0[511]
    DIRECTION OUTPUT ;
    USE SIGNAL ;
    PORT
      LAYER M4 ;
        RECT  17.064 27.456 17.256 27.48 ;
    END
  END do0[511]
  PIN do0[51]
    DIRECTION OUTPUT ;
    USE SIGNAL ;
    PORT
      LAYER M4 ;
        RECT  17.064 5.376 17.256 5.4 ;
    END
  END do0[51]
  PIN do0[52]
    DIRECTION OUTPUT ;
    USE SIGNAL ;
    PORT
      LAYER M4 ;
        RECT  17.064 5.424 17.256 5.448 ;
    END
  END do0[52]
  PIN do0[53]
    DIRECTION OUTPUT ;
    USE SIGNAL ;
    PORT
      LAYER M4 ;
        RECT  17.064 5.472 17.256 5.496 ;
    END
  END do0[53]
  PIN do0[54]
    DIRECTION OUTPUT ;
    USE SIGNAL ;
    PORT
      LAYER M4 ;
        RECT  17.064 5.52 17.256 5.544 ;
    END
  END do0[54]
  PIN do0[55]
    DIRECTION OUTPUT ;
    USE SIGNAL ;
    PORT
      LAYER M4 ;
        RECT  17.064 5.568 17.256 5.592 ;
    END
  END do0[55]
  PIN do0[56]
    DIRECTION OUTPUT ;
    USE SIGNAL ;
    PORT
      LAYER M4 ;
        RECT  17.064 5.616 17.256 5.64 ;
    END
  END do0[56]
  PIN do0[57]
    DIRECTION OUTPUT ;
    USE SIGNAL ;
    PORT
      LAYER M4 ;
        RECT  17.064 5.664 17.256 5.688 ;
    END
  END do0[57]
  PIN do0[58]
    DIRECTION OUTPUT ;
    USE SIGNAL ;
    PORT
      LAYER M4 ;
        RECT  17.064 5.712 17.256 5.736 ;
    END
  END do0[58]
  PIN do0[59]
    DIRECTION OUTPUT ;
    USE SIGNAL ;
    PORT
      LAYER M4 ;
        RECT  17.064 5.76 17.256 5.784 ;
    END
  END do0[59]
  PIN do0[5]
    DIRECTION OUTPUT ;
    USE SIGNAL ;
    PORT
      LAYER M4 ;
        RECT  17.064 3.168 17.256 3.192 ;
    END
  END do0[5]
  PIN do0[60]
    DIRECTION OUTPUT ;
    USE SIGNAL ;
    PORT
      LAYER M4 ;
        RECT  17.064 5.808 17.256 5.832 ;
    END
  END do0[60]
  PIN do0[61]
    DIRECTION OUTPUT ;
    USE SIGNAL ;
    PORT
      LAYER M4 ;
        RECT  17.064 5.856 17.256 5.88 ;
    END
  END do0[61]
  PIN do0[62]
    DIRECTION OUTPUT ;
    USE SIGNAL ;
    PORT
      LAYER M4 ;
        RECT  17.064 5.904 17.256 5.928 ;
    END
  END do0[62]
  PIN do0[63]
    DIRECTION OUTPUT ;
    USE SIGNAL ;
    PORT
      LAYER M4 ;
        RECT  17.064 5.952 17.256 5.976 ;
    END
  END do0[63]
  PIN do0[64]
    DIRECTION OUTPUT ;
    USE SIGNAL ;
    PORT
      LAYER M4 ;
        RECT  17.064 6 17.256 6.024 ;
    END
  END do0[64]
  PIN do0[65]
    DIRECTION OUTPUT ;
    USE SIGNAL ;
    PORT
      LAYER M4 ;
        RECT  17.064 6.048 17.256 6.072 ;
    END
  END do0[65]
  PIN do0[66]
    DIRECTION OUTPUT ;
    USE SIGNAL ;
    PORT
      LAYER M4 ;
        RECT  17.064 6.096 17.256 6.12 ;
    END
  END do0[66]
  PIN do0[67]
    DIRECTION OUTPUT ;
    USE SIGNAL ;
    PORT
      LAYER M4 ;
        RECT  17.064 6.144 17.256 6.168 ;
    END
  END do0[67]
  PIN do0[68]
    DIRECTION OUTPUT ;
    USE SIGNAL ;
    PORT
      LAYER M4 ;
        RECT  17.064 6.192 17.256 6.216 ;
    END
  END do0[68]
  PIN do0[69]
    DIRECTION OUTPUT ;
    USE SIGNAL ;
    PORT
      LAYER M4 ;
        RECT  17.064 6.24 17.256 6.264 ;
    END
  END do0[69]
  PIN do0[6]
    DIRECTION OUTPUT ;
    USE SIGNAL ;
    PORT
      LAYER M4 ;
        RECT  17.064 3.216 17.256 3.24 ;
    END
  END do0[6]
  PIN do0[70]
    DIRECTION OUTPUT ;
    USE SIGNAL ;
    PORT
      LAYER M4 ;
        RECT  17.064 6.288 17.256 6.312 ;
    END
  END do0[70]
  PIN do0[71]
    DIRECTION OUTPUT ;
    USE SIGNAL ;
    PORT
      LAYER M4 ;
        RECT  17.064 6.336 17.256 6.36 ;
    END
  END do0[71]
  PIN do0[72]
    DIRECTION OUTPUT ;
    USE SIGNAL ;
    PORT
      LAYER M4 ;
        RECT  17.064 6.384 17.256 6.408 ;
    END
  END do0[72]
  PIN do0[73]
    DIRECTION OUTPUT ;
    USE SIGNAL ;
    PORT
      LAYER M4 ;
        RECT  17.064 6.432 17.256 6.456 ;
    END
  END do0[73]
  PIN do0[74]
    DIRECTION OUTPUT ;
    USE SIGNAL ;
    PORT
      LAYER M4 ;
        RECT  17.064 6.48 17.256 6.504 ;
    END
  END do0[74]
  PIN do0[75]
    DIRECTION OUTPUT ;
    USE SIGNAL ;
    PORT
      LAYER M4 ;
        RECT  17.064 6.528 17.256 6.552 ;
    END
  END do0[75]
  PIN do0[76]
    DIRECTION OUTPUT ;
    USE SIGNAL ;
    PORT
      LAYER M4 ;
        RECT  17.064 6.576 17.256 6.6 ;
    END
  END do0[76]
  PIN do0[77]
    DIRECTION OUTPUT ;
    USE SIGNAL ;
    PORT
      LAYER M4 ;
        RECT  17.064 6.624 17.256 6.648 ;
    END
  END do0[77]
  PIN do0[78]
    DIRECTION OUTPUT ;
    USE SIGNAL ;
    PORT
      LAYER M4 ;
        RECT  17.064 6.672 17.256 6.696 ;
    END
  END do0[78]
  PIN do0[79]
    DIRECTION OUTPUT ;
    USE SIGNAL ;
    PORT
      LAYER M4 ;
        RECT  17.064 6.72 17.256 6.744 ;
    END
  END do0[79]
  PIN do0[7]
    DIRECTION OUTPUT ;
    USE SIGNAL ;
    PORT
      LAYER M4 ;
        RECT  17.064 3.264 17.256 3.288 ;
    END
  END do0[7]
  PIN do0[80]
    DIRECTION OUTPUT ;
    USE SIGNAL ;
    PORT
      LAYER M4 ;
        RECT  17.064 6.768 17.256 6.792 ;
    END
  END do0[80]
  PIN do0[81]
    DIRECTION OUTPUT ;
    USE SIGNAL ;
    PORT
      LAYER M4 ;
        RECT  17.064 6.816 17.256 6.84 ;
    END
  END do0[81]
  PIN do0[82]
    DIRECTION OUTPUT ;
    USE SIGNAL ;
    PORT
      LAYER M4 ;
        RECT  17.064 6.864 17.256 6.888 ;
    END
  END do0[82]
  PIN do0[83]
    DIRECTION OUTPUT ;
    USE SIGNAL ;
    PORT
      LAYER M4 ;
        RECT  17.064 6.912 17.256 6.936 ;
    END
  END do0[83]
  PIN do0[84]
    DIRECTION OUTPUT ;
    USE SIGNAL ;
    PORT
      LAYER M4 ;
        RECT  17.064 6.96 17.256 6.984 ;
    END
  END do0[84]
  PIN do0[85]
    DIRECTION OUTPUT ;
    USE SIGNAL ;
    PORT
      LAYER M4 ;
        RECT  17.064 7.008 17.256 7.032 ;
    END
  END do0[85]
  PIN do0[86]
    DIRECTION OUTPUT ;
    USE SIGNAL ;
    PORT
      LAYER M4 ;
        RECT  17.064 7.056 17.256 7.08 ;
    END
  END do0[86]
  PIN do0[87]
    DIRECTION OUTPUT ;
    USE SIGNAL ;
    PORT
      LAYER M4 ;
        RECT  17.064 7.104 17.256 7.128 ;
    END
  END do0[87]
  PIN do0[88]
    DIRECTION OUTPUT ;
    USE SIGNAL ;
    PORT
      LAYER M4 ;
        RECT  17.064 7.152 17.256 7.176 ;
    END
  END do0[88]
  PIN do0[89]
    DIRECTION OUTPUT ;
    USE SIGNAL ;
    PORT
      LAYER M4 ;
        RECT  17.064 7.2 17.256 7.224 ;
    END
  END do0[89]
  PIN do0[8]
    DIRECTION OUTPUT ;
    USE SIGNAL ;
    PORT
      LAYER M4 ;
        RECT  17.064 3.312 17.256 3.336 ;
    END
  END do0[8]
  PIN do0[90]
    DIRECTION OUTPUT ;
    USE SIGNAL ;
    PORT
      LAYER M4 ;
        RECT  17.064 7.248 17.256 7.272 ;
    END
  END do0[90]
  PIN do0[91]
    DIRECTION OUTPUT ;
    USE SIGNAL ;
    PORT
      LAYER M4 ;
        RECT  17.064 7.296 17.256 7.32 ;
    END
  END do0[91]
  PIN do0[92]
    DIRECTION OUTPUT ;
    USE SIGNAL ;
    PORT
      LAYER M4 ;
        RECT  17.064 7.344 17.256 7.368 ;
    END
  END do0[92]
  PIN do0[93]
    DIRECTION OUTPUT ;
    USE SIGNAL ;
    PORT
      LAYER M4 ;
        RECT  17.064 7.392 17.256 7.416 ;
    END
  END do0[93]
  PIN do0[94]
    DIRECTION OUTPUT ;
    USE SIGNAL ;
    PORT
      LAYER M4 ;
        RECT  17.064 7.44 17.256 7.464 ;
    END
  END do0[94]
  PIN do0[95]
    DIRECTION OUTPUT ;
    USE SIGNAL ;
    PORT
      LAYER M4 ;
        RECT  17.064 7.488 17.256 7.512 ;
    END
  END do0[95]
  PIN do0[96]
    DIRECTION OUTPUT ;
    USE SIGNAL ;
    PORT
      LAYER M4 ;
        RECT  17.064 7.536 17.256 7.56 ;
    END
  END do0[96]
  PIN do0[97]
    DIRECTION OUTPUT ;
    USE SIGNAL ;
    PORT
      LAYER M4 ;
        RECT  17.064 7.584 17.256 7.608 ;
    END
  END do0[97]
  PIN do0[98]
    DIRECTION OUTPUT ;
    USE SIGNAL ;
    PORT
      LAYER M4 ;
        RECT  17.064 7.632 17.256 7.656 ;
    END
  END do0[98]
  PIN do0[99]
    DIRECTION OUTPUT ;
    USE SIGNAL ;
    PORT
      LAYER M4 ;
        RECT  17.064 7.68 17.256 7.704 ;
    END
  END do0[99]
  PIN do0[9]
    DIRECTION OUTPUT ;
    USE SIGNAL ;
    PORT
      LAYER M4 ;
        RECT  17.064 3.36 17.256 3.384 ;
    END
  END do0[9]
  PIN fi0[0]
    DIRECTION INPUT ;
    USE SIGNAL ;
    PORT
      LAYER M4 ;
        RECT  0 2.736 0.192 2.76 ;
    END
  END fi0[0]
  PIN fo0[0]
    DIRECTION OUTPUT ;
    USE SIGNAL ;
    PORT
      LAYER M4 ;
        RECT  17.064 2.736 17.256 2.76 ;
    END
  END fo0[0]
  PIN VDD
    DIRECTION INOUT ;
    USE POWER ;
    PORT
      LAYER M7 ;
        RECT  6.256 0.531 6.544 29.439 ;
      LAYER M6 ;
        RECT  0 28.572 0.032 28.86 ;
        RECT  0 23.172 0.032 23.46 ;
        RECT  0 17.772 0.032 18.06 ;
        RECT  0 12.372 0.032 12.66 ;
        RECT  0 6.972 0.032 7.26 ;
        RECT  0 1.572 0.032 1.86 ;
      LAYER M2 ;
        RECT  0 29.421 0.018 29.439 ;
        RECT  0 28.881 0.018 28.899 ;
        RECT  0 28.341 0.018 28.359 ;
        RECT  0 27.801 0.018 27.819 ;
        RECT  0 27.261 0.018 27.279 ;
        RECT  0 26.721 0.018 26.739 ;
        RECT  0 26.181 0.018 26.199 ;
        RECT  0 25.641 0.018 25.659 ;
        RECT  0 25.101 0.018 25.119 ;
        RECT  0 24.561 0.018 24.579 ;
        RECT  0 24.021 0.018 24.039 ;
        RECT  0 23.481 0.018 23.499 ;
        RECT  0 22.941 0.018 22.959 ;
        RECT  0 22.401 0.018 22.419 ;
        RECT  0 21.861 0.018 21.879 ;
        RECT  0 21.321 0.018 21.339 ;
        RECT  0 20.781 0.018 20.799 ;
        RECT  0 20.241 0.018 20.259 ;
        RECT  0 19.701 0.018 19.719 ;
        RECT  0 19.161 0.018 19.179 ;
        RECT  0 18.621 0.018 18.639 ;
        RECT  0 18.081 0.018 18.099 ;
        RECT  0 17.541 0.018 17.559 ;
        RECT  0 17.001 0.018 17.019 ;
        RECT  0 16.461 0.018 16.479 ;
        RECT  0 15.921 0.018 15.939 ;
        RECT  0 15.381 0.018 15.399 ;
        RECT  0 14.841 0.018 14.859 ;
        RECT  0 14.301 0.018 14.319 ;
        RECT  0 13.761 0.018 13.779 ;
        RECT  0 13.221 0.018 13.239 ;
        RECT  0 12.681 0.018 12.699 ;
        RECT  0 12.141 0.018 12.159 ;
        RECT  0 11.601 0.018 11.619 ;
        RECT  0 11.061 0.018 11.079 ;
        RECT  0 10.521 0.018 10.539 ;
        RECT  0 9.981 0.018 9.999 ;
        RECT  0 9.441 0.018 9.459 ;
        RECT  0 8.901 0.018 8.919 ;
        RECT  0 8.361 0.018 8.379 ;
        RECT  0 7.821 0.018 7.839 ;
        RECT  0 7.281 0.018 7.299 ;
        RECT  0 6.741 0.018 6.759 ;
        RECT  0 6.201 0.018 6.219 ;
        RECT  0 5.661 0.018 5.679 ;
        RECT  0 5.121 0.018 5.139 ;
        RECT  0 4.581 0.018 4.599 ;
        RECT  0 4.041 0.018 4.059 ;
        RECT  0 3.501 0.018 3.519 ;
        RECT  0 2.961 0.018 2.979 ;
        RECT  0 2.421 0.018 2.439 ;
        RECT  0 1.881 0.018 1.899 ;
        RECT  0 1.341 0.018 1.359 ;
        RECT  0 0.801 0.018 0.819 ;
      LAYER M1 ;
        RECT  0 29.421 0.018 29.439 ;
        RECT  0 28.881 0.018 28.899 ;
        RECT  0 28.341 0.018 28.359 ;
        RECT  0 27.801 0.018 27.819 ;
        RECT  0 27.261 0.018 27.279 ;
        RECT  0 26.721 0.018 26.739 ;
        RECT  0 26.181 0.018 26.199 ;
        RECT  0 25.641 0.018 25.659 ;
        RECT  0 25.101 0.018 25.119 ;
        RECT  0 24.561 0.018 24.579 ;
        RECT  0 24.021 0.018 24.039 ;
        RECT  0 23.481 0.018 23.499 ;
        RECT  0 22.941 0.018 22.959 ;
        RECT  0 22.401 0.018 22.419 ;
        RECT  0 21.861 0.018 21.879 ;
        RECT  0 21.321 0.018 21.339 ;
        RECT  0 20.781 0.018 20.799 ;
        RECT  0 20.241 0.018 20.259 ;
        RECT  0 19.701 0.018 19.719 ;
        RECT  0 19.161 0.018 19.179 ;
        RECT  0 18.621 0.018 18.639 ;
        RECT  0 18.081 0.018 18.099 ;
        RECT  0 17.541 0.018 17.559 ;
        RECT  0 17.001 0.018 17.019 ;
        RECT  0 16.461 0.018 16.479 ;
        RECT  0 15.921 0.018 15.939 ;
        RECT  0 15.381 0.018 15.399 ;
        RECT  0 14.841 0.018 14.859 ;
        RECT  0 14.301 0.018 14.319 ;
        RECT  0 13.761 0.018 13.779 ;
        RECT  0 13.221 0.018 13.239 ;
        RECT  0 12.681 0.018 12.699 ;
        RECT  0 12.141 0.018 12.159 ;
        RECT  0 11.601 0.018 11.619 ;
        RECT  0 11.061 0.018 11.079 ;
        RECT  0 10.521 0.018 10.539 ;
        RECT  0 9.981 0.018 9.999 ;
        RECT  0 9.441 0.018 9.459 ;
        RECT  0 8.901 0.018 8.919 ;
        RECT  0 8.361 0.018 8.379 ;
        RECT  0 7.821 0.018 7.839 ;
        RECT  0 7.281 0.018 7.299 ;
        RECT  0 6.741 0.018 6.759 ;
        RECT  0 6.201 0.018 6.219 ;
        RECT  0 5.661 0.018 5.679 ;
        RECT  0 5.121 0.018 5.139 ;
        RECT  0 4.581 0.018 4.599 ;
        RECT  0 4.041 0.018 4.059 ;
        RECT  0 3.501 0.018 3.519 ;
        RECT  0 2.961 0.018 2.979 ;
        RECT  0 2.421 0.018 2.439 ;
        RECT  0 1.881 0.018 1.899 ;
        RECT  0 1.341 0.018 1.359 ;
        RECT  0 0.801 0.018 0.819 ;
    END
  END VDD
  PIN VSS
    DIRECTION INOUT ;
    USE GROUND ;
    PORT
      LAYER M7 ;
        RECT  11.656 0.531 11.944 29.439 ;
        RECT  0.856 0.531 1.144 29.439 ;
      LAYER M6 ;
        RECT  0 27.996 0.032 28.284 ;
        RECT  0 22.596 0.032 22.884 ;
        RECT  0 17.196 0.032 17.484 ;
        RECT  0 11.796 0.032 12.084 ;
        RECT  0 6.396 0.032 6.684 ;
        RECT  0 0.996 0.032 1.284 ;
      LAYER M2 ;
        RECT  0 29.151 0.018 29.169 ;
        RECT  0 28.611 0.018 28.629 ;
        RECT  0 28.071 0.018 28.089 ;
        RECT  0 27.531 0.018 27.549 ;
        RECT  0 26.991 0.018 27.009 ;
        RECT  0 26.451 0.018 26.469 ;
        RECT  0 25.911 0.018 25.929 ;
        RECT  0 25.371 0.018 25.389 ;
        RECT  0 24.831 0.018 24.849 ;
        RECT  0 24.291 0.018 24.309 ;
        RECT  0 23.751 0.018 23.769 ;
        RECT  0 23.211 0.018 23.229 ;
        RECT  0 22.671 0.018 22.689 ;
        RECT  0 22.131 0.018 22.149 ;
        RECT  0 21.591 0.018 21.609 ;
        RECT  0 21.051 0.018 21.069 ;
        RECT  0 20.511 0.018 20.529 ;
        RECT  0 19.971 0.018 19.989 ;
        RECT  0 19.431 0.018 19.449 ;
        RECT  0 18.891 0.018 18.909 ;
        RECT  0 18.351 0.018 18.369 ;
        RECT  0 17.811 0.018 17.829 ;
        RECT  0 17.271 0.018 17.289 ;
        RECT  0 16.731 0.018 16.749 ;
        RECT  0 16.191 0.018 16.209 ;
        RECT  0 15.651 0.018 15.669 ;
        RECT  0 15.111 0.018 15.129 ;
        RECT  0 14.571 0.018 14.589 ;
        RECT  0 14.031 0.018 14.049 ;
        RECT  0 13.491 0.018 13.509 ;
        RECT  0 12.951 0.018 12.969 ;
        RECT  0 12.411 0.018 12.429 ;
        RECT  0 11.871 0.018 11.889 ;
        RECT  0 11.331 0.018 11.349 ;
        RECT  0 10.791 0.018 10.809 ;
        RECT  0 10.251 0.018 10.269 ;
        RECT  0 9.711 0.018 9.729 ;
        RECT  0 9.171 0.018 9.189 ;
        RECT  0 8.631 0.018 8.649 ;
        RECT  0 8.091 0.018 8.109 ;
        RECT  0 7.551 0.018 7.569 ;
        RECT  0 7.011 0.018 7.029 ;
        RECT  0 6.471 0.018 6.489 ;
        RECT  0 5.931 0.018 5.949 ;
        RECT  0 5.391 0.018 5.409 ;
        RECT  0 4.851 0.018 4.869 ;
        RECT  0 4.311 0.018 4.329 ;
        RECT  0 3.771 0.018 3.789 ;
        RECT  0 3.231 0.018 3.249 ;
        RECT  0 2.691 0.018 2.709 ;
        RECT  0 2.151 0.018 2.169 ;
        RECT  0 1.611 0.018 1.629 ;
        RECT  0 1.071 0.018 1.089 ;
        RECT  0 0.531 0.018 0.549 ;
      LAYER M1 ;
        RECT  0 29.151 0.018 29.169 ;
        RECT  0 28.611 0.018 28.629 ;
        RECT  0 28.071 0.018 28.089 ;
        RECT  0 27.531 0.018 27.549 ;
        RECT  0 26.991 0.018 27.009 ;
        RECT  0 26.451 0.018 26.469 ;
        RECT  0 25.911 0.018 25.929 ;
        RECT  0 25.371 0.018 25.389 ;
        RECT  0 24.831 0.018 24.849 ;
        RECT  0 24.291 0.018 24.309 ;
        RECT  0 23.751 0.018 23.769 ;
        RECT  0 23.211 0.018 23.229 ;
        RECT  0 22.671 0.018 22.689 ;
        RECT  0 22.131 0.018 22.149 ;
        RECT  0 21.591 0.018 21.609 ;
        RECT  0 21.051 0.018 21.069 ;
        RECT  0 20.511 0.018 20.529 ;
        RECT  0 19.971 0.018 19.989 ;
        RECT  0 19.431 0.018 19.449 ;
        RECT  0 18.891 0.018 18.909 ;
        RECT  0 18.351 0.018 18.369 ;
        RECT  0 17.811 0.018 17.829 ;
        RECT  0 17.271 0.018 17.289 ;
        RECT  0 16.731 0.018 16.749 ;
        RECT  0 16.191 0.018 16.209 ;
        RECT  0 15.651 0.018 15.669 ;
        RECT  0 15.111 0.018 15.129 ;
        RECT  0 14.571 0.018 14.589 ;
        RECT  0 14.031 0.018 14.049 ;
        RECT  0 13.491 0.018 13.509 ;
        RECT  0 12.951 0.018 12.969 ;
        RECT  0 12.411 0.018 12.429 ;
        RECT  0 11.871 0.018 11.889 ;
        RECT  0 11.331 0.018 11.349 ;
        RECT  0 10.791 0.018 10.809 ;
        RECT  0 10.251 0.018 10.269 ;
        RECT  0 9.711 0.018 9.729 ;
        RECT  0 9.171 0.018 9.189 ;
        RECT  0 8.631 0.018 8.649 ;
        RECT  0 8.091 0.018 8.109 ;
        RECT  0 7.551 0.018 7.569 ;
        RECT  0 7.011 0.018 7.029 ;
        RECT  0 6.471 0.018 6.489 ;
        RECT  0 5.931 0.018 5.949 ;
        RECT  0 5.391 0.018 5.409 ;
        RECT  0 4.851 0.018 4.869 ;
        RECT  0 4.311 0.018 4.329 ;
        RECT  0 3.771 0.018 3.789 ;
        RECT  0 3.231 0.018 3.249 ;
        RECT  0 2.691 0.018 2.709 ;
        RECT  0 2.151 0.018 2.169 ;
        RECT  0 1.611 0.018 1.629 ;
        RECT  0 1.071 0.018 1.089 ;
        RECT  0 0.531 0.018 0.549 ;
    END
  END VSS
  OBS
    LAYER RVTN ;
     RECT  0 0.54 17.226 0.675 ;
     RECT  0 0.945 17.226 1.215 ;
     RECT  0 1.485 17.226 1.755 ;
     RECT  0 2.025 17.226 2.295 ;
     RECT  0 2.565 17.226 2.835 ;
     RECT  0 3.105 17.226 3.375 ;
     RECT  0 3.645 17.226 3.915 ;
     RECT  0 4.185 17.226 4.455 ;
     RECT  0 4.725 17.226 4.995 ;
     RECT  0 5.265 17.226 5.535 ;
     RECT  0 5.805 17.226 6.075 ;
     RECT  0 6.345 17.226 6.615 ;
     RECT  0 6.885 17.226 7.155 ;
     RECT  0 7.425 17.226 7.695 ;
     RECT  0 7.965 17.226 8.235 ;
     RECT  0 8.505 17.226 8.775 ;
     RECT  0 9.045 17.226 9.315 ;
     RECT  0 9.585 17.226 9.855 ;
     RECT  0 10.125 17.226 10.395 ;
     RECT  0 10.665 17.226 10.935 ;
     RECT  0 11.205 17.226 11.475 ;
     RECT  0 11.745 17.226 12.015 ;
     RECT  0 12.285 17.226 12.555 ;
     RECT  0 12.825 17.226 13.095 ;
     RECT  0 13.365 17.226 13.635 ;
     RECT  0 13.905 17.226 14.175 ;
     RECT  0 14.445 17.226 14.715 ;
     RECT  0 14.985 17.226 15.255 ;
     RECT  0 15.525 17.226 15.795 ;
     RECT  0 16.065 17.226 16.335 ;
     RECT  0 16.605 17.226 16.875 ;
     RECT  0 17.145 17.226 17.415 ;
     RECT  0 17.685 17.226 17.955 ;
     RECT  0 18.225 17.226 18.495 ;
     RECT  0 18.765 17.226 19.035 ;
     RECT  0 19.305 17.226 19.575 ;
     RECT  0 19.845 17.226 20.115 ;
     RECT  0 20.385 17.226 20.655 ;
     RECT  0 20.925 17.226 21.195 ;
     RECT  0 21.465 17.226 21.735 ;
     RECT  0 22.005 17.226 22.275 ;
     RECT  0 22.545 17.226 22.815 ;
     RECT  0 23.085 17.226 23.355 ;
     RECT  0 23.625 17.226 23.895 ;
     RECT  0 24.165 17.226 24.435 ;
     RECT  0 24.705 17.226 24.975 ;
     RECT  0 25.245 17.226 25.515 ;
     RECT  0 25.785 17.226 26.055 ;
     RECT  0 26.325 17.226 26.595 ;
     RECT  0 26.865 17.226 27.135 ;
     RECT  0 27.405 17.226 27.675 ;
     RECT  0 27.945 17.226 28.215 ;
     RECT  0 28.485 17.226 28.755 ;
     RECT  0 29.025 17.226 29.295 ;
    LAYER RVTP ;
     RECT  0 0.675 17.226 0.945 ;
     RECT  0 1.215 17.226 1.485 ;
     RECT  0 1.755 17.226 2.025 ;
     RECT  0 2.295 17.226 2.565 ;
     RECT  0 2.835 17.226 3.105 ;
     RECT  0 3.375 17.226 3.645 ;
     RECT  0 3.915 17.226 4.185 ;
     RECT  0 4.455 17.226 4.725 ;
     RECT  0 4.995 17.226 5.265 ;
     RECT  0 5.535 17.226 5.805 ;
     RECT  0 6.075 17.226 6.345 ;
     RECT  0 6.615 17.226 6.885 ;
     RECT  0 7.155 17.226 7.425 ;
     RECT  0 7.695 17.226 7.965 ;
     RECT  0 8.235 17.226 8.505 ;
     RECT  0 8.775 17.226 9.045 ;
     RECT  0 9.315 17.226 9.585 ;
     RECT  0 9.855 17.226 10.125 ;
     RECT  0 10.395 17.226 10.665 ;
     RECT  0 10.935 17.226 11.205 ;
     RECT  0 11.475 17.226 11.745 ;
     RECT  0 12.015 17.226 12.285 ;
     RECT  0 12.555 17.226 12.825 ;
     RECT  0 13.095 17.226 13.365 ;
     RECT  0 13.635 17.226 13.905 ;
     RECT  0 14.175 17.226 14.445 ;
     RECT  0 14.715 17.226 14.985 ;
     RECT  0 15.255 17.226 15.525 ;
     RECT  0 15.795 17.226 16.065 ;
     RECT  0 16.335 17.226 16.605 ;
     RECT  0 16.875 17.226 17.145 ;
     RECT  0 17.415 17.226 17.685 ;
     RECT  0 17.955 17.226 18.225 ;
     RECT  0 18.495 17.226 18.765 ;
     RECT  0 19.035 17.226 19.305 ;
     RECT  0 19.575 17.226 19.845 ;
     RECT  0 20.115 17.226 20.385 ;
     RECT  0 20.655 17.226 20.925 ;
     RECT  0 21.195 17.226 21.465 ;
     RECT  0 21.735 17.226 22.005 ;
     RECT  0 22.275 17.226 22.545 ;
     RECT  0 22.815 17.226 23.085 ;
     RECT  0 23.355 17.226 23.625 ;
     RECT  0 23.895 17.226 24.165 ;
     RECT  0 24.435 17.226 24.705 ;
     RECT  0 24.975 17.226 25.245 ;
     RECT  0 25.515 17.226 25.785 ;
     RECT  0 26.055 17.226 26.325 ;
     RECT  0 26.595 17.226 26.865 ;
     RECT  0 27.135 17.226 27.405 ;
     RECT  0 27.675 17.226 27.945 ;
     RECT  0 28.215 17.226 28.485 ;
     RECT  0 28.755 17.226 29.025 ;
     RECT  0 29.295 17.226 29.43 ;
    LAYER M1 ;
     RECT  0 0.531 17.226 29.439 ;
    LAYER M2 ;
     RECT  0 0.531 17.226 29.439 ;
    LAYER M3 ;
     RECT  0.255 0.523 0.345 0.793 ;
     RECT  5.655 0.523 5.745 0.793 ;
     RECT  11.055 0.523 11.145 0.793 ;
     RECT  16.455 0.523 16.545 0.793 ;
     RECT  0.255 0.793 0.537 1.795 ;
     RECT  14.688 1.687 14.706 1.831 ;
     RECT  16.455 0.793 16.737 1.831 ;
     RECT  14.688 1.831 15.282 1.949 ;
     RECT  11.055 0.793 11.337 1.957 ;
     RECT  16.455 1.831 16.866 2.029 ;
     RECT  0.216 1.795 0.537 2.065 ;
     RECT  0.216 2.065 0.954 2.101 ;
     RECT  0.216 2.101 1.566 2.191 ;
     RECT  10.836 1.957 11.337 2.263 ;
     RECT  5.655 0.793 5.937 2.299 ;
     RECT  9.576 2.263 9.594 2.299 ;
     RECT  10.44 2.263 11.337 2.299 ;
     RECT  9 2.299 9.594 2.335 ;
     RECT  10.44 2.299 11.394 2.335 ;
     RECT  2.52 2.335 2.538 2.371 ;
     RECT  8.856 2.335 9.594 2.371 ;
     RECT  10.368 2.335 11.394 2.371 ;
     RECT  5.655 2.299 6.93 2.395 ;
     RECT  13.68 2.335 13.77 2.443 ;
     RECT  15.552 2.029 16.866 2.497 ;
     RECT  2.52 2.371 2.934 2.533 ;
     RECT  13.356 2.443 13.77 2.533 ;
     RECT  13.176 2.533 13.77 2.569 ;
     RECT  8.784 2.371 11.394 2.587 ;
     RECT  0.216 2.191 1.782 2.605 ;
     RECT  2.52 2.533 3.006 2.605 ;
     RECT  5.655 2.395 7.254 2.605 ;
     RECT  8.172 2.587 11.394 2.605 ;
     RECT  13.104 2.569 13.77 2.605 ;
     RECT  0.036 2.605 3.006 2.641 ;
     RECT  12.888 2.605 13.77 2.641 ;
     RECT  14.688 1.949 14.778 2.641 ;
     RECT  15.552 2.497 17.01 2.641 ;
     RECT  5.655 2.605 11.394 2.731 ;
     RECT  15.552 2.641 17.046 2.765 ;
     RECT  4.86 2.731 4.878 2.803 ;
     RECT  5.655 2.731 12.006 2.803 ;
     RECT  4.86 2.803 12.006 2.827 ;
     RECT  12.744 2.641 13.77 2.827 ;
     RECT  4.86 2.827 13.77 2.839 ;
     RECT  14.508 2.641 14.778 2.839 ;
     RECT  4.86 2.839 14.778 2.911 ;
     RECT  4.788 2.911 14.778 3.065 ;
     RECT  10.044 3.065 14.778 3.067 ;
     RECT  15.552 2.765 17.01 3.067 ;
     RECT  0.036 2.641 3.546 3.073 ;
     RECT  4.788 3.065 9.09 3.073 ;
     RECT  0.036 3.073 9.09 3.335 ;
     RECT  10.044 3.067 17.01 3.721 ;
     RECT  0.036 3.335 8.442 4.013 ;
     RECT  5.472 4.013 8.442 4.081 ;
     RECT  9.18 3.787 9.198 4.081 ;
     RECT  5.472 4.081 9.198 4.261 ;
     RECT  10.044 3.721 17.046 4.261 ;
     RECT  0.036 4.013 4.626 4.379 ;
     RECT  5.472 4.261 17.046 4.451 ;
     RECT  5.472 4.451 9.738 4.523 ;
     RECT  1.62 4.379 4.626 4.891 ;
     RECT  5.472 4.523 6.534 4.891 ;
     RECT  1.62 4.891 6.534 5.117 ;
     RECT  0.036 4.379 0.882 5.233 ;
     RECT  1.62 5.117 3.546 5.233 ;
     RECT  7.416 4.523 9.738 5.269 ;
     RECT  10.476 4.451 17.046 5.269 ;
     RECT  4.32 5.117 6.534 5.467 ;
     RECT  7.416 5.269 17.046 5.467 ;
     RECT  4.32 5.467 17.046 5.645 ;
     RECT  8.568 5.645 16.974 5.765 ;
     RECT  4.32 5.645 7.794 5.789 ;
     RECT  10.908 5.765 16.974 5.801 ;
     RECT  10.908 5.801 13.698 5.909 ;
     RECT  0.036 5.233 3.546 5.995 ;
     RECT  4.32 5.789 7.722 5.995 ;
     RECT  8.568 5.765 10.026 6.511 ;
     RECT  10.908 5.909 13.626 6.511 ;
     RECT  14.58 5.801 16.974 6.619 ;
     RECT  0.036 5.995 7.722 6.763 ;
     RECT  8.568 6.511 13.626 6.763 ;
     RECT  14.58 6.619 17.01 6.763 ;
     RECT  0.036 6.763 17.01 6.917 ;
     RECT  0.036 6.917 3.042 6.953 ;
     RECT  3.816 6.917 17.01 7.321 ;
     RECT  0.036 6.953 3.006 7.421 ;
     RECT  3.816 7.321 17.046 7.661 ;
     RECT  3.816 7.661 16.974 7.901 ;
     RECT  8.532 7.901 16.974 7.961 ;
     RECT  2.556 7.421 3.006 7.969 ;
     RECT  3.816 7.901 7.758 8.045 ;
     RECT  0.036 7.421 1.782 8.167 ;
     RECT  2.556 7.969 3.042 8.167 ;
     RECT  10.404 7.961 16.974 8.285 ;
     RECT  0.036 8.167 3.042 8.299 ;
     RECT  3.816 8.045 4.23 8.299 ;
     RECT  10.404 8.285 11.466 8.465 ;
     RECT  0.036 8.299 4.23 8.537 ;
     RECT  4.968 8.045 7.758 8.779 ;
     RECT  8.532 7.961 9.63 8.779 ;
     RECT  4.968 8.779 9.63 8.941 ;
     RECT  10.404 8.465 11.43 8.941 ;
     RECT  4.536 8.941 11.43 9.211 ;
     RECT  12.348 8.285 16.974 9.211 ;
     RECT  0.036 8.537 3.546 9.259 ;
     RECT  4.536 9.211 16.974 9.259 ;
     RECT  0.036 9.259 16.974 9.437 ;
     RECT  1.62 9.437 16.974 9.481 ;
     RECT  1.62 9.481 17.046 9.533 ;
     RECT  1.62 9.533 16.974 9.581 ;
     RECT  1.62 9.581 2.394 9.677 ;
     RECT  3.204 9.581 16.974 9.689 ;
     RECT  3.204 9.689 9.666 9.725 ;
     RECT  3.204 9.725 3.726 10.049 ;
     RECT  10.476 9.689 16.974 10.049 ;
     RECT  10.728 10.049 16.974 10.085 ;
     RECT  4.5 9.725 9.666 10.229 ;
     RECT  1.728 9.677 2.394 10.319 ;
     RECT  10.728 10.085 12.222 10.349 ;
     RECT  1.728 10.319 2.286 10.435 ;
     RECT  3.204 10.049 3.618 10.471 ;
     RECT  12.96 10.085 16.974 10.471 ;
     RECT  12.96 10.471 17.046 10.561 ;
     RECT  1.548 10.435 2.286 10.597 ;
     RECT  0.036 9.437 0.774 10.603 ;
     RECT  1.512 10.597 2.286 10.603 ;
     RECT  12.96 10.561 17.082 10.661 ;
     RECT  12.96 10.661 17.046 10.769 ;
     RECT  3.168 10.471 3.618 10.843 ;
     RECT  10.764 10.349 12.222 10.903 ;
     RECT  12.96 10.769 16.974 10.903 ;
     RECT  4.86 10.229 9.666 10.975 ;
     RECT  3.168 10.843 3.87 11.083 ;
     RECT  4.68 10.975 9.666 11.083 ;
     RECT  10.764 10.903 16.974 11.173 ;
     RECT  0.036 10.603 2.286 11.245 ;
     RECT  3.168 11.083 9.666 11.245 ;
     RECT  0.036 11.245 9.666 11.261 ;
     RECT  0.036 11.261 3.978 11.741 ;
     RECT  8.532 11.261 9.666 11.749 ;
     RECT  10.404 11.173 16.974 11.749 ;
     RECT  4.788 11.261 7.794 11.983 ;
     RECT  8.532 11.749 16.974 11.983 ;
     RECT  2.268 11.741 3.978 11.995 ;
     RECT  4.788 11.983 16.974 11.995 ;
     RECT  2.268 11.995 16.974 12.172 ;
     RECT  2.268 12.172 17.01 12.281 ;
     RECT  10.188 12.281 17.01 12.365 ;
     RECT  0.036 11.741 1.494 12.619 ;
     RECT  2.268 12.281 9.45 12.619 ;
     RECT  0.036 12.619 9.45 12.857 ;
     RECT  3.312 12.857 9.45 13.027 ;
     RECT  10.188 12.365 16.974 13.027 ;
     RECT  3.312 13.027 16.974 13.037 ;
     RECT  9.144 13.037 16.974 13.127 ;
     RECT  10.152 13.127 16.974 13.135 ;
     RECT  10.152 13.135 17.046 13.631 ;
     RECT  3.312 13.037 8.226 13.771 ;
     RECT  3.312 13.771 8.298 13.909 ;
     RECT  9.144 13.127 9.378 13.909 ;
     RECT  12.42 13.631 17.046 13.937 ;
     RECT  0.036 12.857 2.358 13.945 ;
     RECT  3.312 13.909 9.378 13.945 ;
     RECT  10.152 13.631 11.574 14.099 ;
     RECT  10.152 14.099 11.502 14.171 ;
     RECT  0.036 13.945 9.378 14.251 ;
     RECT  10.152 14.171 11.337 14.251 ;
     RECT  12.42 13.937 16.974 14.449 ;
     RECT  12.384 14.449 16.974 14.587 ;
     RECT  0.036 14.251 11.337 14.639 ;
     RECT  10.692 14.639 11.337 14.675 ;
     RECT  12.312 14.587 16.974 14.675 ;
     RECT  14.148 14.675 16.974 14.683 ;
     RECT  14.148 14.683 17.046 14.711 ;
     RECT  14.328 14.711 17.046 14.783 ;
     RECT  14.76 14.783 17.046 14.819 ;
     RECT  0.036 14.639 9.666 14.861 ;
     RECT  12.312 14.675 13.302 14.923 ;
     RECT  10.836 14.675 11.337 15.061 ;
     RECT  12.204 14.923 13.302 15.061 ;
     RECT  10.836 15.061 13.302 15.448 ;
     RECT  10.764 15.448 13.302 15.451 ;
     RECT  10.764 15.451 13.806 15.457 ;
     RECT  10.62 15.457 13.806 15.493 ;
     RECT  10.512 15.493 13.806 15.565 ;
     RECT  0.036 14.861 9.558 15.601 ;
     RECT  10.512 15.565 13.878 15.601 ;
     RECT  0.036 15.601 13.878 15.961 ;
     RECT  14.76 14.819 16.974 15.961 ;
     RECT  0.036 15.961 17.046 16.061 ;
     RECT  0.036 16.061 16.974 16.259 ;
     RECT  9.324 16.259 16.974 16.367 ;
     RECT  10.224 16.367 16.974 16.529 ;
     RECT  10.404 16.529 16.974 16.589 ;
     RECT  0.036 16.259 8.514 16.835 ;
     RECT  10.404 16.589 15.642 17.069 ;
     RECT  5.364 16.835 8.514 17.311 ;
     RECT  9.324 16.367 9.378 17.311 ;
     RECT  5.364 17.311 9.378 17.347 ;
     RECT  10.404 17.069 13.734 17.347 ;
     RECT  14.688 17.069 15.642 17.347 ;
     RECT  16.416 16.589 16.974 17.347 ;
     RECT  14.688 17.347 16.974 17.419 ;
     RECT  0.036 16.835 4.626 17.456 ;
     RECT  14.688 17.419 17.046 17.609 ;
     RECT  3.996 17.456 4.626 17.689 ;
     RECT  5.364 17.347 13.734 17.689 ;
     RECT  3.996 17.689 13.734 17.995 ;
     RECT  3.996 17.995 14.094 18.023 ;
     RECT  9.108 18.023 14.094 18.221 ;
     RECT  12.528 18.221 14.094 18.257 ;
     RECT  0.036 17.456 3.15 18.265 ;
     RECT  0.036 18.265 3.186 18.283 ;
     RECT  3.996 18.023 8.334 18.283 ;
     RECT  12.708 18.257 14.094 18.571 ;
     RECT  15.156 17.609 17.046 18.571 ;
     RECT  12.708 18.571 14.13 18.661 ;
     RECT  14.976 18.571 17.046 18.661 ;
     RECT  12.708 18.661 17.046 18.749 ;
     RECT  0.036 18.283 8.334 18.763 ;
     RECT  9.108 18.221 11.646 18.763 ;
     RECT  0.036 18.763 11.646 19.111 ;
     RECT  0.036 19.111 11.934 19.273 ;
     RECT  12.708 18.749 16.974 19.273 ;
     RECT  0.036 19.273 16.974 19.499 ;
     RECT  10.08 19.499 16.974 19.643 ;
     RECT  10.08 19.643 12.294 19.679 ;
     RECT  10.224 19.679 12.294 19.805 ;
     RECT  10.44 19.805 12.294 19.877 ;
     RECT  13.068 19.643 16.974 20.107 ;
     RECT  10.44 19.877 12.186 20.623 ;
     RECT  13.068 20.107 17.046 20.623 ;
     RECT  10.44 20.623 17.046 20.695 ;
     RECT  0.036 19.499 9.27 20.731 ;
     RECT  10.188 20.695 17.046 20.731 ;
     RECT  0.036 20.731 17.046 20.993 ;
     RECT  0.036 20.993 16.974 21.389 ;
     RECT  2.016 21.389 16.974 21.659 ;
     RECT  0.036 21.389 1.278 21.731 ;
     RECT  2.052 21.659 16.974 21.931 ;
     RECT  2.052 21.931 17.046 22.109 ;
     RECT  0.036 21.731 0.702 22.459 ;
     RECT  2.052 22.109 16.974 22.469 ;
     RECT  0.036 22.459 1.17 22.507 ;
     RECT  2.052 22.469 12.078 22.507 ;
     RECT  12.816 22.469 16.974 22.577 ;
     RECT  0.036 22.507 12.078 23.323 ;
     RECT  12.888 22.577 16.974 23.323 ;
     RECT  0.036 23.323 16.974 23.611 ;
     RECT  0.036 23.611 17.046 23.885 ;
     RECT  0.036 23.885 16.974 23.927 ;
     RECT  0.036 23.927 4.05 24.089 ;
     RECT  0.036 24.089 4.014 24.871 ;
     RECT  4.824 23.927 16.974 24.871 ;
     RECT  0.036 24.871 16.974 24.899 ;
     RECT  12.384 24.899 16.974 25.051 ;
     RECT  12.384 25.051 17.046 25.079 ;
     RECT  12.384 25.079 13.986 25.951 ;
     RECT  14.724 25.079 17.046 25.951 ;
     RECT  0.036 24.899 11.646 25.979 ;
     RECT  12.384 25.951 17.046 26.293 ;
     RECT  12.276 26.293 17.046 26.333 ;
     RECT  0.036 25.979 11.43 26.663 ;
     RECT  12.276 26.333 16.974 26.824 ;
     RECT  10.944 26.663 11.43 26.833 ;
     RECT  12.168 26.824 16.974 26.833 ;
     RECT  10.944 26.833 16.974 27.301 ;
     RECT  0.036 26.663 10.098 27.329 ;
     RECT  8.1 27.329 10.098 27.496 ;
     RECT  10.944 27.301 17.01 27.499 ;
     RECT  10.872 27.499 17.01 27.581 ;
     RECT  0.036 27.329 7.326 27.599 ;
     RECT  8.1 27.496 9.054 27.599 ;
     RECT  9.792 27.496 10.098 27.599 ;
     RECT  0.036 27.599 3.87 27.635 ;
     RECT  9.864 27.599 9.882 27.635 ;
     RECT  10.872 27.581 16.974 27.635 ;
     RECT  10.872 27.635 14.778 27.643 ;
     RECT  10.836 27.643 14.778 27.715 ;
     RECT  0.036 27.635 3.834 27.725 ;
     RECT  15.516 27.635 16.974 27.743 ;
     RECT  0.144 27.725 3.834 27.779 ;
     RECT  10.656 27.715 14.778 27.779 ;
     RECT  4.968 27.599 7.326 27.869 ;
     RECT  10.656 27.779 14.598 27.869 ;
     RECT  15.516 27.743 15.606 27.869 ;
     RECT  16.455 27.743 16.974 27.869 ;
     RECT  0.18 27.779 3.834 27.905 ;
     RECT  10.656 27.869 11.97 27.905 ;
     RECT  13.572 27.869 13.662 27.905 ;
     RECT  0.18 27.905 3.582 27.917 ;
     RECT  8.1 27.599 9.018 27.917 ;
     RECT  8.1 27.917 8.73 27.941 ;
     RECT  10.872 27.905 11.97 27.941 ;
     RECT  8.352 27.941 8.73 27.977 ;
     RECT  0.18 27.917 3.186 28.139 ;
     RECT  4.968 27.869 6.246 28.139 ;
     RECT  8.352 27.977 8.658 28.139 ;
     RECT  11.055 27.941 11.97 28.139 ;
     RECT  12.816 27.869 12.834 28.139 ;
     RECT  13.644 27.905 13.662 28.139 ;
     RECT  0.18 28.139 0.594 28.157 ;
     RECT  2.592 28.139 2.97 28.175 ;
     RECT  8.352 28.139 8.37 28.175 ;
     RECT  1.44 28.139 1.854 28.409 ;
     RECT  2.592 28.175 2.61 28.409 ;
     RECT  0.18 28.157 0.537 28.445 ;
     RECT  1.44 28.409 1.458 28.553 ;
     RECT  0.255 28.445 0.537 29.177 ;
     RECT  5.655 28.139 5.937 29.177 ;
     RECT  11.055 28.139 11.337 29.177 ;
     RECT  16.455 27.869 16.737 29.177 ;
     RECT  0.447 29.177 0.537 29.447 ;
     RECT  5.847 29.177 5.937 29.447 ;
     RECT  11.247 29.177 11.337 29.447 ;
     RECT  16.647 29.177 16.737 29.447 ;
    LAYER M4 ;
     RECT  0.025 3.216 0.037 3.24 ;
     RECT  0.025 4.32 0.037 19.416 ;
     RECT  0.025 21.024 0.037 27.72 ;
     RECT  0.037 2.736 0.133 19.416 ;
     RECT  0.037 20.544 0.133 27.72 ;
     RECT  0.133 2.736 0.248 27.72 ;
     RECT  0.248 0.528 0.352 29.172 ;
     RECT  0.352 0.798 0.44 29.172 ;
     RECT  0.44 0.798 0.544 29.442 ;
     RECT  0.544 2.208 1.469 28.152 ;
     RECT  1.469 2.208 1.793 27.72 ;
     RECT  1.793 2.832 2.761 27.72 ;
     RECT  2.761 2.832 3.593 27.912 ;
     RECT  3.593 2.832 3.881 27.624 ;
     RECT  3.881 2.832 5.648 27.432 ;
     RECT  5.648 0.528 5.752 29.172 ;
     RECT  5.752 0.798 5.84 29.172 ;
     RECT  5.84 0.798 5.944 29.442 ;
     RECT  5.944 2.4 7.265 27.432 ;
     RECT  7.265 2.592 8.201 27.432 ;
     RECT  8.201 2.832 8.341 27.432 ;
     RECT  8.341 2.832 9.029 27.912 ;
     RECT  9.029 2.832 9.205 27.528 ;
     RECT  9.205 2.784 9.677 27.528 ;
     RECT  9.677 2.832 11.048 27.528 ;
     RECT  11.048 0.528 11.152 29.172 ;
     RECT  11.152 0.798 11.24 29.172 ;
     RECT  11.24 0.798 11.344 29.442 ;
     RECT  11.344 2.832 13.345 27.432 ;
     RECT  13.345 2.448 13.601 27.432 ;
     RECT  13.601 2.448 13.781 27.336 ;
     RECT  13.781 2.592 14.717 27.336 ;
     RECT  14.717 2.976 14.749 27.336 ;
     RECT  14.749 2.976 14.821 27.384 ;
     RECT  14.821 2.976 16.369 27.48 ;
     RECT  16.369 2.88 16.448 27.48 ;
     RECT  16.448 0.528 16.552 29.172 ;
     RECT  16.552 0.798 16.64 29.172 ;
     RECT  16.64 0.798 16.744 29.442 ;
     RECT  16.744 2.736 17.021 27.576 ;
     RECT  17.021 2.736 17.1 27.48 ;
    LAYER M5 ;
     RECT  0.24 0.517 0.36 0.787 ;
     RECT  5.64 0.517 5.76 0.787 ;
     RECT  11.04 0.517 11.16 0.787 ;
     RECT  16.44 0.517 16.56 0.787 ;
     RECT  0.24 0.787 0.552 2.725 ;
     RECT  11.04 0.787 11.352 2.821 ;
     RECT  16.44 0.787 16.752 2.821 ;
     RECT  11.04 2.821 12.024 2.963 ;
     RECT  2.544 2.869 2.664 3.061 ;
     RECT  2.256 3.061 2.664 3.155 ;
     RECT  2.256 3.155 2.568 3.347 ;
     RECT  2.256 3.347 2.376 3.395 ;
     RECT  0.048 2.725 0.552 3.493 ;
     RECT  0.048 3.493 0.648 3.637 ;
     RECT  0.048 3.637 1.08 3.755 ;
     RECT  0.048 3.755 0.648 3.827 ;
     RECT  9.216 2.773 9.24 3.827 ;
     RECT  13.872 3.781 13.896 3.923 ;
     RECT  16.44 2.821 16.968 4.051 ;
     RECT  5.64 0.787 5.952 4.069 ;
     RECT  11.04 2.963 11.352 4.069 ;
     RECT  16.32 4.051 16.968 4.139 ;
     RECT  16.44 4.139 16.968 4.163 ;
     RECT  11.04 4.069 12.024 4.489 ;
     RECT  2.352 3.395 2.376 4.547 ;
     RECT  0.096 3.827 0.648 4.835 ;
     RECT  3.984 5.045 4.008 5.077 ;
     RECT  16.44 4.163 16.752 5.125 ;
     RECT  3.168 5.077 4.008 5.133 ;
     RECT  5.64 4.069 6.072 5.139 ;
     RECT  8.544 4.549 8.568 5.171 ;
     RECT  3.168 5.133 3.192 5.227 ;
     RECT  5.64 5.139 6.36 5.227 ;
     RECT  1.968 5.317 1.992 5.507 ;
     RECT  16.44 5.125 16.872 6.037 ;
     RECT  15.792 6.037 16.872 6.179 ;
     RECT  0.096 4.835 0.552 6.251 ;
     RECT  0.144 6.251 0.552 6.261 ;
     RECT  1.824 5.797 1.848 6.275 ;
     RECT  14.832 6.239 14.856 6.323 ;
     RECT  16.176 6.179 16.872 6.767 ;
     RECT  16.176 6.767 17.064 6.851 ;
     RECT  16.176 6.851 16.872 6.861 ;
     RECT  3.984 6.837 4.008 6.925 ;
     RECT  0.144 6.261 0.648 7.619 ;
     RECT  7.296 7.717 7.32 7.765 ;
     RECT  7.2 7.765 7.32 7.851 ;
     RECT  9.216 7.765 9.24 7.851 ;
     RECT  16.44 6.861 16.872 7.957 ;
     RECT  7.296 7.851 7.32 8.051 ;
     RECT  2.256 8.053 2.28 8.195 ;
     RECT  16.272 7.957 16.872 8.309 ;
     RECT  7.344 8.275 7.368 8.363 ;
     RECT  16.272 8.309 16.92 8.435 ;
     RECT  13.2 8.341 13.224 8.437 ;
     RECT  0.144 7.619 0.552 8.627 ;
     RECT  13.104 8.437 13.224 8.627 ;
     RECT  13.68 8.677 13.704 8.761 ;
     RECT  16.32 8.435 16.92 9.013 ;
     RECT  5.64 5.227 5.952 9.061 ;
     RECT  16.32 9.013 17.064 9.067 ;
     RECT  16.44 9.067 17.064 9.107 ;
     RECT  14.832 9.061 14.856 9.203 ;
     RECT  1.968 9.109 1.992 9.251 ;
     RECT  0.24 8.627 0.552 9.695 ;
     RECT  0.24 9.695 0.648 9.717 ;
     RECT  0.144 9.717 0.648 9.939 ;
     RECT  11.04 4.489 11.352 9.973 ;
     RECT  0.144 9.939 0.744 10.027 ;
     RECT  11.04 9.973 12.024 10.067 ;
     RECT  11.04 10.067 11.496 10.165 ;
     RECT  10.848 10.165 11.496 10.219 ;
     RECT  5.64 9.061 6.888 10.307 ;
     RECT  10.848 10.219 11.352 10.355 ;
     RECT  10.944 10.355 11.352 10.411 ;
     RECT  13.248 10.323 13.272 10.411 ;
     RECT  16.44 9.107 16.752 10.549 ;
     RECT  3.408 9.637 3.432 10.883 ;
     RECT  16.44 10.549 16.872 11.171 ;
     RECT  2.256 11.125 2.28 11.209 ;
     RECT  7.104 10.837 7.512 11.341 ;
     RECT  7.104 11.341 7.128 11.939 ;
     RECT  11.04 10.411 11.352 12.143 ;
     RECT  11.04 12.143 11.448 12.227 ;
     RECT  12.528 12.191 12.552 12.275 ;
     RECT  16.44 11.171 16.752 12.661 ;
     RECT  16.32 12.661 16.752 12.719 ;
     RECT  16.32 12.719 16.968 12.779 ;
     RECT  16.44 12.779 16.968 12.803 ;
     RECT  5.64 10.307 5.952 12.901 ;
     RECT  3.264 12.757 3.288 12.947 ;
     RECT  0.144 10.027 0.648 12.971 ;
     RECT  5.64 12.901 6.072 12.985 ;
     RECT  3.936 13.109 4.248 13.235 ;
     RECT  2.112 13.429 2.136 13.477 ;
     RECT  2.112 13.477 2.28 13.561 ;
     RECT  2.112 13.561 2.136 13.571 ;
     RECT  3.936 13.235 3.96 13.955 ;
     RECT  0.24 12.971 0.648 13.957 ;
     RECT  0.24 13.957 0.744 14.005 ;
     RECT  0.144 14.005 0.744 14.059 ;
     RECT  16.44 12.803 16.752 14.197 ;
     RECT  3.264 14.101 3.288 14.243 ;
     RECT  13.104 14.163 13.128 14.251 ;
     RECT  0.144 14.059 0.648 14.579 ;
     RECT  16.44 14.197 16.872 14.931 ;
     RECT  2.4 15.023 2.424 15.107 ;
     RECT  0.144 14.579 0.552 15.117 ;
     RECT  11.04 12.227 11.352 15.407 ;
     RECT  7.584 15.379 7.608 15.467 ;
     RECT  10.752 15.407 11.352 15.491 ;
     RECT  7.44 15.541 7.464 15.625 ;
     RECT  16.32 14.931 16.872 15.733 ;
     RECT  15.792 15.733 16.872 15.829 ;
     RECT  15.792 15.829 16.968 15.875 ;
     RECT  16.44 15.875 16.968 15.973 ;
     RECT  16.44 15.973 17.064 16.057 ;
     RECT  0.24 15.117 0.552 16.175 ;
     RECT  0.24 16.175 0.648 16.181 ;
     RECT  12.336 16.117 13.128 16.427 ;
     RECT  5.64 12.985 5.952 16.821 ;
     RECT  2.256 16.741 2.28 16.875 ;
     RECT  5.424 16.821 5.952 17.003 ;
     RECT  16.44 16.057 16.872 17.077 ;
     RECT  15.024 17.077 15.048 17.161 ;
     RECT  16.44 17.077 16.968 17.171 ;
     RECT  0.144 16.181 0.648 17.267 ;
     RECT  3.072 17.029 3.096 17.267 ;
     RECT  13.104 16.427 13.128 17.939 ;
     RECT  11.04 15.491 11.352 18.143 ;
     RECT  0.24 17.267 0.648 18.357 ;
     RECT  16.44 17.171 16.752 18.579 ;
     RECT  16.32 18.579 16.752 18.613 ;
     RECT  16.32 18.613 16.968 18.667 ;
     RECT  13.008 18.661 13.032 18.757 ;
     RECT  12.864 18.757 13.032 18.795 ;
     RECT  16.44 18.667 16.968 18.803 ;
     RECT  12.864 18.795 12.888 18.923 ;
     RECT  11.04 18.143 11.448 19.045 ;
     RECT  5.64 17.003 5.952 19.381 ;
     RECT  11.04 19.045 11.496 19.477 ;
     RECT  10.944 19.477 11.496 19.667 ;
     RECT  16.44 18.803 16.872 19.765 ;
     RECT  16.44 19.765 16.968 19.893 ;
     RECT  16.32 19.893 16.968 19.947 ;
     RECT  11.04 19.667 11.496 19.957 ;
     RECT  9.216 18.757 9.24 20.051 ;
     RECT  11.04 19.957 12.024 20.051 ;
     RECT  5.64 19.381 6.312 20.437 ;
     RECT  5.64 20.437 7.128 20.523 ;
     RECT  0.144 18.357 0.648 20.533 ;
     RECT  12.528 20.639 12.552 20.723 ;
     RECT  16.32 19.947 16.872 20.755 ;
     RECT  0.048 20.533 0.648 20.843 ;
     RECT  15.984 20.755 16.872 20.843 ;
     RECT  2.112 20.773 2.136 20.857 ;
     RECT  16.32 20.843 16.872 20.917 ;
     RECT  16.32 20.917 17.064 21.035 ;
     RECT  13.632 20.917 13.656 21.059 ;
     RECT  16.32 21.035 16.752 21.069 ;
     RECT  0.144 20.843 0.648 21.205 ;
     RECT  11.04 20.051 11.352 21.237 ;
     RECT  0.144 21.205 0.888 21.291 ;
     RECT  11.04 21.237 11.928 21.325 ;
     RECT  5.64 20.523 6.744 21.419 ;
     RECT  9.456 21.331 9.48 21.419 ;
     RECT  0.144 21.291 0.744 21.483 ;
     RECT  5.64 21.419 6.408 21.491 ;
     RECT  12.96 21.407 12.984 21.491 ;
     RECT  0.144 21.483 0.648 21.611 ;
     RECT  0.24 21.611 0.648 21.625 ;
     RECT  5.64 21.491 6.312 21.709 ;
     RECT  16.44 21.069 16.752 22.357 ;
     RECT  2.256 21.397 2.28 22.405 ;
     RECT  4.128 22.389 4.152 22.477 ;
     RECT  1.776 22.405 2.28 22.547 ;
     RECT  7.92 22.453 7.944 22.595 ;
     RECT  0.24 21.625 0.552 22.693 ;
     RECT  5.64 21.709 5.952 22.741 ;
     RECT  0.144 22.693 0.552 22.933 ;
     RECT  16.44 22.357 16.872 23.029 ;
     RECT  11.04 21.325 11.352 23.317 ;
     RECT  10.944 23.317 11.352 23.365 ;
     RECT  10.944 23.365 11.448 23.555 ;
     RECT  16.32 23.029 16.872 23.557 ;
     RECT  3.936 23.509 3.96 23.595 ;
     RECT  13.104 23.519 13.128 23.603 ;
     RECT  16.32 23.557 16.92 23.699 ;
     RECT  0.144 22.933 0.648 23.787 ;
     RECT  0.24 23.787 0.648 23.891 ;
     RECT  8.496 23.989 8.52 24.083 ;
     RECT  16.44 23.699 16.92 24.181 ;
     RECT  10.944 23.555 11.352 24.227 ;
     RECT  5.64 22.741 6.264 24.229 ;
     RECT  2.88 24.229 2.904 24.467 ;
     RECT  13.296 23.701 13.32 24.515 ;
     RECT  5.64 24.229 6.84 24.659 ;
     RECT  5.64 24.659 5.952 24.723 ;
     RECT  5.424 24.723 5.952 24.811 ;
     RECT  0.24 23.891 0.552 24.853 ;
     RECT  2.976 24.885 3 25.043 ;
     RECT  16.44 24.181 16.968 25.171 ;
     RECT  16.176 25.171 16.968 25.259 ;
     RECT  16.44 25.259 16.968 25.273 ;
     RECT  0.144 24.853 0.552 25.397 ;
     RECT  9.696 25.717 9.72 25.765 ;
     RECT  13.008 25.669 13.032 25.765 ;
     RECT  9.12 25.765 9.72 25.801 ;
     RECT  12.912 25.765 13.032 25.811 ;
     RECT  14.832 25.669 14.856 25.811 ;
     RECT  5.64 24.811 5.952 25.909 ;
     RECT  0.144 25.397 0.648 25.963 ;
     RECT  12.912 25.811 12.936 26.099 ;
     RECT  0.24 25.963 0.648 26.159 ;
     RECT  2.256 26.159 2.28 26.197 ;
     RECT  2.16 26.197 2.28 26.207 ;
     RECT  0.24 26.159 1.176 26.276 ;
     RECT  2.16 26.207 2.856 26.291 ;
     RECT  2.16 26.291 2.28 26.347 ;
     RECT  9.12 25.801 9.144 26.389 ;
     RECT  8.88 26.389 9.144 26.531 ;
     RECT  16.44 25.273 16.872 26.533 ;
     RECT  16.44 26.533 16.92 26.591 ;
     RECT  16.44 26.591 17.064 26.613 ;
     RECT  15.792 26.613 17.064 26.675 ;
     RECT  5.64 25.909 6.072 26.677 ;
     RECT  15.792 26.675 16.968 26.701 ;
     RECT  16.32 26.701 16.968 26.795 ;
     RECT  0.24 26.276 0.648 26.965 ;
     RECT  9.12 26.531 9.144 27.011 ;
     RECT  0.144 26.965 0.648 27.051 ;
     RECT  5.64 26.677 6.888 27.283 ;
     RECT  0.24 27.051 0.648 27.299 ;
     RECT  5.472 27.283 6.888 27.371 ;
     RECT  16.44 26.795 16.968 27.587 ;
     RECT  0.24 27.299 0.552 29.183 ;
     RECT  5.64 27.371 5.952 29.183 ;
     RECT  11.04 24.227 11.352 29.183 ;
     RECT  16.44 27.587 16.752 29.183 ;
     RECT  0.432 29.183 0.552 29.453 ;
     RECT  5.832 29.183 5.952 29.453 ;
     RECT  11.232 29.183 11.352 29.453 ;
     RECT  16.632 29.183 16.752 29.453 ;
    LAYER M6 ;
     RECT  0 0.996 0.037 1.86 ;
     RECT  0.037 0.996 0.053 3.616 ;
     RECT  0 6.396 0.053 7.26 ;
     RECT  0.053 0.996 0.107 4.512 ;
     RECT  0.107 3.584 0.131 4.512 ;
     RECT  0.053 6.208 0.131 7.26 ;
     RECT  0.131 6.272 0.133 7.26 ;
     RECT  0 11.796 0.133 12.66 ;
     RECT  0.053 15.552 0.133 15.584 ;
     RECT  0 17.196 0.133 18.06 ;
     RECT  0.037 20.8 0.133 20.832 ;
     RECT  0 22.596 0.133 23.46 ;
     RECT  0 27.996 0.133 28.86 ;
     RECT  0.131 3.584 0.659 4.448 ;
     RECT  0.133 9.728 0.659 28.86 ;
     RECT  0.659 11.796 0.755 23.46 ;
     RECT  0.659 3.712 1.091 4.448 ;
     RECT  0.659 9.984 2.245 10.208 ;
     RECT  0.755 11.796 2.245 13.536 ;
     RECT  2.245 9.984 2.291 13.536 ;
     RECT  0.755 15.04 2.435 23.46 ;
     RECT  0.659 24.896 3.011 26.528 ;
     RECT  1.091 4.224 3.157 4.448 ;
     RECT  0.133 6.272 3.157 8.352 ;
     RECT  2.435 15.552 3.925 23.46 ;
     RECT  3.925 15.552 4.203 23.584 ;
     RECT  2.291 9.984 4.213 12.96 ;
     RECT  4.213 9.984 4.282 13.152 ;
     RECT  3.011 25.92 5.109 26.528 ;
     RECT  5.109 25.728 5.413 26.528 ;
     RECT  5.413 24.768 5.461 26.528 ;
     RECT  0.659 27.996 5.461 28.86 ;
     RECT  5.461 24.768 5.483 28.86 ;
     RECT  3.157 4.224 6.083 8.352 ;
     RECT  4.282 9.984 6.083 12.96 ;
     RECT  5.483 25.728 6.899 28.86 ;
     RECT  4.203 15.552 7.162 23.46 ;
     RECT  7.162 15.552 7.349 19.232 ;
     RECT  6.083 4.416 7.379 8.352 ;
     RECT  7.349 15.424 7.619 19.232 ;
     RECT  7.162 20.672 8.485 23.46 ;
     RECT  8.485 20.672 8.555 24.032 ;
     RECT  6.899 25.728 9.155 26.528 ;
     RECT  7.379 4.416 9.19 7.26 ;
     RECT  9.19 4.416 9.205 7.84 ;
     RECT  9.205 4.096 9.259 7.84 ;
     RECT  9.259 6.272 9.397 7.84 ;
     RECT  6.083 9.984 9.397 12.66 ;
     RECT  9.397 6.272 9.451 12.66 ;
     RECT  9.155 25.728 9.731 25.76 ;
     RECT  7.619 16.384 10.741 19.232 ;
     RECT  10.741 15.424 10.81 19.232 ;
     RECT  9.451 8.704 10.837 10.016 ;
     RECT  10.837 8.704 10.933 10.208 ;
     RECT  10.81 16.384 11.989 19.232 ;
     RECT  8.555 20.672 11.989 23.46 ;
     RECT  9.259 4.096 12.035 4.448 ;
     RECT  10.933 8.704 12.035 10.4 ;
     RECT  11.989 16.384 12.075 23.46 ;
     RECT  12.075 16.384 12.371 18.912 ;
     RECT  12.075 20.672 12.563 23.46 ;
     RECT  12.371 17.196 12.899 18.912 ;
     RECT  12.563 21.376 12.981 23.46 ;
     RECT  12.981 21.376 13.035 23.584 ;
     RECT  12.899 17.196 13.043 18.784 ;
     RECT  13.035 22.596 13.139 23.584 ;
     RECT  12.035 10.368 13.283 10.4 ;
     RECT  12.035 8.704 13.715 8.736 ;
     RECT  9.451 6.272 14.867 7.26 ;
     RECT  13.043 17.196 15.013 18.06 ;
     RECT  14.867 6.396 16.309 7.26 ;
     RECT  9.451 11.796 16.309 12.66 ;
     RECT  13.093 14.208 16.309 14.24 ;
     RECT  15.013 17.088 16.309 18.06 ;
     RECT  15.973 20.8 16.309 20.832 ;
     RECT  13.139 22.596 16.309 23.46 ;
     RECT  15.781 26.624 16.309 26.656 ;
     RECT  6.899 27.996 16.309 28.86 ;
     RECT  0.107 0.996 16.56 1.86 ;
     RECT  16.309 6.396 16.56 9.056 ;
     RECT  16.309 11.796 16.56 12.768 ;
     RECT  16.309 22.596 16.56 23.648 ;
     RECT  16.309 26.624 16.56 28.86 ;
     RECT  16.56 1.572 16.752 1.86 ;
     RECT  16.56 6.784 16.752 9.056 ;
     RECT  16.56 12.372 16.752 12.768 ;
     RECT  16.309 17.088 16.752 21.024 ;
     RECT  16.56 28.572 16.752 28.86 ;
     RECT  16.309 14.208 16.837 15.008 ;
     RECT  16.752 17.088 16.837 17.12 ;
     RECT  16.56 23.04 16.837 23.648 ;
     RECT  16.165 25.216 16.837 25.248 ;
     RECT  16.837 14.208 16.883 17.12 ;
     RECT  16.837 23.04 16.883 25.248 ;
     RECT  16.56 26.624 16.883 26.784 ;
     RECT  16.752 8.32 16.931 9.056 ;
     RECT  16.883 23.616 16.931 25.248 ;
     RECT  16.309 4.096 16.979 4.128 ;
     RECT  16.752 12.736 16.979 12.768 ;
     RECT  16.883 16 16.979 17.12 ;
     RECT  16.752 18.624 16.979 21.024 ;
     RECT  16.931 24.32 16.979 25.248 ;
     RECT  16.752 6.784 17.075 6.816 ;
     RECT  16.931 9.024 17.075 9.056 ;
     RECT  16.979 16 17.075 16.032 ;
     RECT  16.979 20.992 17.075 21.024 ;
     RECT  16.883 26.624 17.075 26.656 ;
    LAYER M7 ;
     RECT  0.856 0.531 1.144 2.741 ;
     RECT  0.064 2.741 1.144 4.523 ;
     RECT  0.856 4.523 1.144 6.197 ;
     RECT  3.968 5.045 4 6.891 ;
     RECT  9.216 4.085 9.248 7.797 ;
     RECT  9.216 7.797 9.44 7.851 ;
     RECT  6.256 0.531 6.544 11.253 ;
     RECT  11.656 0.531 11.944 12.213 ;
     RECT  9.408 7.851 9.44 12.267 ;
     RECT  4.224 11.125 4.256 13.163 ;
     RECT  10.752 12.213 11.944 15.467 ;
     RECT  0.064 6.197 1.144 15.595 ;
     RECT  6.256 11.253 7.392 15.979 ;
     RECT  6.256 15.979 7.136 16.949 ;
     RECT  11.656 15.467 11.944 18.741 ;
     RECT  5.44 16.949 7.136 20.523 ;
     RECT  5.44 20.523 6.544 22.389 ;
     RECT  4.16 22.389 6.544 23.595 ;
     RECT  11.656 18.741 13.024 23.595 ;
     RECT  8.512 22.453 8.544 24.043 ;
     RECT  5.44 23.595 6.544 25.717 ;
     RECT  5.12 25.717 6.544 26.283 ;
     RECT  0.856 15.595 1.144 29.439 ;
     RECT  6.256 26.283 6.544 29.439 ;
     RECT  11.656 23.595 11.944 29.439 ;
  END
END dsfd_stnh_512x1
END LIBRARY
